VERSION 5.8 ;
BUSBITCHARS "[]" ;
DIVIDERCHAR "/" ;
UNITS
    DATABASE MICRONS 1000 ;
END UNITS

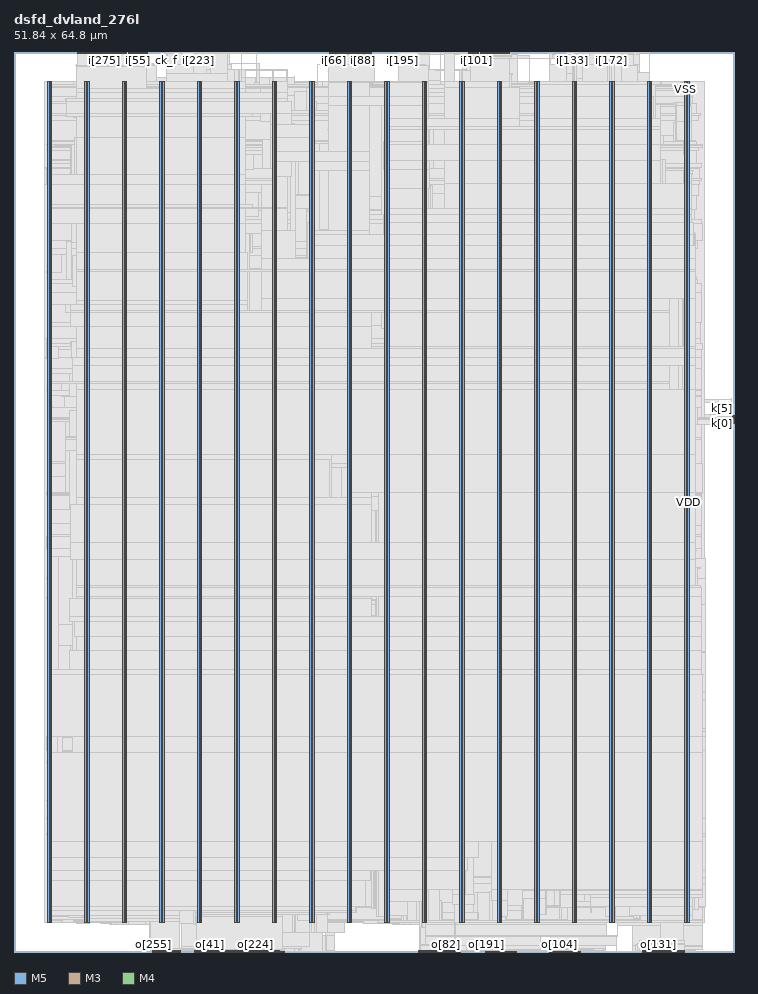
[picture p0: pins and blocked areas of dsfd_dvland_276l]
MACRO dsfd_dvland_276l
  FOREIGN dsfd_dvland_276l 0 0 ;
  CLASS BLOCK ;
  SIZE 51.84 BY 64.8 ;
  PIN ck
    DIRECTION INPUT ;
    USE SIGNAL ;
    PORT
      LAYER M5 ;
        RECT  16.08 0 16.104 0.084 ;
    END
  END ck
  PIN ck_f
    DIRECTION INPUT ;
    USE SIGNAL ;
    PORT
      LAYER M3 ;
        RECT  10.98 64.763 10.998 64.8 ;
    END
  END ck_f
  PIN fault
    DIRECTION OUTPUT ;
    USE SIGNAL ;
    PORT
      LAYER M5 ;
        RECT  16.176 0 16.2 0.084 ;
    END
  END fault
  PIN i[0]
    DIRECTION INPUT ;
    USE SIGNAL ;
    PORT
      LAYER M3 ;
        RECT  11.052 64.763 11.07 64.8 ;
    END
  END i[0]
  PIN i[100]
    DIRECTION INPUT ;
    USE SIGNAL ;
    PORT
      LAYER M5 ;
        RECT  33.168 64.716 33.192 64.8 ;
    END
  END i[100]
  PIN i[101]
    DIRECTION INPUT ;
    USE SIGNAL ;
    PORT
      LAYER M5 ;
        RECT  33.264 64.716 33.288 64.8 ;
    END
  END i[101]
  PIN i[102]
    DIRECTION INPUT ;
    USE SIGNAL ;
    PORT
      LAYER M5 ;
        RECT  33.36 64.716 33.384 64.8 ;
    END
  END i[102]
  PIN i[103]
    DIRECTION INPUT ;
    USE SIGNAL ;
    PORT
      LAYER M5 ;
        RECT  33.456 64.716 33.48 64.8 ;
    END
  END i[103]
  PIN i[104]
    DIRECTION INPUT ;
    USE SIGNAL ;
    PORT
      LAYER M5 ;
        RECT  33.552 64.716 33.576 64.8 ;
    END
  END i[104]
  PIN i[105]
    DIRECTION INPUT ;
    USE SIGNAL ;
    PORT
      LAYER M5 ;
        RECT  33.648 64.716 33.672 64.8 ;
    END
  END i[105]
  PIN i[106]
    DIRECTION INPUT ;
    USE SIGNAL ;
    PORT
      LAYER M5 ;
        RECT  33.744 64.716 33.768 64.8 ;
    END
  END i[106]
  PIN i[107]
    DIRECTION INPUT ;
    USE SIGNAL ;
    PORT
      LAYER M5 ;
        RECT  33.84 64.716 33.864 64.8 ;
    END
  END i[107]
  PIN i[108]
    DIRECTION INPUT ;
    USE SIGNAL ;
    PORT
      LAYER M5 ;
        RECT  33.936 64.716 33.96 64.8 ;
    END
  END i[108]
  PIN i[109]
    DIRECTION INPUT ;
    USE SIGNAL ;
    PORT
      LAYER M5 ;
        RECT  34.032 64.716 34.056 64.8 ;
    END
  END i[109]
  PIN i[10]
    DIRECTION INPUT ;
    USE SIGNAL ;
    PORT
      LAYER M3 ;
        RECT  11.772 64.763 11.79 64.8 ;
    END
  END i[10]
  PIN i[110]
    DIRECTION INPUT ;
    USE SIGNAL ;
    PORT
      LAYER M5 ;
        RECT  34.128 64.716 34.152 64.8 ;
    END
  END i[110]
  PIN i[111]
    DIRECTION INPUT ;
    USE SIGNAL ;
    PORT
      LAYER M5 ;
        RECT  34.224 64.716 34.248 64.8 ;
    END
  END i[111]
  PIN i[112]
    DIRECTION INPUT ;
    USE SIGNAL ;
    PORT
      LAYER M5 ;
        RECT  34.32 64.716 34.344 64.8 ;
    END
  END i[112]
  PIN i[113]
    DIRECTION INPUT ;
    USE SIGNAL ;
    PORT
      LAYER M5 ;
        RECT  34.416 64.716 34.44 64.8 ;
    END
  END i[113]
  PIN i[114]
    DIRECTION INPUT ;
    USE SIGNAL ;
    PORT
      LAYER M5 ;
        RECT  34.512 64.716 34.536 64.8 ;
    END
  END i[114]
  PIN i[115]
    DIRECTION INPUT ;
    USE SIGNAL ;
    PORT
      LAYER M5 ;
        RECT  34.608 64.716 34.632 64.8 ;
    END
  END i[115]
  PIN i[116]
    DIRECTION INPUT ;
    USE SIGNAL ;
    PORT
      LAYER M5 ;
        RECT  34.704 64.716 34.728 64.8 ;
    END
  END i[116]
  PIN i[117]
    DIRECTION INPUT ;
    USE SIGNAL ;
    PORT
      LAYER M5 ;
        RECT  34.8 64.716 34.824 64.8 ;
    END
  END i[117]
  PIN i[118]
    DIRECTION INPUT ;
    USE SIGNAL ;
    PORT
      LAYER M5 ;
        RECT  34.896 64.716 34.92 64.8 ;
    END
  END i[118]
  PIN i[119]
    DIRECTION INPUT ;
    USE SIGNAL ;
    PORT
      LAYER M5 ;
        RECT  34.992 64.716 35.016 64.8 ;
    END
  END i[119]
  PIN i[11]
    DIRECTION INPUT ;
    USE SIGNAL ;
    PORT
      LAYER M3 ;
        RECT  11.844 64.763 11.862 64.8 ;
    END
  END i[11]
  PIN i[120]
    DIRECTION INPUT ;
    USE SIGNAL ;
    PORT
      LAYER M5 ;
        RECT  35.088 64.716 35.112 64.8 ;
    END
  END i[120]
  PIN i[121]
    DIRECTION INPUT ;
    USE SIGNAL ;
    PORT
      LAYER M5 ;
        RECT  35.184 64.716 35.208 64.8 ;
    END
  END i[121]
  PIN i[122]
    DIRECTION INPUT ;
    USE SIGNAL ;
    PORT
      LAYER M5 ;
        RECT  35.28 64.716 35.304 64.8 ;
    END
  END i[122]
  PIN i[123]
    DIRECTION INPUT ;
    USE SIGNAL ;
    PORT
      LAYER M5 ;
        RECT  35.376 64.716 35.4 64.8 ;
    END
  END i[123]
  PIN i[124]
    DIRECTION INPUT ;
    USE SIGNAL ;
    PORT
      LAYER M5 ;
        RECT  35.472 64.716 35.496 64.8 ;
    END
  END i[124]
  PIN i[125]
    DIRECTION INPUT ;
    USE SIGNAL ;
    PORT
      LAYER M5 ;
        RECT  35.568 64.716 35.592 64.8 ;
    END
  END i[125]
  PIN i[126]
    DIRECTION INPUT ;
    USE SIGNAL ;
    PORT
      LAYER M5 ;
        RECT  35.664 64.716 35.688 64.8 ;
    END
  END i[126]
  PIN i[127]
    DIRECTION INPUT ;
    USE SIGNAL ;
    PORT
      LAYER M3 ;
        RECT  39.78 64.763 39.798 64.8 ;
    END
  END i[127]
  PIN i[128]
    DIRECTION INPUT ;
    USE SIGNAL ;
    PORT
      LAYER M3 ;
        RECT  39.852 64.763 39.87 64.8 ;
    END
  END i[128]
  PIN i[129]
    DIRECTION INPUT ;
    USE SIGNAL ;
    PORT
      LAYER M3 ;
        RECT  39.924 64.763 39.942 64.8 ;
    END
  END i[129]
  PIN i[12]
    DIRECTION INPUT ;
    USE SIGNAL ;
    PORT
      LAYER M3 ;
        RECT  11.916 64.763 11.934 64.8 ;
    END
  END i[12]
  PIN i[130]
    DIRECTION INPUT ;
    USE SIGNAL ;
    PORT
      LAYER M3 ;
        RECT  39.996 64.763 40.014 64.8 ;
    END
  END i[130]
  PIN i[131]
    DIRECTION INPUT ;
    USE SIGNAL ;
    PORT
      LAYER M3 ;
        RECT  40.068 64.763 40.086 64.8 ;
    END
  END i[131]
  PIN i[132]
    DIRECTION INPUT ;
    USE SIGNAL ;
    PORT
      LAYER M3 ;
        RECT  40.14 64.763 40.158 64.8 ;
    END
  END i[132]
  PIN i[133]
    DIRECTION INPUT ;
    USE SIGNAL ;
    PORT
      LAYER M3 ;
        RECT  40.212 64.763 40.23 64.8 ;
    END
  END i[133]
  PIN i[134]
    DIRECTION INPUT ;
    USE SIGNAL ;
    PORT
      LAYER M3 ;
        RECT  40.284 64.763 40.302 64.8 ;
    END
  END i[134]
  PIN i[135]
    DIRECTION INPUT ;
    USE SIGNAL ;
    PORT
      LAYER M3 ;
        RECT  40.356 64.763 40.374 64.8 ;
    END
  END i[135]
  PIN i[136]
    DIRECTION INPUT ;
    USE SIGNAL ;
    PORT
      LAYER M3 ;
        RECT  40.428 64.763 40.446 64.8 ;
    END
  END i[136]
  PIN i[137]
    DIRECTION INPUT ;
    USE SIGNAL ;
    PORT
      LAYER M3 ;
        RECT  40.5 64.763 40.518 64.8 ;
    END
  END i[137]
  PIN i[138]
    DIRECTION INPUT ;
    USE SIGNAL ;
    PORT
      LAYER M3 ;
        RECT  40.572 64.763 40.59 64.8 ;
    END
  END i[138]
  PIN i[139]
    DIRECTION INPUT ;
    USE SIGNAL ;
    PORT
      LAYER M3 ;
        RECT  40.644 64.763 40.662 64.8 ;
    END
  END i[139]
  PIN i[13]
    DIRECTION INPUT ;
    USE SIGNAL ;
    PORT
      LAYER M3 ;
        RECT  11.988 64.763 12.006 64.8 ;
    END
  END i[13]
  PIN i[140]
    DIRECTION INPUT ;
    USE SIGNAL ;
    PORT
      LAYER M3 ;
        RECT  40.716 64.763 40.734 64.8 ;
    END
  END i[140]
  PIN i[141]
    DIRECTION INPUT ;
    USE SIGNAL ;
    PORT
      LAYER M3 ;
        RECT  40.788 64.763 40.806 64.8 ;
    END
  END i[141]
  PIN i[142]
    DIRECTION INPUT ;
    USE SIGNAL ;
    PORT
      LAYER M3 ;
        RECT  40.86 64.763 40.878 64.8 ;
    END
  END i[142]
  PIN i[143]
    DIRECTION INPUT ;
    USE SIGNAL ;
    PORT
      LAYER M3 ;
        RECT  40.932 64.763 40.95 64.8 ;
    END
  END i[143]
  PIN i[144]
    DIRECTION INPUT ;
    USE SIGNAL ;
    PORT
      LAYER M3 ;
        RECT  41.004 64.763 41.022 64.8 ;
    END
  END i[144]
  PIN i[145]
    DIRECTION INPUT ;
    USE SIGNAL ;
    PORT
      LAYER M3 ;
        RECT  41.076 64.763 41.094 64.8 ;
    END
  END i[145]
  PIN i[146]
    DIRECTION INPUT ;
    USE SIGNAL ;
    PORT
      LAYER M3 ;
        RECT  41.148 64.763 41.166 64.8 ;
    END
  END i[146]
  PIN i[147]
    DIRECTION INPUT ;
    USE SIGNAL ;
    PORT
      LAYER M3 ;
        RECT  41.22 64.763 41.238 64.8 ;
    END
  END i[147]
  PIN i[148]
    DIRECTION INPUT ;
    USE SIGNAL ;
    PORT
      LAYER M3 ;
        RECT  41.292 64.763 41.31 64.8 ;
    END
  END i[148]
  PIN i[149]
    DIRECTION INPUT ;
    USE SIGNAL ;
    PORT
      LAYER M3 ;
        RECT  41.364 64.763 41.382 64.8 ;
    END
  END i[149]
  PIN i[14]
    DIRECTION INPUT ;
    USE SIGNAL ;
    PORT
      LAYER M3 ;
        RECT  12.06 64.763 12.078 64.8 ;
    END
  END i[14]
  PIN i[150]
    DIRECTION INPUT ;
    USE SIGNAL ;
    PORT
      LAYER M3 ;
        RECT  41.436 64.763 41.454 64.8 ;
    END
  END i[150]
  PIN i[151]
    DIRECTION INPUT ;
    USE SIGNAL ;
    PORT
      LAYER M3 ;
        RECT  41.508 64.763 41.526 64.8 ;
    END
  END i[151]
  PIN i[152]
    DIRECTION INPUT ;
    USE SIGNAL ;
    PORT
      LAYER M3 ;
        RECT  41.58 64.763 41.598 64.8 ;
    END
  END i[152]
  PIN i[153]
    DIRECTION INPUT ;
    USE SIGNAL ;
    PORT
      LAYER M3 ;
        RECT  41.652 64.763 41.67 64.8 ;
    END
  END i[153]
  PIN i[154]
    DIRECTION INPUT ;
    USE SIGNAL ;
    PORT
      LAYER M3 ;
        RECT  41.724 64.763 41.742 64.8 ;
    END
  END i[154]
  PIN i[155]
    DIRECTION INPUT ;
    USE SIGNAL ;
    PORT
      LAYER M3 ;
        RECT  41.796 64.763 41.814 64.8 ;
    END
  END i[155]
  PIN i[156]
    DIRECTION INPUT ;
    USE SIGNAL ;
    PORT
      LAYER M3 ;
        RECT  41.868 64.763 41.886 64.8 ;
    END
  END i[156]
  PIN i[157]
    DIRECTION INPUT ;
    USE SIGNAL ;
    PORT
      LAYER M3 ;
        RECT  41.94 64.763 41.958 64.8 ;
    END
  END i[157]
  PIN i[158]
    DIRECTION INPUT ;
    USE SIGNAL ;
    PORT
      LAYER M3 ;
        RECT  42.012 64.763 42.03 64.8 ;
    END
  END i[158]
  PIN i[159]
    DIRECTION INPUT ;
    USE SIGNAL ;
    PORT
      LAYER M3 ;
        RECT  42.084 64.763 42.102 64.8 ;
    END
  END i[159]
  PIN i[15]
    DIRECTION INPUT ;
    USE SIGNAL ;
    PORT
      LAYER M3 ;
        RECT  12.132 64.763 12.15 64.8 ;
    END
  END i[15]
  PIN i[160]
    DIRECTION INPUT ;
    USE SIGNAL ;
    PORT
      LAYER M3 ;
        RECT  42.156 64.763 42.174 64.8 ;
    END
  END i[160]
  PIN i[161]
    DIRECTION INPUT ;
    USE SIGNAL ;
    PORT
      LAYER M3 ;
        RECT  42.228 64.763 42.246 64.8 ;
    END
  END i[161]
  PIN i[162]
    DIRECTION INPUT ;
    USE SIGNAL ;
    PORT
      LAYER M3 ;
        RECT  42.3 64.763 42.318 64.8 ;
    END
  END i[162]
  PIN i[163]
    DIRECTION INPUT ;
    USE SIGNAL ;
    PORT
      LAYER M3 ;
        RECT  42.372 64.763 42.39 64.8 ;
    END
  END i[163]
  PIN i[164]
    DIRECTION INPUT ;
    USE SIGNAL ;
    PORT
      LAYER M3 ;
        RECT  42.444 64.763 42.462 64.8 ;
    END
  END i[164]
  PIN i[165]
    DIRECTION INPUT ;
    USE SIGNAL ;
    PORT
      LAYER M3 ;
        RECT  42.516 64.763 42.534 64.8 ;
    END
  END i[165]
  PIN i[166]
    DIRECTION INPUT ;
    USE SIGNAL ;
    PORT
      LAYER M3 ;
        RECT  42.588 64.763 42.606 64.8 ;
    END
  END i[166]
  PIN i[167]
    DIRECTION INPUT ;
    USE SIGNAL ;
    PORT
      LAYER M3 ;
        RECT  42.66 64.763 42.678 64.8 ;
    END
  END i[167]
  PIN i[168]
    DIRECTION INPUT ;
    USE SIGNAL ;
    PORT
      LAYER M3 ;
        RECT  42.732 64.763 42.75 64.8 ;
    END
  END i[168]
  PIN i[169]
    DIRECTION INPUT ;
    USE SIGNAL ;
    PORT
      LAYER M3 ;
        RECT  42.804 64.763 42.822 64.8 ;
    END
  END i[169]
  PIN i[16]
    DIRECTION INPUT ;
    USE SIGNAL ;
    PORT
      LAYER M3 ;
        RECT  12.204 64.763 12.222 64.8 ;
    END
  END i[16]
  PIN i[170]
    DIRECTION INPUT ;
    USE SIGNAL ;
    PORT
      LAYER M3 ;
        RECT  42.876 64.763 42.894 64.8 ;
    END
  END i[170]
  PIN i[171]
    DIRECTION INPUT ;
    USE SIGNAL ;
    PORT
      LAYER M3 ;
        RECT  42.948 64.763 42.966 64.8 ;
    END
  END i[171]
  PIN i[172]
    DIRECTION INPUT ;
    USE SIGNAL ;
    PORT
      LAYER M3 ;
        RECT  43.02 64.763 43.038 64.8 ;
    END
  END i[172]
  PIN i[173]
    DIRECTION INPUT ;
    USE SIGNAL ;
    PORT
      LAYER M3 ;
        RECT  43.092 64.763 43.11 64.8 ;
    END
  END i[173]
  PIN i[174]
    DIRECTION INPUT ;
    USE SIGNAL ;
    PORT
      LAYER M3 ;
        RECT  43.164 64.763 43.182 64.8 ;
    END
  END i[174]
  PIN i[175]
    DIRECTION INPUT ;
    USE SIGNAL ;
    PORT
      LAYER M3 ;
        RECT  43.236 64.763 43.254 64.8 ;
    END
  END i[175]
  PIN i[176]
    DIRECTION INPUT ;
    USE SIGNAL ;
    PORT
      LAYER M3 ;
        RECT  43.308 64.763 43.326 64.8 ;
    END
  END i[176]
  PIN i[177]
    DIRECTION INPUT ;
    USE SIGNAL ;
    PORT
      LAYER M3 ;
        RECT  43.38 64.763 43.398 64.8 ;
    END
  END i[177]
  PIN i[178]
    DIRECTION INPUT ;
    USE SIGNAL ;
    PORT
      LAYER M3 ;
        RECT  43.452 64.763 43.47 64.8 ;
    END
  END i[178]
  PIN i[179]
    DIRECTION INPUT ;
    USE SIGNAL ;
    PORT
      LAYER M3 ;
        RECT  43.524 64.763 43.542 64.8 ;
    END
  END i[179]
  PIN i[17]
    DIRECTION INPUT ;
    USE SIGNAL ;
    PORT
      LAYER M3 ;
        RECT  12.276 64.763 12.294 64.8 ;
    END
  END i[17]
  PIN i[180]
    DIRECTION INPUT ;
    USE SIGNAL ;
    PORT
      LAYER M3 ;
        RECT  43.596 64.763 43.614 64.8 ;
    END
  END i[180]
  PIN i[181]
    DIRECTION INPUT ;
    USE SIGNAL ;
    PORT
      LAYER M3 ;
        RECT  43.668 64.763 43.686 64.8 ;
    END
  END i[181]
  PIN i[182]
    DIRECTION INPUT ;
    USE SIGNAL ;
    PORT
      LAYER M3 ;
        RECT  43.74 64.763 43.758 64.8 ;
    END
  END i[182]
  PIN i[183]
    DIRECTION INPUT ;
    USE SIGNAL ;
    PORT
      LAYER M3 ;
        RECT  43.812 64.763 43.83 64.8 ;
    END
  END i[183]
  PIN i[184]
    DIRECTION INPUT ;
    USE SIGNAL ;
    PORT
      LAYER M3 ;
        RECT  43.884 64.763 43.902 64.8 ;
    END
  END i[184]
  PIN i[185]
    DIRECTION INPUT ;
    USE SIGNAL ;
    PORT
      LAYER M3 ;
        RECT  43.956 64.763 43.974 64.8 ;
    END
  END i[185]
  PIN i[186]
    DIRECTION INPUT ;
    USE SIGNAL ;
    PORT
      LAYER M3 ;
        RECT  44.028 64.763 44.046 64.8 ;
    END
  END i[186]
  PIN i[187]
    DIRECTION INPUT ;
    USE SIGNAL ;
    PORT
      LAYER M3 ;
        RECT  44.1 64.763 44.118 64.8 ;
    END
  END i[187]
  PIN i[188]
    DIRECTION INPUT ;
    USE SIGNAL ;
    PORT
      LAYER M3 ;
        RECT  44.172 64.763 44.19 64.8 ;
    END
  END i[188]
  PIN i[189]
    DIRECTION INPUT ;
    USE SIGNAL ;
    PORT
      LAYER M3 ;
        RECT  44.244 64.763 44.262 64.8 ;
    END
  END i[189]
  PIN i[18]
    DIRECTION INPUT ;
    USE SIGNAL ;
    PORT
      LAYER M3 ;
        RECT  12.348 64.763 12.366 64.8 ;
    END
  END i[18]
  PIN i[190]
    DIRECTION INPUT ;
    USE SIGNAL ;
    PORT
      LAYER M3 ;
        RECT  44.316 64.763 44.334 64.8 ;
    END
  END i[190]
  PIN i[191]
    DIRECTION INPUT ;
    USE SIGNAL ;
    PORT
      LAYER M3 ;
        RECT  27.684 64.763 27.702 64.8 ;
    END
  END i[191]
  PIN i[192]
    DIRECTION INPUT ;
    USE SIGNAL ;
    PORT
      LAYER M3 ;
        RECT  27.756 64.763 27.774 64.8 ;
    END
  END i[192]
  PIN i[193]
    DIRECTION INPUT ;
    USE SIGNAL ;
    PORT
      LAYER M3 ;
        RECT  27.828 64.763 27.846 64.8 ;
    END
  END i[193]
  PIN i[194]
    DIRECTION INPUT ;
    USE SIGNAL ;
    PORT
      LAYER M3 ;
        RECT  27.9 64.763 27.918 64.8 ;
    END
  END i[194]
  PIN i[195]
    DIRECTION INPUT ;
    USE SIGNAL ;
    PORT
      LAYER M3 ;
        RECT  27.972 64.763 27.99 64.8 ;
    END
  END i[195]
  PIN i[196]
    DIRECTION INPUT ;
    USE SIGNAL ;
    PORT
      LAYER M3 ;
        RECT  28.044 64.763 28.062 64.8 ;
    END
  END i[196]
  PIN i[197]
    DIRECTION INPUT ;
    USE SIGNAL ;
    PORT
      LAYER M3 ;
        RECT  28.116 64.763 28.134 64.8 ;
    END
  END i[197]
  PIN i[198]
    DIRECTION INPUT ;
    USE SIGNAL ;
    PORT
      LAYER M3 ;
        RECT  28.188 64.763 28.206 64.8 ;
    END
  END i[198]
  PIN i[199]
    DIRECTION INPUT ;
    USE SIGNAL ;
    PORT
      LAYER M3 ;
        RECT  28.26 64.763 28.278 64.8 ;
    END
  END i[199]
  PIN i[19]
    DIRECTION INPUT ;
    USE SIGNAL ;
    PORT
      LAYER M3 ;
        RECT  12.42 64.763 12.438 64.8 ;
    END
  END i[19]
  PIN i[1]
    DIRECTION INPUT ;
    USE SIGNAL ;
    PORT
      LAYER M3 ;
        RECT  11.124 64.763 11.142 64.8 ;
    END
  END i[1]
  PIN i[200]
    DIRECTION INPUT ;
    USE SIGNAL ;
    PORT
      LAYER M3 ;
        RECT  28.332 64.763 28.35 64.8 ;
    END
  END i[200]
  PIN i[201]
    DIRECTION INPUT ;
    USE SIGNAL ;
    PORT
      LAYER M3 ;
        RECT  28.404 64.763 28.422 64.8 ;
    END
  END i[201]
  PIN i[202]
    DIRECTION INPUT ;
    USE SIGNAL ;
    PORT
      LAYER M3 ;
        RECT  28.476 64.763 28.494 64.8 ;
    END
  END i[202]
  PIN i[203]
    DIRECTION INPUT ;
    USE SIGNAL ;
    PORT
      LAYER M3 ;
        RECT  28.548 64.763 28.566 64.8 ;
    END
  END i[203]
  PIN i[204]
    DIRECTION INPUT ;
    USE SIGNAL ;
    PORT
      LAYER M3 ;
        RECT  28.62 64.763 28.638 64.8 ;
    END
  END i[204]
  PIN i[205]
    DIRECTION INPUT ;
    USE SIGNAL ;
    PORT
      LAYER M3 ;
        RECT  28.692 64.763 28.71 64.8 ;
    END
  END i[205]
  PIN i[206]
    DIRECTION INPUT ;
    USE SIGNAL ;
    PORT
      LAYER M3 ;
        RECT  28.764 64.763 28.782 64.8 ;
    END
  END i[206]
  PIN i[207]
    DIRECTION INPUT ;
    USE SIGNAL ;
    PORT
      LAYER M3 ;
        RECT  28.836 64.763 28.854 64.8 ;
    END
  END i[207]
  PIN i[208]
    DIRECTION INPUT ;
    USE SIGNAL ;
    PORT
      LAYER M3 ;
        RECT  28.908 64.763 28.926 64.8 ;
    END
  END i[208]
  PIN i[209]
    DIRECTION INPUT ;
    USE SIGNAL ;
    PORT
      LAYER M3 ;
        RECT  28.98 64.763 28.998 64.8 ;
    END
  END i[209]
  PIN i[20]
    DIRECTION INPUT ;
    USE SIGNAL ;
    PORT
      LAYER M3 ;
        RECT  12.492 64.763 12.51 64.8 ;
    END
  END i[20]
  PIN i[210]
    DIRECTION INPUT ;
    USE SIGNAL ;
    PORT
      LAYER M3 ;
        RECT  29.052 64.763 29.07 64.8 ;
    END
  END i[210]
  PIN i[211]
    DIRECTION INPUT ;
    USE SIGNAL ;
    PORT
      LAYER M3 ;
        RECT  29.124 64.763 29.142 64.8 ;
    END
  END i[211]
  PIN i[212]
    DIRECTION INPUT ;
    USE SIGNAL ;
    PORT
      LAYER M3 ;
        RECT  29.196 64.763 29.214 64.8 ;
    END
  END i[212]
  PIN i[213]
    DIRECTION INPUT ;
    USE SIGNAL ;
    PORT
      LAYER M3 ;
        RECT  29.268 64.763 29.286 64.8 ;
    END
  END i[213]
  PIN i[214]
    DIRECTION INPUT ;
    USE SIGNAL ;
    PORT
      LAYER M3 ;
        RECT  29.34 64.763 29.358 64.8 ;
    END
  END i[214]
  PIN i[215]
    DIRECTION INPUT ;
    USE SIGNAL ;
    PORT
      LAYER M3 ;
        RECT  29.412 64.763 29.43 64.8 ;
    END
  END i[215]
  PIN i[216]
    DIRECTION INPUT ;
    USE SIGNAL ;
    PORT
      LAYER M3 ;
        RECT  29.484 64.763 29.502 64.8 ;
    END
  END i[216]
  PIN i[217]
    DIRECTION INPUT ;
    USE SIGNAL ;
    PORT
      LAYER M3 ;
        RECT  29.556 64.763 29.574 64.8 ;
    END
  END i[217]
  PIN i[218]
    DIRECTION INPUT ;
    USE SIGNAL ;
    PORT
      LAYER M3 ;
        RECT  29.628 64.763 29.646 64.8 ;
    END
  END i[218]
  PIN i[219]
    DIRECTION INPUT ;
    USE SIGNAL ;
    PORT
      LAYER M3 ;
        RECT  29.7 64.763 29.718 64.8 ;
    END
  END i[219]
  PIN i[21]
    DIRECTION INPUT ;
    USE SIGNAL ;
    PORT
      LAYER M3 ;
        RECT  12.564 64.763 12.582 64.8 ;
    END
  END i[21]
  PIN i[220]
    DIRECTION INPUT ;
    USE SIGNAL ;
    PORT
      LAYER M3 ;
        RECT  29.772 64.763 29.79 64.8 ;
    END
  END i[220]
  PIN i[221]
    DIRECTION INPUT ;
    USE SIGNAL ;
    PORT
      LAYER M3 ;
        RECT  29.844 64.763 29.862 64.8 ;
    END
  END i[221]
  PIN i[222]
    DIRECTION INPUT ;
    USE SIGNAL ;
    PORT
      LAYER M3 ;
        RECT  29.916 64.763 29.934 64.8 ;
    END
  END i[222]
  PIN i[223]
    DIRECTION INPUT ;
    USE SIGNAL ;
    PORT
      LAYER M3 ;
        RECT  13.284 64.763 13.302 64.8 ;
    END
  END i[223]
  PIN i[224]
    DIRECTION INPUT ;
    USE SIGNAL ;
    PORT
      LAYER M3 ;
        RECT  13.356 64.763 13.374 64.8 ;
    END
  END i[224]
  PIN i[225]
    DIRECTION INPUT ;
    USE SIGNAL ;
    PORT
      LAYER M3 ;
        RECT  13.428 64.763 13.446 64.8 ;
    END
  END i[225]
  PIN i[226]
    DIRECTION INPUT ;
    USE SIGNAL ;
    PORT
      LAYER M3 ;
        RECT  13.5 64.763 13.518 64.8 ;
    END
  END i[226]
  PIN i[227]
    DIRECTION INPUT ;
    USE SIGNAL ;
    PORT
      LAYER M3 ;
        RECT  13.572 64.763 13.59 64.8 ;
    END
  END i[227]
  PIN i[228]
    DIRECTION INPUT ;
    USE SIGNAL ;
    PORT
      LAYER M3 ;
        RECT  13.644 64.763 13.662 64.8 ;
    END
  END i[228]
  PIN i[229]
    DIRECTION INPUT ;
    USE SIGNAL ;
    PORT
      LAYER M3 ;
        RECT  13.716 64.763 13.734 64.8 ;
    END
  END i[229]
  PIN i[22]
    DIRECTION INPUT ;
    USE SIGNAL ;
    PORT
      LAYER M3 ;
        RECT  12.636 64.763 12.654 64.8 ;
    END
  END i[22]
  PIN i[230]
    DIRECTION INPUT ;
    USE SIGNAL ;
    PORT
      LAYER M3 ;
        RECT  13.788 64.763 13.806 64.8 ;
    END
  END i[230]
  PIN i[231]
    DIRECTION INPUT ;
    USE SIGNAL ;
    PORT
      LAYER M3 ;
        RECT  13.86 64.763 13.878 64.8 ;
    END
  END i[231]
  PIN i[232]
    DIRECTION INPUT ;
    USE SIGNAL ;
    PORT
      LAYER M3 ;
        RECT  13.932 64.763 13.95 64.8 ;
    END
  END i[232]
  PIN i[233]
    DIRECTION INPUT ;
    USE SIGNAL ;
    PORT
      LAYER M3 ;
        RECT  14.004 64.763 14.022 64.8 ;
    END
  END i[233]
  PIN i[234]
    DIRECTION INPUT ;
    USE SIGNAL ;
    PORT
      LAYER M3 ;
        RECT  14.076 64.763 14.094 64.8 ;
    END
  END i[234]
  PIN i[235]
    DIRECTION INPUT ;
    USE SIGNAL ;
    PORT
      LAYER M3 ;
        RECT  14.148 64.763 14.166 64.8 ;
    END
  END i[235]
  PIN i[236]
    DIRECTION INPUT ;
    USE SIGNAL ;
    PORT
      LAYER M3 ;
        RECT  14.22 64.763 14.238 64.8 ;
    END
  END i[236]
  PIN i[237]
    DIRECTION INPUT ;
    USE SIGNAL ;
    PORT
      LAYER M3 ;
        RECT  14.292 64.763 14.31 64.8 ;
    END
  END i[237]
  PIN i[238]
    DIRECTION INPUT ;
    USE SIGNAL ;
    PORT
      LAYER M3 ;
        RECT  14.364 64.763 14.382 64.8 ;
    END
  END i[238]
  PIN i[239]
    DIRECTION INPUT ;
    USE SIGNAL ;
    PORT
      LAYER M3 ;
        RECT  14.436 64.763 14.454 64.8 ;
    END
  END i[239]
  PIN i[23]
    DIRECTION INPUT ;
    USE SIGNAL ;
    PORT
      LAYER M3 ;
        RECT  12.708 64.763 12.726 64.8 ;
    END
  END i[23]
  PIN i[240]
    DIRECTION INPUT ;
    USE SIGNAL ;
    PORT
      LAYER M3 ;
        RECT  14.508 64.763 14.526 64.8 ;
    END
  END i[240]
  PIN i[241]
    DIRECTION INPUT ;
    USE SIGNAL ;
    PORT
      LAYER M3 ;
        RECT  14.58 64.763 14.598 64.8 ;
    END
  END i[241]
  PIN i[242]
    DIRECTION INPUT ;
    USE SIGNAL ;
    PORT
      LAYER M3 ;
        RECT  14.652 64.763 14.67 64.8 ;
    END
  END i[242]
  PIN i[243]
    DIRECTION INPUT ;
    USE SIGNAL ;
    PORT
      LAYER M3 ;
        RECT  14.724 64.763 14.742 64.8 ;
    END
  END i[243]
  PIN i[244]
    DIRECTION INPUT ;
    USE SIGNAL ;
    PORT
      LAYER M3 ;
        RECT  14.796 64.763 14.814 64.8 ;
    END
  END i[244]
  PIN i[245]
    DIRECTION INPUT ;
    USE SIGNAL ;
    PORT
      LAYER M3 ;
        RECT  14.868 64.763 14.886 64.8 ;
    END
  END i[245]
  PIN i[246]
    DIRECTION INPUT ;
    USE SIGNAL ;
    PORT
      LAYER M3 ;
        RECT  14.94 64.763 14.958 64.8 ;
    END
  END i[246]
  PIN i[247]
    DIRECTION INPUT ;
    USE SIGNAL ;
    PORT
      LAYER M3 ;
        RECT  15.012 64.763 15.03 64.8 ;
    END
  END i[247]
  PIN i[248]
    DIRECTION INPUT ;
    USE SIGNAL ;
    PORT
      LAYER M3 ;
        RECT  15.084 64.763 15.102 64.8 ;
    END
  END i[248]
  PIN i[249]
    DIRECTION INPUT ;
    USE SIGNAL ;
    PORT
      LAYER M3 ;
        RECT  15.156 64.763 15.174 64.8 ;
    END
  END i[249]
  PIN i[24]
    DIRECTION INPUT ;
    USE SIGNAL ;
    PORT
      LAYER M3 ;
        RECT  12.78 64.763 12.798 64.8 ;
    END
  END i[24]
  PIN i[250]
    DIRECTION INPUT ;
    USE SIGNAL ;
    PORT
      LAYER M3 ;
        RECT  15.228 64.763 15.246 64.8 ;
    END
  END i[250]
  PIN i[251]
    DIRECTION INPUT ;
    USE SIGNAL ;
    PORT
      LAYER M3 ;
        RECT  15.3 64.763 15.318 64.8 ;
    END
  END i[251]
  PIN i[252]
    DIRECTION INPUT ;
    USE SIGNAL ;
    PORT
      LAYER M3 ;
        RECT  15.372 64.763 15.39 64.8 ;
    END
  END i[252]
  PIN i[253]
    DIRECTION INPUT ;
    USE SIGNAL ;
    PORT
      LAYER M3 ;
        RECT  15.444 64.763 15.462 64.8 ;
    END
  END i[253]
  PIN i[254]
    DIRECTION INPUT ;
    USE SIGNAL ;
    PORT
      LAYER M3 ;
        RECT  15.516 64.763 15.534 64.8 ;
    END
  END i[254]
  PIN i[255]
    DIRECTION INPUT ;
    USE SIGNAL ;
    PORT
      LAYER M5 ;
        RECT  4.56 64.716 4.584 64.8 ;
    END
  END i[255]
  PIN i[256]
    DIRECTION INPUT ;
    USE SIGNAL ;
    PORT
      LAYER M5 ;
        RECT  4.656 64.716 4.68 64.8 ;
    END
  END i[256]
  PIN i[257]
    DIRECTION INPUT ;
    USE SIGNAL ;
    PORT
      LAYER M5 ;
        RECT  4.752 64.716 4.776 64.8 ;
    END
  END i[257]
  PIN i[258]
    DIRECTION INPUT ;
    USE SIGNAL ;
    PORT
      LAYER M5 ;
        RECT  4.848 64.716 4.872 64.8 ;
    END
  END i[258]
  PIN i[259]
    DIRECTION INPUT ;
    USE SIGNAL ;
    PORT
      LAYER M5 ;
        RECT  4.944 64.716 4.968 64.8 ;
    END
  END i[259]
  PIN i[25]
    DIRECTION INPUT ;
    USE SIGNAL ;
    PORT
      LAYER M3 ;
        RECT  12.852 64.763 12.87 64.8 ;
    END
  END i[25]
  PIN i[260]
    DIRECTION INPUT ;
    USE SIGNAL ;
    PORT
      LAYER M5 ;
        RECT  5.04 64.716 5.064 64.8 ;
    END
  END i[260]
  PIN i[261]
    DIRECTION INPUT ;
    USE SIGNAL ;
    PORT
      LAYER M5 ;
        RECT  5.136 64.716 5.16 64.8 ;
    END
  END i[261]
  PIN i[262]
    DIRECTION INPUT ;
    USE SIGNAL ;
    PORT
      LAYER M5 ;
        RECT  5.232 64.716 5.256 64.8 ;
    END
  END i[262]
  PIN i[263]
    DIRECTION INPUT ;
    USE SIGNAL ;
    PORT
      LAYER M5 ;
        RECT  5.328 64.716 5.352 64.8 ;
    END
  END i[263]
  PIN i[264]
    DIRECTION INPUT ;
    USE SIGNAL ;
    PORT
      LAYER M5 ;
        RECT  5.424 64.716 5.448 64.8 ;
    END
  END i[264]
  PIN i[265]
    DIRECTION INPUT ;
    USE SIGNAL ;
    PORT
      LAYER M5 ;
        RECT  5.52 64.716 5.544 64.8 ;
    END
  END i[265]
  PIN i[266]
    DIRECTION INPUT ;
    USE SIGNAL ;
    PORT
      LAYER M5 ;
        RECT  5.616 64.716 5.64 64.8 ;
    END
  END i[266]
  PIN i[267]
    DIRECTION INPUT ;
    USE SIGNAL ;
    PORT
      LAYER M5 ;
        RECT  5.712 64.716 5.736 64.8 ;
    END
  END i[267]
  PIN i[268]
    DIRECTION INPUT ;
    USE SIGNAL ;
    PORT
      LAYER M5 ;
        RECT  5.808 64.716 5.832 64.8 ;
    END
  END i[268]
  PIN i[269]
    DIRECTION INPUT ;
    USE SIGNAL ;
    PORT
      LAYER M5 ;
        RECT  5.904 64.716 5.928 64.8 ;
    END
  END i[269]
  PIN i[26]
    DIRECTION INPUT ;
    USE SIGNAL ;
    PORT
      LAYER M3 ;
        RECT  12.924 64.763 12.942 64.8 ;
    END
  END i[26]
  PIN i[270]
    DIRECTION INPUT ;
    USE SIGNAL ;
    PORT
      LAYER M5 ;
        RECT  6 64.716 6.024 64.8 ;
    END
  END i[270]
  PIN i[271]
    DIRECTION INPUT ;
    USE SIGNAL ;
    PORT
      LAYER M5 ;
        RECT  6.096 64.716 6.12 64.8 ;
    END
  END i[271]
  PIN i[272]
    DIRECTION INPUT ;
    USE SIGNAL ;
    PORT
      LAYER M5 ;
        RECT  6.192 64.716 6.216 64.8 ;
    END
  END i[272]
  PIN i[273]
    DIRECTION INPUT ;
    USE SIGNAL ;
    PORT
      LAYER M5 ;
        RECT  6.288 64.716 6.312 64.8 ;
    END
  END i[273]
  PIN i[274]
    DIRECTION INPUT ;
    USE SIGNAL ;
    PORT
      LAYER M5 ;
        RECT  6.384 64.716 6.408 64.8 ;
    END
  END i[274]
  PIN i[275]
    DIRECTION INPUT ;
    USE SIGNAL ;
    PORT
      LAYER M5 ;
        RECT  6.48 64.716 6.504 64.8 ;
    END
  END i[275]
  PIN i[27]
    DIRECTION INPUT ;
    USE SIGNAL ;
    PORT
      LAYER M3 ;
        RECT  12.996 64.763 13.014 64.8 ;
    END
  END i[27]
  PIN i[28]
    DIRECTION INPUT ;
    USE SIGNAL ;
    PORT
      LAYER M3 ;
        RECT  13.068 64.763 13.086 64.8 ;
    END
  END i[28]
  PIN i[29]
    DIRECTION INPUT ;
    USE SIGNAL ;
    PORT
      LAYER M3 ;
        RECT  13.14 64.763 13.158 64.8 ;
    END
  END i[29]
  PIN i[2]
    DIRECTION INPUT ;
    USE SIGNAL ;
    PORT
      LAYER M3 ;
        RECT  11.196 64.763 11.214 64.8 ;
    END
  END i[2]
  PIN i[30]
    DIRECTION INPUT ;
    USE SIGNAL ;
    PORT
      LAYER M3 ;
        RECT  13.212 64.763 13.23 64.8 ;
    END
  END i[30]
  PIN i[31]
    DIRECTION INPUT ;
    USE SIGNAL ;
    PORT
      LAYER M5 ;
        RECT  6.576 64.716 6.6 64.8 ;
    END
  END i[31]
  PIN i[32]
    DIRECTION INPUT ;
    USE SIGNAL ;
    PORT
      LAYER M5 ;
        RECT  6.672 64.716 6.696 64.8 ;
    END
  END i[32]
  PIN i[33]
    DIRECTION INPUT ;
    USE SIGNAL ;
    PORT
      LAYER M5 ;
        RECT  6.768 64.716 6.792 64.8 ;
    END
  END i[33]
  PIN i[34]
    DIRECTION INPUT ;
    USE SIGNAL ;
    PORT
      LAYER M5 ;
        RECT  6.864 64.716 6.888 64.8 ;
    END
  END i[34]
  PIN i[35]
    DIRECTION INPUT ;
    USE SIGNAL ;
    PORT
      LAYER M5 ;
        RECT  6.96 64.716 6.984 64.8 ;
    END
  END i[35]
  PIN i[36]
    DIRECTION INPUT ;
    USE SIGNAL ;
    PORT
      LAYER M5 ;
        RECT  7.056 64.716 7.08 64.8 ;
    END
  END i[36]
  PIN i[37]
    DIRECTION INPUT ;
    USE SIGNAL ;
    PORT
      LAYER M5 ;
        RECT  7.152 64.716 7.176 64.8 ;
    END
  END i[37]
  PIN i[38]
    DIRECTION INPUT ;
    USE SIGNAL ;
    PORT
      LAYER M5 ;
        RECT  7.248 64.716 7.272 64.8 ;
    END
  END i[38]
  PIN i[39]
    DIRECTION INPUT ;
    USE SIGNAL ;
    PORT
      LAYER M5 ;
        RECT  7.344 64.716 7.368 64.8 ;
    END
  END i[39]
  PIN i[3]
    DIRECTION INPUT ;
    USE SIGNAL ;
    PORT
      LAYER M3 ;
        RECT  11.268 64.763 11.286 64.8 ;
    END
  END i[3]
  PIN i[40]
    DIRECTION INPUT ;
    USE SIGNAL ;
    PORT
      LAYER M5 ;
        RECT  7.44 64.716 7.464 64.8 ;
    END
  END i[40]
  PIN i[41]
    DIRECTION INPUT ;
    USE SIGNAL ;
    PORT
      LAYER M5 ;
        RECT  7.536 64.716 7.56 64.8 ;
    END
  END i[41]
  PIN i[42]
    DIRECTION INPUT ;
    USE SIGNAL ;
    PORT
      LAYER M5 ;
        RECT  7.632 64.716 7.656 64.8 ;
    END
  END i[42]
  PIN i[43]
    DIRECTION INPUT ;
    USE SIGNAL ;
    PORT
      LAYER M5 ;
        RECT  7.728 64.716 7.752 64.8 ;
    END
  END i[43]
  PIN i[44]
    DIRECTION INPUT ;
    USE SIGNAL ;
    PORT
      LAYER M5 ;
        RECT  7.824 64.716 7.848 64.8 ;
    END
  END i[44]
  PIN i[45]
    DIRECTION INPUT ;
    USE SIGNAL ;
    PORT
      LAYER M5 ;
        RECT  7.92 64.716 7.944 64.8 ;
    END
  END i[45]
  PIN i[46]
    DIRECTION INPUT ;
    USE SIGNAL ;
    PORT
      LAYER M5 ;
        RECT  8.016 64.716 8.04 64.8 ;
    END
  END i[46]
  PIN i[47]
    DIRECTION INPUT ;
    USE SIGNAL ;
    PORT
      LAYER M5 ;
        RECT  8.112 64.716 8.136 64.8 ;
    END
  END i[47]
  PIN i[48]
    DIRECTION INPUT ;
    USE SIGNAL ;
    PORT
      LAYER M5 ;
        RECT  8.208 64.716 8.232 64.8 ;
    END
  END i[48]
  PIN i[49]
    DIRECTION INPUT ;
    USE SIGNAL ;
    PORT
      LAYER M5 ;
        RECT  8.304 64.716 8.328 64.8 ;
    END
  END i[49]
  PIN i[4]
    DIRECTION INPUT ;
    USE SIGNAL ;
    PORT
      LAYER M3 ;
        RECT  11.34 64.763 11.358 64.8 ;
    END
  END i[4]
  PIN i[50]
    DIRECTION INPUT ;
    USE SIGNAL ;
    PORT
      LAYER M5 ;
        RECT  8.4 64.716 8.424 64.8 ;
    END
  END i[50]
  PIN i[51]
    DIRECTION INPUT ;
    USE SIGNAL ;
    PORT
      LAYER M5 ;
        RECT  8.496 64.716 8.52 64.8 ;
    END
  END i[51]
  PIN i[52]
    DIRECTION INPUT ;
    USE SIGNAL ;
    PORT
      LAYER M5 ;
        RECT  8.592 64.716 8.616 64.8 ;
    END
  END i[52]
  PIN i[53]
    DIRECTION INPUT ;
    USE SIGNAL ;
    PORT
      LAYER M5 ;
        RECT  8.688 64.716 8.712 64.8 ;
    END
  END i[53]
  PIN i[54]
    DIRECTION INPUT ;
    USE SIGNAL ;
    PORT
      LAYER M5 ;
        RECT  8.784 64.716 8.808 64.8 ;
    END
  END i[54]
  PIN i[55]
    DIRECTION INPUT ;
    USE SIGNAL ;
    PORT
      LAYER M5 ;
        RECT  8.88 64.716 8.904 64.8 ;
    END
  END i[55]
  PIN i[56]
    DIRECTION INPUT ;
    USE SIGNAL ;
    PORT
      LAYER M5 ;
        RECT  8.976 64.716 9 64.8 ;
    END
  END i[56]
  PIN i[57]
    DIRECTION INPUT ;
    USE SIGNAL ;
    PORT
      LAYER M5 ;
        RECT  9.072 64.716 9.096 64.8 ;
    END
  END i[57]
  PIN i[58]
    DIRECTION INPUT ;
    USE SIGNAL ;
    PORT
      LAYER M5 ;
        RECT  9.168 64.716 9.192 64.8 ;
    END
  END i[58]
  PIN i[59]
    DIRECTION INPUT ;
    USE SIGNAL ;
    PORT
      LAYER M5 ;
        RECT  9.264 64.716 9.288 64.8 ;
    END
  END i[59]
  PIN i[5]
    DIRECTION INPUT ;
    USE SIGNAL ;
    PORT
      LAYER M3 ;
        RECT  11.412 64.763 11.43 64.8 ;
    END
  END i[5]
  PIN i[60]
    DIRECTION INPUT ;
    USE SIGNAL ;
    PORT
      LAYER M5 ;
        RECT  9.36 64.716 9.384 64.8 ;
    END
  END i[60]
  PIN i[61]
    DIRECTION INPUT ;
    USE SIGNAL ;
    PORT
      LAYER M5 ;
        RECT  9.456 64.716 9.48 64.8 ;
    END
  END i[61]
  PIN i[62]
    DIRECTION INPUT ;
    USE SIGNAL ;
    PORT
      LAYER M5 ;
        RECT  9.552 64.716 9.576 64.8 ;
    END
  END i[62]
  PIN i[63]
    DIRECTION INPUT ;
    USE SIGNAL ;
    PORT
      LAYER M5 ;
        RECT  22.704 64.716 22.728 64.8 ;
    END
  END i[63]
  PIN i[64]
    DIRECTION INPUT ;
    USE SIGNAL ;
    PORT
      LAYER M5 ;
        RECT  22.8 64.716 22.824 64.8 ;
    END
  END i[64]
  PIN i[65]
    DIRECTION INPUT ;
    USE SIGNAL ;
    PORT
      LAYER M5 ;
        RECT  22.896 64.716 22.92 64.8 ;
    END
  END i[65]
  PIN i[66]
    DIRECTION INPUT ;
    USE SIGNAL ;
    PORT
      LAYER M5 ;
        RECT  22.992 64.716 23.016 64.8 ;
    END
  END i[66]
  PIN i[67]
    DIRECTION INPUT ;
    USE SIGNAL ;
    PORT
      LAYER M5 ;
        RECT  23.088 64.716 23.112 64.8 ;
    END
  END i[67]
  PIN i[68]
    DIRECTION INPUT ;
    USE SIGNAL ;
    PORT
      LAYER M5 ;
        RECT  23.184 64.716 23.208 64.8 ;
    END
  END i[68]
  PIN i[69]
    DIRECTION INPUT ;
    USE SIGNAL ;
    PORT
      LAYER M5 ;
        RECT  23.28 64.716 23.304 64.8 ;
    END
  END i[69]
  PIN i[6]
    DIRECTION INPUT ;
    USE SIGNAL ;
    PORT
      LAYER M3 ;
        RECT  11.484 64.763 11.502 64.8 ;
    END
  END i[6]
  PIN i[70]
    DIRECTION INPUT ;
    USE SIGNAL ;
    PORT
      LAYER M5 ;
        RECT  23.376 64.716 23.4 64.8 ;
    END
  END i[70]
  PIN i[71]
    DIRECTION INPUT ;
    USE SIGNAL ;
    PORT
      LAYER M5 ;
        RECT  23.472 64.716 23.496 64.8 ;
    END
  END i[71]
  PIN i[72]
    DIRECTION INPUT ;
    USE SIGNAL ;
    PORT
      LAYER M5 ;
        RECT  23.568 64.716 23.592 64.8 ;
    END
  END i[72]
  PIN i[73]
    DIRECTION INPUT ;
    USE SIGNAL ;
    PORT
      LAYER M5 ;
        RECT  23.664 64.716 23.688 64.8 ;
    END
  END i[73]
  PIN i[74]
    DIRECTION INPUT ;
    USE SIGNAL ;
    PORT
      LAYER M5 ;
        RECT  23.76 64.716 23.784 64.8 ;
    END
  END i[74]
  PIN i[75]
    DIRECTION INPUT ;
    USE SIGNAL ;
    PORT
      LAYER M5 ;
        RECT  23.856 64.716 23.88 64.8 ;
    END
  END i[75]
  PIN i[76]
    DIRECTION INPUT ;
    USE SIGNAL ;
    PORT
      LAYER M5 ;
        RECT  23.952 64.716 23.976 64.8 ;
    END
  END i[76]
  PIN i[77]
    DIRECTION INPUT ;
    USE SIGNAL ;
    PORT
      LAYER M5 ;
        RECT  24.048 64.716 24.072 64.8 ;
    END
  END i[77]
  PIN i[78]
    DIRECTION INPUT ;
    USE SIGNAL ;
    PORT
      LAYER M5 ;
        RECT  24.144 64.716 24.168 64.8 ;
    END
  END i[78]
  PIN i[79]
    DIRECTION INPUT ;
    USE SIGNAL ;
    PORT
      LAYER M5 ;
        RECT  24.24 64.716 24.264 64.8 ;
    END
  END i[79]
  PIN i[7]
    DIRECTION INPUT ;
    USE SIGNAL ;
    PORT
      LAYER M3 ;
        RECT  11.556 64.763 11.574 64.8 ;
    END
  END i[7]
  PIN i[80]
    DIRECTION INPUT ;
    USE SIGNAL ;
    PORT
      LAYER M5 ;
        RECT  24.336 64.716 24.36 64.8 ;
    END
  END i[80]
  PIN i[81]
    DIRECTION INPUT ;
    USE SIGNAL ;
    PORT
      LAYER M5 ;
        RECT  24.432 64.716 24.456 64.8 ;
    END
  END i[81]
  PIN i[82]
    DIRECTION INPUT ;
    USE SIGNAL ;
    PORT
      LAYER M5 ;
        RECT  24.528 64.716 24.552 64.8 ;
    END
  END i[82]
  PIN i[83]
    DIRECTION INPUT ;
    USE SIGNAL ;
    PORT
      LAYER M5 ;
        RECT  24.624 64.716 24.648 64.8 ;
    END
  END i[83]
  PIN i[84]
    DIRECTION INPUT ;
    USE SIGNAL ;
    PORT
      LAYER M5 ;
        RECT  24.72 64.716 24.744 64.8 ;
    END
  END i[84]
  PIN i[85]
    DIRECTION INPUT ;
    USE SIGNAL ;
    PORT
      LAYER M5 ;
        RECT  24.816 64.716 24.84 64.8 ;
    END
  END i[85]
  PIN i[86]
    DIRECTION INPUT ;
    USE SIGNAL ;
    PORT
      LAYER M5 ;
        RECT  24.912 64.716 24.936 64.8 ;
    END
  END i[86]
  PIN i[87]
    DIRECTION INPUT ;
    USE SIGNAL ;
    PORT
      LAYER M5 ;
        RECT  25.008 64.716 25.032 64.8 ;
    END
  END i[87]
  PIN i[88]
    DIRECTION INPUT ;
    USE SIGNAL ;
    PORT
      LAYER M5 ;
        RECT  25.104 64.716 25.128 64.8 ;
    END
  END i[88]
  PIN i[89]
    DIRECTION INPUT ;
    USE SIGNAL ;
    PORT
      LAYER M5 ;
        RECT  25.2 64.716 25.224 64.8 ;
    END
  END i[89]
  PIN i[8]
    DIRECTION INPUT ;
    USE SIGNAL ;
    PORT
      LAYER M3 ;
        RECT  11.628 64.763 11.646 64.8 ;
    END
  END i[8]
  PIN i[90]
    DIRECTION INPUT ;
    USE SIGNAL ;
    PORT
      LAYER M5 ;
        RECT  25.296 64.716 25.32 64.8 ;
    END
  END i[90]
  PIN i[91]
    DIRECTION INPUT ;
    USE SIGNAL ;
    PORT
      LAYER M5 ;
        RECT  25.392 64.716 25.416 64.8 ;
    END
  END i[91]
  PIN i[92]
    DIRECTION INPUT ;
    USE SIGNAL ;
    PORT
      LAYER M5 ;
        RECT  25.488 64.716 25.512 64.8 ;
    END
  END i[92]
  PIN i[93]
    DIRECTION INPUT ;
    USE SIGNAL ;
    PORT
      LAYER M5 ;
        RECT  25.584 64.716 25.608 64.8 ;
    END
  END i[93]
  PIN i[94]
    DIRECTION INPUT ;
    USE SIGNAL ;
    PORT
      LAYER M5 ;
        RECT  25.68 64.716 25.704 64.8 ;
    END
  END i[94]
  PIN i[95]
    DIRECTION INPUT ;
    USE SIGNAL ;
    PORT
      LAYER M5 ;
        RECT  32.688 64.716 32.712 64.8 ;
    END
  END i[95]
  PIN i[96]
    DIRECTION INPUT ;
    USE SIGNAL ;
    PORT
      LAYER M5 ;
        RECT  32.784 64.716 32.808 64.8 ;
    END
  END i[96]
  PIN i[97]
    DIRECTION INPUT ;
    USE SIGNAL ;
    PORT
      LAYER M5 ;
        RECT  32.88 64.716 32.904 64.8 ;
    END
  END i[97]
  PIN i[98]
    DIRECTION INPUT ;
    USE SIGNAL ;
    PORT
      LAYER M5 ;
        RECT  32.976 64.716 33 64.8 ;
    END
  END i[98]
  PIN i[99]
    DIRECTION INPUT ;
    USE SIGNAL ;
    PORT
      LAYER M5 ;
        RECT  33.072 64.716 33.096 64.8 ;
    END
  END i[99]
  PIN i[9]
    DIRECTION INPUT ;
    USE SIGNAL ;
    PORT
      LAYER M3 ;
        RECT  11.7 64.763 11.718 64.8 ;
    END
  END i[9]
  PIN k[0]
    DIRECTION INPUT ;
    USE SIGNAL ;
    PORT
      LAYER M4 ;
        RECT  51.756 38.064 51.84 38.088 ;
    END
  END k[0]
  PIN k[1]
    DIRECTION INPUT ;
    USE SIGNAL ;
    PORT
      LAYER M4 ;
        RECT  51.756 38.16 51.84 38.184 ;
    END
  END k[1]
  PIN k[2]
    DIRECTION INPUT ;
    USE SIGNAL ;
    PORT
      LAYER M4 ;
        RECT  51.756 38.256 51.84 38.28 ;
    END
  END k[2]
  PIN k[3]
    DIRECTION INPUT ;
    USE SIGNAL ;
    PORT
      LAYER M4 ;
        RECT  51.756 38.352 51.84 38.376 ;
    END
  END k[3]
  PIN k[4]
    DIRECTION INPUT ;
    USE SIGNAL ;
    PORT
      LAYER M4 ;
        RECT  51.756 38.448 51.84 38.472 ;
    END
  END k[4]
  PIN k[5]
    DIRECTION INPUT ;
    USE SIGNAL ;
    PORT
      LAYER M4 ;
        RECT  51.756 38.544 51.84 38.568 ;
    END
  END k[5]
  PIN o[0]
    DIRECTION OUTPUT ;
    USE SIGNAL ;
    PORT
      LAYER M5 ;
        RECT  16.272 0 16.296 0.084 ;
    END
  END o[0]
  PIN o[100]
    DIRECTION OUTPUT ;
    USE SIGNAL ;
    PORT
      LAYER M3 ;
        RECT  38.988 0 39.006 0.037 ;
    END
  END o[100]
  PIN o[101]
    DIRECTION OUTPUT ;
    USE SIGNAL ;
    PORT
      LAYER M3 ;
        RECT  39.06 0 39.078 0.037 ;
    END
  END o[101]
  PIN o[102]
    DIRECTION OUTPUT ;
    USE SIGNAL ;
    PORT
      LAYER M3 ;
        RECT  39.132 0 39.15 0.037 ;
    END
  END o[102]
  PIN o[103]
    DIRECTION OUTPUT ;
    USE SIGNAL ;
    PORT
      LAYER M3 ;
        RECT  39.204 0 39.222 0.037 ;
    END
  END o[103]
  PIN o[104]
    DIRECTION OUTPUT ;
    USE SIGNAL ;
    PORT
      LAYER M3 ;
        RECT  39.276 0 39.294 0.037 ;
    END
  END o[104]
  PIN o[105]
    DIRECTION OUTPUT ;
    USE SIGNAL ;
    PORT
      LAYER M3 ;
        RECT  39.348 0 39.366 0.037 ;
    END
  END o[105]
  PIN o[106]
    DIRECTION OUTPUT ;
    USE SIGNAL ;
    PORT
      LAYER M3 ;
        RECT  39.42 0 39.438 0.037 ;
    END
  END o[106]
  PIN o[107]
    DIRECTION OUTPUT ;
    USE SIGNAL ;
    PORT
      LAYER M3 ;
        RECT  39.492 0 39.51 0.037 ;
    END
  END o[107]
  PIN o[108]
    DIRECTION OUTPUT ;
    USE SIGNAL ;
    PORT
      LAYER M3 ;
        RECT  39.564 0 39.582 0.037 ;
    END
  END o[108]
  PIN o[109]
    DIRECTION OUTPUT ;
    USE SIGNAL ;
    PORT
      LAYER M3 ;
        RECT  39.636 0 39.654 0.037 ;
    END
  END o[109]
  PIN o[10]
    DIRECTION OUTPUT ;
    USE SIGNAL ;
    PORT
      LAYER M5 ;
        RECT  17.232 0 17.256 0.084 ;
    END
  END o[10]
  PIN o[110]
    DIRECTION OUTPUT ;
    USE SIGNAL ;
    PORT
      LAYER M3 ;
        RECT  39.708 0 39.726 0.037 ;
    END
  END o[110]
  PIN o[111]
    DIRECTION OUTPUT ;
    USE SIGNAL ;
    PORT
      LAYER M3 ;
        RECT  39.78 0 39.798 0.037 ;
    END
  END o[111]
  PIN o[112]
    DIRECTION OUTPUT ;
    USE SIGNAL ;
    PORT
      LAYER M3 ;
        RECT  39.852 0 39.87 0.037 ;
    END
  END o[112]
  PIN o[113]
    DIRECTION OUTPUT ;
    USE SIGNAL ;
    PORT
      LAYER M3 ;
        RECT  39.924 0 39.942 0.037 ;
    END
  END o[113]
  PIN o[114]
    DIRECTION OUTPUT ;
    USE SIGNAL ;
    PORT
      LAYER M3 ;
        RECT  39.996 0 40.014 0.037 ;
    END
  END o[114]
  PIN o[115]
    DIRECTION OUTPUT ;
    USE SIGNAL ;
    PORT
      LAYER M3 ;
        RECT  40.068 0 40.086 0.037 ;
    END
  END o[115]
  PIN o[116]
    DIRECTION OUTPUT ;
    USE SIGNAL ;
    PORT
      LAYER M3 ;
        RECT  40.14 0 40.158 0.037 ;
    END
  END o[116]
  PIN o[117]
    DIRECTION OUTPUT ;
    USE SIGNAL ;
    PORT
      LAYER M3 ;
        RECT  40.212 0 40.23 0.037 ;
    END
  END o[117]
  PIN o[118]
    DIRECTION OUTPUT ;
    USE SIGNAL ;
    PORT
      LAYER M3 ;
        RECT  40.284 0 40.302 0.037 ;
    END
  END o[118]
  PIN o[119]
    DIRECTION OUTPUT ;
    USE SIGNAL ;
    PORT
      LAYER M3 ;
        RECT  40.356 0 40.374 0.037 ;
    END
  END o[119]
  PIN o[11]
    DIRECTION OUTPUT ;
    USE SIGNAL ;
    PORT
      LAYER M5 ;
        RECT  17.328 0 17.352 0.084 ;
    END
  END o[11]
  PIN o[120]
    DIRECTION OUTPUT ;
    USE SIGNAL ;
    PORT
      LAYER M3 ;
        RECT  40.428 0 40.446 0.037 ;
    END
  END o[120]
  PIN o[121]
    DIRECTION OUTPUT ;
    USE SIGNAL ;
    PORT
      LAYER M3 ;
        RECT  40.5 0 40.518 0.037 ;
    END
  END o[121]
  PIN o[122]
    DIRECTION OUTPUT ;
    USE SIGNAL ;
    PORT
      LAYER M3 ;
        RECT  40.572 0 40.59 0.037 ;
    END
  END o[122]
  PIN o[123]
    DIRECTION OUTPUT ;
    USE SIGNAL ;
    PORT
      LAYER M3 ;
        RECT  40.644 0 40.662 0.037 ;
    END
  END o[123]
  PIN o[124]
    DIRECTION OUTPUT ;
    USE SIGNAL ;
    PORT
      LAYER M3 ;
        RECT  40.716 0 40.734 0.037 ;
    END
  END o[124]
  PIN o[125]
    DIRECTION OUTPUT ;
    USE SIGNAL ;
    PORT
      LAYER M3 ;
        RECT  40.788 0 40.806 0.037 ;
    END
  END o[125]
  PIN o[126]
    DIRECTION OUTPUT ;
    USE SIGNAL ;
    PORT
      LAYER M3 ;
        RECT  46.044 0 46.062 0.037 ;
    END
  END o[126]
  PIN o[127]
    DIRECTION OUTPUT ;
    USE SIGNAL ;
    PORT
      LAYER M3 ;
        RECT  46.116 0 46.134 0.037 ;
    END
  END o[127]
  PIN o[128]
    DIRECTION OUTPUT ;
    USE SIGNAL ;
    PORT
      LAYER M3 ;
        RECT  46.188 0 46.206 0.037 ;
    END
  END o[128]
  PIN o[129]
    DIRECTION OUTPUT ;
    USE SIGNAL ;
    PORT
      LAYER M3 ;
        RECT  46.26 0 46.278 0.037 ;
    END
  END o[129]
  PIN o[12]
    DIRECTION OUTPUT ;
    USE SIGNAL ;
    PORT
      LAYER M5 ;
        RECT  17.424 0 17.448 0.084 ;
    END
  END o[12]
  PIN o[130]
    DIRECTION OUTPUT ;
    USE SIGNAL ;
    PORT
      LAYER M3 ;
        RECT  46.332 0 46.35 0.037 ;
    END
  END o[130]
  PIN o[131]
    DIRECTION OUTPUT ;
    USE SIGNAL ;
    PORT
      LAYER M3 ;
        RECT  46.404 0 46.422 0.037 ;
    END
  END o[131]
  PIN o[132]
    DIRECTION OUTPUT ;
    USE SIGNAL ;
    PORT
      LAYER M3 ;
        RECT  46.476 0 46.494 0.037 ;
    END
  END o[132]
  PIN o[133]
    DIRECTION OUTPUT ;
    USE SIGNAL ;
    PORT
      LAYER M3 ;
        RECT  46.548 0 46.566 0.037 ;
    END
  END o[133]
  PIN o[134]
    DIRECTION OUTPUT ;
    USE SIGNAL ;
    PORT
      LAYER M3 ;
        RECT  46.62 0 46.638 0.037 ;
    END
  END o[134]
  PIN o[135]
    DIRECTION OUTPUT ;
    USE SIGNAL ;
    PORT
      LAYER M3 ;
        RECT  46.692 0 46.71 0.037 ;
    END
  END o[135]
  PIN o[136]
    DIRECTION OUTPUT ;
    USE SIGNAL ;
    PORT
      LAYER M3 ;
        RECT  46.764 0 46.782 0.037 ;
    END
  END o[136]
  PIN o[137]
    DIRECTION OUTPUT ;
    USE SIGNAL ;
    PORT
      LAYER M3 ;
        RECT  46.836 0 46.854 0.037 ;
    END
  END o[137]
  PIN o[138]
    DIRECTION OUTPUT ;
    USE SIGNAL ;
    PORT
      LAYER M3 ;
        RECT  46.908 0 46.926 0.037 ;
    END
  END o[138]
  PIN o[139]
    DIRECTION OUTPUT ;
    USE SIGNAL ;
    PORT
      LAYER M3 ;
        RECT  46.98 0 46.998 0.037 ;
    END
  END o[139]
  PIN o[13]
    DIRECTION OUTPUT ;
    USE SIGNAL ;
    PORT
      LAYER M5 ;
        RECT  17.52 0 17.544 0.084 ;
    END
  END o[13]
  PIN o[140]
    DIRECTION OUTPUT ;
    USE SIGNAL ;
    PORT
      LAYER M3 ;
        RECT  47.052 0 47.07 0.037 ;
    END
  END o[140]
  PIN o[141]
    DIRECTION OUTPUT ;
    USE SIGNAL ;
    PORT
      LAYER M3 ;
        RECT  47.124 0 47.142 0.037 ;
    END
  END o[141]
  PIN o[142]
    DIRECTION OUTPUT ;
    USE SIGNAL ;
    PORT
      LAYER M3 ;
        RECT  47.196 0 47.214 0.037 ;
    END
  END o[142]
  PIN o[143]
    DIRECTION OUTPUT ;
    USE SIGNAL ;
    PORT
      LAYER M3 ;
        RECT  47.268 0 47.286 0.037 ;
    END
  END o[143]
  PIN o[144]
    DIRECTION OUTPUT ;
    USE SIGNAL ;
    PORT
      LAYER M3 ;
        RECT  47.34 0 47.358 0.037 ;
    END
  END o[144]
  PIN o[145]
    DIRECTION OUTPUT ;
    USE SIGNAL ;
    PORT
      LAYER M3 ;
        RECT  47.412 0 47.43 0.037 ;
    END
  END o[145]
  PIN o[146]
    DIRECTION OUTPUT ;
    USE SIGNAL ;
    PORT
      LAYER M3 ;
        RECT  47.484 0 47.502 0.037 ;
    END
  END o[146]
  PIN o[147]
    DIRECTION OUTPUT ;
    USE SIGNAL ;
    PORT
      LAYER M3 ;
        RECT  47.556 0 47.574 0.037 ;
    END
  END o[147]
  PIN o[148]
    DIRECTION OUTPUT ;
    USE SIGNAL ;
    PORT
      LAYER M3 ;
        RECT  47.628 0 47.646 0.037 ;
    END
  END o[148]
  PIN o[149]
    DIRECTION OUTPUT ;
    USE SIGNAL ;
    PORT
      LAYER M3 ;
        RECT  47.7 0 47.718 0.037 ;
    END
  END o[149]
  PIN o[14]
    DIRECTION OUTPUT ;
    USE SIGNAL ;
    PORT
      LAYER M5 ;
        RECT  17.616 0 17.64 0.084 ;
    END
  END o[14]
  PIN o[150]
    DIRECTION OUTPUT ;
    USE SIGNAL ;
    PORT
      LAYER M3 ;
        RECT  47.772 0 47.79 0.037 ;
    END
  END o[150]
  PIN o[151]
    DIRECTION OUTPUT ;
    USE SIGNAL ;
    PORT
      LAYER M3 ;
        RECT  47.844 0 47.862 0.037 ;
    END
  END o[151]
  PIN o[152]
    DIRECTION OUTPUT ;
    USE SIGNAL ;
    PORT
      LAYER M3 ;
        RECT  47.916 0 47.934 0.037 ;
    END
  END o[152]
  PIN o[153]
    DIRECTION OUTPUT ;
    USE SIGNAL ;
    PORT
      LAYER M3 ;
        RECT  47.988 0 48.006 0.037 ;
    END
  END o[153]
  PIN o[154]
    DIRECTION OUTPUT ;
    USE SIGNAL ;
    PORT
      LAYER M3 ;
        RECT  48.06 0 48.078 0.037 ;
    END
  END o[154]
  PIN o[155]
    DIRECTION OUTPUT ;
    USE SIGNAL ;
    PORT
      LAYER M3 ;
        RECT  48.132 0 48.15 0.037 ;
    END
  END o[155]
  PIN o[156]
    DIRECTION OUTPUT ;
    USE SIGNAL ;
    PORT
      LAYER M3 ;
        RECT  48.204 0 48.222 0.037 ;
    END
  END o[156]
  PIN o[157]
    DIRECTION OUTPUT ;
    USE SIGNAL ;
    PORT
      LAYER M3 ;
        RECT  48.276 0 48.294 0.037 ;
    END
  END o[157]
  PIN o[158]
    DIRECTION OUTPUT ;
    USE SIGNAL ;
    PORT
      LAYER M5 ;
        RECT  45.264 0 45.288 0.084 ;
    END
  END o[158]
  PIN o[159]
    DIRECTION OUTPUT ;
    USE SIGNAL ;
    PORT
      LAYER M5 ;
        RECT  45.36 0 45.384 0.084 ;
    END
  END o[159]
  PIN o[15]
    DIRECTION OUTPUT ;
    USE SIGNAL ;
    PORT
      LAYER M5 ;
        RECT  17.712 0 17.736 0.084 ;
    END
  END o[15]
  PIN o[160]
    DIRECTION OUTPUT ;
    USE SIGNAL ;
    PORT
      LAYER M5 ;
        RECT  45.456 0 45.48 0.084 ;
    END
  END o[160]
  PIN o[161]
    DIRECTION OUTPUT ;
    USE SIGNAL ;
    PORT
      LAYER M5 ;
        RECT  45.552 0 45.576 0.084 ;
    END
  END o[161]
  PIN o[162]
    DIRECTION OUTPUT ;
    USE SIGNAL ;
    PORT
      LAYER M5 ;
        RECT  45.648 0 45.672 0.084 ;
    END
  END o[162]
  PIN o[163]
    DIRECTION OUTPUT ;
    USE SIGNAL ;
    PORT
      LAYER M5 ;
        RECT  45.744 0 45.768 0.084 ;
    END
  END o[163]
  PIN o[164]
    DIRECTION OUTPUT ;
    USE SIGNAL ;
    PORT
      LAYER M5 ;
        RECT  45.84 0 45.864 0.084 ;
    END
  END o[164]
  PIN o[165]
    DIRECTION OUTPUT ;
    USE SIGNAL ;
    PORT
      LAYER M5 ;
        RECT  45.936 0 45.96 0.084 ;
    END
  END o[165]
  PIN o[166]
    DIRECTION OUTPUT ;
    USE SIGNAL ;
    PORT
      LAYER M5 ;
        RECT  46.032 0 46.056 0.084 ;
    END
  END o[166]
  PIN o[167]
    DIRECTION OUTPUT ;
    USE SIGNAL ;
    PORT
      LAYER M5 ;
        RECT  46.128 0 46.152 0.084 ;
    END
  END o[167]
  PIN o[168]
    DIRECTION OUTPUT ;
    USE SIGNAL ;
    PORT
      LAYER M5 ;
        RECT  46.224 0 46.248 0.084 ;
    END
  END o[168]
  PIN o[169]
    DIRECTION OUTPUT ;
    USE SIGNAL ;
    PORT
      LAYER M5 ;
        RECT  46.32 0 46.344 0.084 ;
    END
  END o[169]
  PIN o[16]
    DIRECTION OUTPUT ;
    USE SIGNAL ;
    PORT
      LAYER M5 ;
        RECT  17.808 0 17.832 0.084 ;
    END
  END o[16]
  PIN o[170]
    DIRECTION OUTPUT ;
    USE SIGNAL ;
    PORT
      LAYER M5 ;
        RECT  46.416 0 46.44 0.084 ;
    END
  END o[170]
  PIN o[171]
    DIRECTION OUTPUT ;
    USE SIGNAL ;
    PORT
      LAYER M5 ;
        RECT  46.512 0 46.536 0.084 ;
    END
  END o[171]
  PIN o[172]
    DIRECTION OUTPUT ;
    USE SIGNAL ;
    PORT
      LAYER M5 ;
        RECT  46.608 0 46.632 0.084 ;
    END
  END o[172]
  PIN o[173]
    DIRECTION OUTPUT ;
    USE SIGNAL ;
    PORT
      LAYER M5 ;
        RECT  46.704 0 46.728 0.084 ;
    END
  END o[173]
  PIN o[174]
    DIRECTION OUTPUT ;
    USE SIGNAL ;
    PORT
      LAYER M5 ;
        RECT  46.8 0 46.824 0.084 ;
    END
  END o[174]
  PIN o[175]
    DIRECTION OUTPUT ;
    USE SIGNAL ;
    PORT
      LAYER M5 ;
        RECT  46.896 0 46.92 0.084 ;
    END
  END o[175]
  PIN o[176]
    DIRECTION OUTPUT ;
    USE SIGNAL ;
    PORT
      LAYER M5 ;
        RECT  46.992 0 47.016 0.084 ;
    END
  END o[176]
  PIN o[177]
    DIRECTION OUTPUT ;
    USE SIGNAL ;
    PORT
      LAYER M5 ;
        RECT  47.088 0 47.112 0.084 ;
    END
  END o[177]
  PIN o[178]
    DIRECTION OUTPUT ;
    USE SIGNAL ;
    PORT
      LAYER M5 ;
        RECT  47.184 0 47.208 0.084 ;
    END
  END o[178]
  PIN o[179]
    DIRECTION OUTPUT ;
    USE SIGNAL ;
    PORT
      LAYER M5 ;
        RECT  47.28 0 47.304 0.084 ;
    END
  END o[179]
  PIN o[17]
    DIRECTION OUTPUT ;
    USE SIGNAL ;
    PORT
      LAYER M5 ;
        RECT  17.904 0 17.928 0.084 ;
    END
  END o[17]
  PIN o[180]
    DIRECTION OUTPUT ;
    USE SIGNAL ;
    PORT
      LAYER M5 ;
        RECT  47.376 0 47.4 0.084 ;
    END
  END o[180]
  PIN o[181]
    DIRECTION OUTPUT ;
    USE SIGNAL ;
    PORT
      LAYER M5 ;
        RECT  47.472 0 47.496 0.084 ;
    END
  END o[181]
  PIN o[182]
    DIRECTION OUTPUT ;
    USE SIGNAL ;
    PORT
      LAYER M5 ;
        RECT  47.568 0 47.592 0.084 ;
    END
  END o[182]
  PIN o[183]
    DIRECTION OUTPUT ;
    USE SIGNAL ;
    PORT
      LAYER M5 ;
        RECT  47.664 0 47.688 0.084 ;
    END
  END o[183]
  PIN o[184]
    DIRECTION OUTPUT ;
    USE SIGNAL ;
    PORT
      LAYER M5 ;
        RECT  47.76 0 47.784 0.084 ;
    END
  END o[184]
  PIN o[185]
    DIRECTION OUTPUT ;
    USE SIGNAL ;
    PORT
      LAYER M5 ;
        RECT  47.856 0 47.88 0.084 ;
    END
  END o[185]
  PIN o[186]
    DIRECTION OUTPUT ;
    USE SIGNAL ;
    PORT
      LAYER M5 ;
        RECT  47.952 0 47.976 0.084 ;
    END
  END o[186]
  PIN o[187]
    DIRECTION OUTPUT ;
    USE SIGNAL ;
    PORT
      LAYER M5 ;
        RECT  48.048 0 48.072 0.084 ;
    END
  END o[187]
  PIN o[188]
    DIRECTION OUTPUT ;
    USE SIGNAL ;
    PORT
      LAYER M5 ;
        RECT  48.144 0 48.168 0.084 ;
    END
  END o[188]
  PIN o[189]
    DIRECTION OUTPUT ;
    USE SIGNAL ;
    PORT
      LAYER M5 ;
        RECT  48.24 0 48.264 0.084 ;
    END
  END o[189]
  PIN o[18]
    DIRECTION OUTPUT ;
    USE SIGNAL ;
    PORT
      LAYER M5 ;
        RECT  18 0 18.024 0.084 ;
    END
  END o[18]
  PIN o[190]
    DIRECTION OUTPUT ;
    USE SIGNAL ;
    PORT
      LAYER M3 ;
        RECT  33.948 0 33.966 0.037 ;
    END
  END o[190]
  PIN o[191]
    DIRECTION OUTPUT ;
    USE SIGNAL ;
    PORT
      LAYER M3 ;
        RECT  34.02 0 34.038 0.037 ;
    END
  END o[191]
  PIN o[192]
    DIRECTION OUTPUT ;
    USE SIGNAL ;
    PORT
      LAYER M3 ;
        RECT  34.092 0 34.11 0.037 ;
    END
  END o[192]
  PIN o[193]
    DIRECTION OUTPUT ;
    USE SIGNAL ;
    PORT
      LAYER M3 ;
        RECT  34.164 0 34.182 0.037 ;
    END
  END o[193]
  PIN o[194]
    DIRECTION OUTPUT ;
    USE SIGNAL ;
    PORT
      LAYER M3 ;
        RECT  34.236 0 34.254 0.037 ;
    END
  END o[194]
  PIN o[195]
    DIRECTION OUTPUT ;
    USE SIGNAL ;
    PORT
      LAYER M3 ;
        RECT  34.308 0 34.326 0.037 ;
    END
  END o[195]
  PIN o[196]
    DIRECTION OUTPUT ;
    USE SIGNAL ;
    PORT
      LAYER M3 ;
        RECT  34.38 0 34.398 0.037 ;
    END
  END o[196]
  PIN o[197]
    DIRECTION OUTPUT ;
    USE SIGNAL ;
    PORT
      LAYER M3 ;
        RECT  34.452 0 34.47 0.037 ;
    END
  END o[197]
  PIN o[198]
    DIRECTION OUTPUT ;
    USE SIGNAL ;
    PORT
      LAYER M3 ;
        RECT  34.524 0 34.542 0.037 ;
    END
  END o[198]
  PIN o[199]
    DIRECTION OUTPUT ;
    USE SIGNAL ;
    PORT
      LAYER M3 ;
        RECT  34.596 0 34.614 0.037 ;
    END
  END o[199]
  PIN o[19]
    DIRECTION OUTPUT ;
    USE SIGNAL ;
    PORT
      LAYER M5 ;
        RECT  18.096 0 18.12 0.084 ;
    END
  END o[19]
  PIN o[1]
    DIRECTION OUTPUT ;
    USE SIGNAL ;
    PORT
      LAYER M5 ;
        RECT  16.368 0 16.392 0.084 ;
    END
  END o[1]
  PIN o[200]
    DIRECTION OUTPUT ;
    USE SIGNAL ;
    PORT
      LAYER M3 ;
        RECT  34.668 0 34.686 0.037 ;
    END
  END o[200]
  PIN o[201]
    DIRECTION OUTPUT ;
    USE SIGNAL ;
    PORT
      LAYER M3 ;
        RECT  34.74 0 34.758 0.037 ;
    END
  END o[201]
  PIN o[202]
    DIRECTION OUTPUT ;
    USE SIGNAL ;
    PORT
      LAYER M3 ;
        RECT  34.812 0 34.83 0.037 ;
    END
  END o[202]
  PIN o[203]
    DIRECTION OUTPUT ;
    USE SIGNAL ;
    PORT
      LAYER M3 ;
        RECT  34.884 0 34.902 0.037 ;
    END
  END o[203]
  PIN o[204]
    DIRECTION OUTPUT ;
    USE SIGNAL ;
    PORT
      LAYER M3 ;
        RECT  34.956 0 34.974 0.037 ;
    END
  END o[204]
  PIN o[205]
    DIRECTION OUTPUT ;
    USE SIGNAL ;
    PORT
      LAYER M3 ;
        RECT  35.028 0 35.046 0.037 ;
    END
  END o[205]
  PIN o[206]
    DIRECTION OUTPUT ;
    USE SIGNAL ;
    PORT
      LAYER M3 ;
        RECT  35.1 0 35.118 0.037 ;
    END
  END o[206]
  PIN o[207]
    DIRECTION OUTPUT ;
    USE SIGNAL ;
    PORT
      LAYER M3 ;
        RECT  35.172 0 35.19 0.037 ;
    END
  END o[207]
  PIN o[208]
    DIRECTION OUTPUT ;
    USE SIGNAL ;
    PORT
      LAYER M3 ;
        RECT  35.244 0 35.262 0.037 ;
    END
  END o[208]
  PIN o[209]
    DIRECTION OUTPUT ;
    USE SIGNAL ;
    PORT
      LAYER M3 ;
        RECT  35.316 0 35.334 0.037 ;
    END
  END o[209]
  PIN o[20]
    DIRECTION OUTPUT ;
    USE SIGNAL ;
    PORT
      LAYER M5 ;
        RECT  18.192 0 18.216 0.084 ;
    END
  END o[20]
  PIN o[210]
    DIRECTION OUTPUT ;
    USE SIGNAL ;
    PORT
      LAYER M3 ;
        RECT  35.388 0 35.406 0.037 ;
    END
  END o[210]
  PIN o[211]
    DIRECTION OUTPUT ;
    USE SIGNAL ;
    PORT
      LAYER M3 ;
        RECT  35.46 0 35.478 0.037 ;
    END
  END o[211]
  PIN o[212]
    DIRECTION OUTPUT ;
    USE SIGNAL ;
    PORT
      LAYER M3 ;
        RECT  35.532 0 35.55 0.037 ;
    END
  END o[212]
  PIN o[213]
    DIRECTION OUTPUT ;
    USE SIGNAL ;
    PORT
      LAYER M3 ;
        RECT  35.604 0 35.622 0.037 ;
    END
  END o[213]
  PIN o[214]
    DIRECTION OUTPUT ;
    USE SIGNAL ;
    PORT
      LAYER M3 ;
        RECT  35.676 0 35.694 0.037 ;
    END
  END o[214]
  PIN o[215]
    DIRECTION OUTPUT ;
    USE SIGNAL ;
    PORT
      LAYER M3 ;
        RECT  35.748 0 35.766 0.037 ;
    END
  END o[215]
  PIN o[216]
    DIRECTION OUTPUT ;
    USE SIGNAL ;
    PORT
      LAYER M3 ;
        RECT  35.82 0 35.838 0.037 ;
    END
  END o[216]
  PIN o[217]
    DIRECTION OUTPUT ;
    USE SIGNAL ;
    PORT
      LAYER M3 ;
        RECT  35.892 0 35.91 0.037 ;
    END
  END o[217]
  PIN o[218]
    DIRECTION OUTPUT ;
    USE SIGNAL ;
    PORT
      LAYER M3 ;
        RECT  35.964 0 35.982 0.037 ;
    END
  END o[218]
  PIN o[219]
    DIRECTION OUTPUT ;
    USE SIGNAL ;
    PORT
      LAYER M3 ;
        RECT  36.036 0 36.054 0.037 ;
    END
  END o[219]
  PIN o[21]
    DIRECTION OUTPUT ;
    USE SIGNAL ;
    PORT
      LAYER M5 ;
        RECT  18.288 0 18.312 0.084 ;
    END
  END o[21]
  PIN o[220]
    DIRECTION OUTPUT ;
    USE SIGNAL ;
    PORT
      LAYER M3 ;
        RECT  36.108 0 36.126 0.037 ;
    END
  END o[220]
  PIN o[221]
    DIRECTION OUTPUT ;
    USE SIGNAL ;
    PORT
      LAYER M3 ;
        RECT  36.18 0 36.198 0.037 ;
    END
  END o[221]
  PIN o[222]
    DIRECTION OUTPUT ;
    USE SIGNAL ;
    PORT
      LAYER M3 ;
        RECT  17.244 0 17.262 0.037 ;
    END
  END o[222]
  PIN o[223]
    DIRECTION OUTPUT ;
    USE SIGNAL ;
    PORT
      LAYER M3 ;
        RECT  17.316 0 17.334 0.037 ;
    END
  END o[223]
  PIN o[224]
    DIRECTION OUTPUT ;
    USE SIGNAL ;
    PORT
      LAYER M3 ;
        RECT  17.388 0 17.406 0.037 ;
    END
  END o[224]
  PIN o[225]
    DIRECTION OUTPUT ;
    USE SIGNAL ;
    PORT
      LAYER M3 ;
        RECT  17.46 0 17.478 0.037 ;
    END
  END o[225]
  PIN o[226]
    DIRECTION OUTPUT ;
    USE SIGNAL ;
    PORT
      LAYER M3 ;
        RECT  17.532 0 17.55 0.037 ;
    END
  END o[226]
  PIN o[227]
    DIRECTION OUTPUT ;
    USE SIGNAL ;
    PORT
      LAYER M3 ;
        RECT  17.604 0 17.622 0.037 ;
    END
  END o[227]
  PIN o[228]
    DIRECTION OUTPUT ;
    USE SIGNAL ;
    PORT
      LAYER M3 ;
        RECT  17.676 0 17.694 0.037 ;
    END
  END o[228]
  PIN o[229]
    DIRECTION OUTPUT ;
    USE SIGNAL ;
    PORT
      LAYER M3 ;
        RECT  17.748 0 17.766 0.037 ;
    END
  END o[229]
  PIN o[22]
    DIRECTION OUTPUT ;
    USE SIGNAL ;
    PORT
      LAYER M5 ;
        RECT  18.384 0 18.408 0.084 ;
    END
  END o[22]
  PIN o[230]
    DIRECTION OUTPUT ;
    USE SIGNAL ;
    PORT
      LAYER M3 ;
        RECT  17.82 0 17.838 0.037 ;
    END
  END o[230]
  PIN o[231]
    DIRECTION OUTPUT ;
    USE SIGNAL ;
    PORT
      LAYER M3 ;
        RECT  17.892 0 17.91 0.037 ;
    END
  END o[231]
  PIN o[232]
    DIRECTION OUTPUT ;
    USE SIGNAL ;
    PORT
      LAYER M3 ;
        RECT  17.964 0 17.982 0.037 ;
    END
  END o[232]
  PIN o[233]
    DIRECTION OUTPUT ;
    USE SIGNAL ;
    PORT
      LAYER M3 ;
        RECT  18.036 0 18.054 0.037 ;
    END
  END o[233]
  PIN o[234]
    DIRECTION OUTPUT ;
    USE SIGNAL ;
    PORT
      LAYER M3 ;
        RECT  18.108 0 18.126 0.037 ;
    END
  END o[234]
  PIN o[235]
    DIRECTION OUTPUT ;
    USE SIGNAL ;
    PORT
      LAYER M3 ;
        RECT  18.18 0 18.198 0.037 ;
    END
  END o[235]
  PIN o[236]
    DIRECTION OUTPUT ;
    USE SIGNAL ;
    PORT
      LAYER M3 ;
        RECT  18.252 0 18.27 0.037 ;
    END
  END o[236]
  PIN o[237]
    DIRECTION OUTPUT ;
    USE SIGNAL ;
    PORT
      LAYER M3 ;
        RECT  18.324 0 18.342 0.037 ;
    END
  END o[237]
  PIN o[238]
    DIRECTION OUTPUT ;
    USE SIGNAL ;
    PORT
      LAYER M3 ;
        RECT  18.396 0 18.414 0.037 ;
    END
  END o[238]
  PIN o[239]
    DIRECTION OUTPUT ;
    USE SIGNAL ;
    PORT
      LAYER M3 ;
        RECT  18.468 0 18.486 0.037 ;
    END
  END o[239]
  PIN o[23]
    DIRECTION OUTPUT ;
    USE SIGNAL ;
    PORT
      LAYER M5 ;
        RECT  18.48 0 18.504 0.084 ;
    END
  END o[23]
  PIN o[240]
    DIRECTION OUTPUT ;
    USE SIGNAL ;
    PORT
      LAYER M3 ;
        RECT  18.54 0 18.558 0.037 ;
    END
  END o[240]
  PIN o[241]
    DIRECTION OUTPUT ;
    USE SIGNAL ;
    PORT
      LAYER M3 ;
        RECT  18.612 0 18.63 0.037 ;
    END
  END o[241]
  PIN o[242]
    DIRECTION OUTPUT ;
    USE SIGNAL ;
    PORT
      LAYER M3 ;
        RECT  18.684 0 18.702 0.037 ;
    END
  END o[242]
  PIN o[243]
    DIRECTION OUTPUT ;
    USE SIGNAL ;
    PORT
      LAYER M3 ;
        RECT  18.756 0 18.774 0.037 ;
    END
  END o[243]
  PIN o[244]
    DIRECTION OUTPUT ;
    USE SIGNAL ;
    PORT
      LAYER M3 ;
        RECT  18.828 0 18.846 0.037 ;
    END
  END o[244]
  PIN o[245]
    DIRECTION OUTPUT ;
    USE SIGNAL ;
    PORT
      LAYER M3 ;
        RECT  18.9 0 18.918 0.037 ;
    END
  END o[245]
  PIN o[246]
    DIRECTION OUTPUT ;
    USE SIGNAL ;
    PORT
      LAYER M3 ;
        RECT  18.972 0 18.99 0.037 ;
    END
  END o[246]
  PIN o[247]
    DIRECTION OUTPUT ;
    USE SIGNAL ;
    PORT
      LAYER M3 ;
        RECT  19.044 0 19.062 0.037 ;
    END
  END o[247]
  PIN o[248]
    DIRECTION OUTPUT ;
    USE SIGNAL ;
    PORT
      LAYER M3 ;
        RECT  19.116 0 19.134 0.037 ;
    END
  END o[248]
  PIN o[249]
    DIRECTION OUTPUT ;
    USE SIGNAL ;
    PORT
      LAYER M3 ;
        RECT  19.188 0 19.206 0.037 ;
    END
  END o[249]
  PIN o[24]
    DIRECTION OUTPUT ;
    USE SIGNAL ;
    PORT
      LAYER M5 ;
        RECT  18.576 0 18.6 0.084 ;
    END
  END o[24]
  PIN o[250]
    DIRECTION OUTPUT ;
    USE SIGNAL ;
    PORT
      LAYER M3 ;
        RECT  19.26 0 19.278 0.037 ;
    END
  END o[250]
  PIN o[251]
    DIRECTION OUTPUT ;
    USE SIGNAL ;
    PORT
      LAYER M3 ;
        RECT  19.332 0 19.35 0.037 ;
    END
  END o[251]
  PIN o[252]
    DIRECTION OUTPUT ;
    USE SIGNAL ;
    PORT
      LAYER M3 ;
        RECT  19.404 0 19.422 0.037 ;
    END
  END o[252]
  PIN o[253]
    DIRECTION OUTPUT ;
    USE SIGNAL ;
    PORT
      LAYER M3 ;
        RECT  19.476 0 19.494 0.037 ;
    END
  END o[253]
  PIN o[254]
    DIRECTION OUTPUT ;
    USE SIGNAL ;
    PORT
      LAYER M5 ;
        RECT  9.936 0 9.96 0.084 ;
    END
  END o[254]
  PIN o[255]
    DIRECTION OUTPUT ;
    USE SIGNAL ;
    PORT
      LAYER M5 ;
        RECT  10.032 0 10.056 0.084 ;
    END
  END o[255]
  PIN o[256]
    DIRECTION OUTPUT ;
    USE SIGNAL ;
    PORT
      LAYER M5 ;
        RECT  10.128 0 10.152 0.084 ;
    END
  END o[256]
  PIN o[257]
    DIRECTION OUTPUT ;
    USE SIGNAL ;
    PORT
      LAYER M5 ;
        RECT  10.224 0 10.248 0.084 ;
    END
  END o[257]
  PIN o[258]
    DIRECTION OUTPUT ;
    USE SIGNAL ;
    PORT
      LAYER M5 ;
        RECT  10.32 0 10.344 0.084 ;
    END
  END o[258]
  PIN o[259]
    DIRECTION OUTPUT ;
    USE SIGNAL ;
    PORT
      LAYER M5 ;
        RECT  10.416 0 10.44 0.084 ;
    END
  END o[259]
  PIN o[25]
    DIRECTION OUTPUT ;
    USE SIGNAL ;
    PORT
      LAYER M5 ;
        RECT  18.672 0 18.696 0.084 ;
    END
  END o[25]
  PIN o[260]
    DIRECTION OUTPUT ;
    USE SIGNAL ;
    PORT
      LAYER M5 ;
        RECT  10.512 0 10.536 0.084 ;
    END
  END o[260]
  PIN o[261]
    DIRECTION OUTPUT ;
    USE SIGNAL ;
    PORT
      LAYER M5 ;
        RECT  10.608 0 10.632 0.084 ;
    END
  END o[261]
  PIN o[262]
    DIRECTION OUTPUT ;
    USE SIGNAL ;
    PORT
      LAYER M5 ;
        RECT  10.704 0 10.728 0.084 ;
    END
  END o[262]
  PIN o[263]
    DIRECTION OUTPUT ;
    USE SIGNAL ;
    PORT
      LAYER M5 ;
        RECT  10.8 0 10.824 0.084 ;
    END
  END o[263]
  PIN o[264]
    DIRECTION OUTPUT ;
    USE SIGNAL ;
    PORT
      LAYER M5 ;
        RECT  10.896 0 10.92 0.084 ;
    END
  END o[264]
  PIN o[265]
    DIRECTION OUTPUT ;
    USE SIGNAL ;
    PORT
      LAYER M5 ;
        RECT  10.992 0 11.016 0.084 ;
    END
  END o[265]
  PIN o[266]
    DIRECTION OUTPUT ;
    USE SIGNAL ;
    PORT
      LAYER M5 ;
        RECT  11.088 0 11.112 0.084 ;
    END
  END o[266]
  PIN o[267]
    DIRECTION OUTPUT ;
    USE SIGNAL ;
    PORT
      LAYER M5 ;
        RECT  11.184 0 11.208 0.084 ;
    END
  END o[267]
  PIN o[268]
    DIRECTION OUTPUT ;
    USE SIGNAL ;
    PORT
      LAYER M5 ;
        RECT  11.28 0 11.304 0.084 ;
    END
  END o[268]
  PIN o[269]
    DIRECTION OUTPUT ;
    USE SIGNAL ;
    PORT
      LAYER M5 ;
        RECT  11.376 0 11.4 0.084 ;
    END
  END o[269]
  PIN o[26]
    DIRECTION OUTPUT ;
    USE SIGNAL ;
    PORT
      LAYER M5 ;
        RECT  18.768 0 18.792 0.084 ;
    END
  END o[26]
  PIN o[270]
    DIRECTION OUTPUT ;
    USE SIGNAL ;
    PORT
      LAYER M5 ;
        RECT  11.472 0 11.496 0.084 ;
    END
  END o[270]
  PIN o[271]
    DIRECTION OUTPUT ;
    USE SIGNAL ;
    PORT
      LAYER M5 ;
        RECT  11.568 0 11.592 0.084 ;
    END
  END o[271]
  PIN o[272]
    DIRECTION OUTPUT ;
    USE SIGNAL ;
    PORT
      LAYER M5 ;
        RECT  11.664 0 11.688 0.084 ;
    END
  END o[272]
  PIN o[273]
    DIRECTION OUTPUT ;
    USE SIGNAL ;
    PORT
      LAYER M5 ;
        RECT  11.76 0 11.784 0.084 ;
    END
  END o[273]
  PIN o[274]
    DIRECTION OUTPUT ;
    USE SIGNAL ;
    PORT
      LAYER M5 ;
        RECT  11.856 0 11.88 0.084 ;
    END
  END o[274]
  PIN o[275]
    DIRECTION OUTPUT ;
    USE SIGNAL ;
    PORT
      LAYER M5 ;
        RECT  11.952 0 11.976 0.084 ;
    END
  END o[275]
  PIN o[27]
    DIRECTION OUTPUT ;
    USE SIGNAL ;
    PORT
      LAYER M5 ;
        RECT  18.864 0 18.888 0.084 ;
    END
  END o[27]
  PIN o[28]
    DIRECTION OUTPUT ;
    USE SIGNAL ;
    PORT
      LAYER M5 ;
        RECT  18.96 0 18.984 0.084 ;
    END
  END o[28]
  PIN o[29]
    DIRECTION OUTPUT ;
    USE SIGNAL ;
    PORT
      LAYER M5 ;
        RECT  19.056 0 19.08 0.084 ;
    END
  END o[29]
  PIN o[2]
    DIRECTION OUTPUT ;
    USE SIGNAL ;
    PORT
      LAYER M5 ;
        RECT  16.464 0 16.488 0.084 ;
    END
  END o[2]
  PIN o[30]
    DIRECTION OUTPUT ;
    USE SIGNAL ;
    PORT
      LAYER M5 ;
        RECT  13.008 0 13.032 0.084 ;
    END
  END o[30]
  PIN o[31]
    DIRECTION OUTPUT ;
    USE SIGNAL ;
    PORT
      LAYER M5 ;
        RECT  13.104 0 13.128 0.084 ;
    END
  END o[31]
  PIN o[32]
    DIRECTION OUTPUT ;
    USE SIGNAL ;
    PORT
      LAYER M5 ;
        RECT  13.2 0 13.224 0.084 ;
    END
  END o[32]
  PIN o[33]
    DIRECTION OUTPUT ;
    USE SIGNAL ;
    PORT
      LAYER M5 ;
        RECT  13.296 0 13.32 0.084 ;
    END
  END o[33]
  PIN o[34]
    DIRECTION OUTPUT ;
    USE SIGNAL ;
    PORT
      LAYER M5 ;
        RECT  13.392 0 13.416 0.084 ;
    END
  END o[34]
  PIN o[35]
    DIRECTION OUTPUT ;
    USE SIGNAL ;
    PORT
      LAYER M5 ;
        RECT  13.488 0 13.512 0.084 ;
    END
  END o[35]
  PIN o[36]
    DIRECTION OUTPUT ;
    USE SIGNAL ;
    PORT
      LAYER M5 ;
        RECT  13.584 0 13.608 0.084 ;
    END
  END o[36]
  PIN o[37]
    DIRECTION OUTPUT ;
    USE SIGNAL ;
    PORT
      LAYER M5 ;
        RECT  13.68 0 13.704 0.084 ;
    END
  END o[37]
  PIN o[38]
    DIRECTION OUTPUT ;
    USE SIGNAL ;
    PORT
      LAYER M5 ;
        RECT  13.776 0 13.8 0.084 ;
    END
  END o[38]
  PIN o[39]
    DIRECTION OUTPUT ;
    USE SIGNAL ;
    PORT
      LAYER M5 ;
        RECT  13.872 0 13.896 0.084 ;
    END
  END o[39]
  PIN o[3]
    DIRECTION OUTPUT ;
    USE SIGNAL ;
    PORT
      LAYER M5 ;
        RECT  16.56 0 16.584 0.084 ;
    END
  END o[3]
  PIN o[40]
    DIRECTION OUTPUT ;
    USE SIGNAL ;
    PORT
      LAYER M5 ;
        RECT  13.968 0 13.992 0.084 ;
    END
  END o[40]
  PIN o[41]
    DIRECTION OUTPUT ;
    USE SIGNAL ;
    PORT
      LAYER M5 ;
        RECT  14.064 0 14.088 0.084 ;
    END
  END o[41]
  PIN o[42]
    DIRECTION OUTPUT ;
    USE SIGNAL ;
    PORT
      LAYER M5 ;
        RECT  14.16 0 14.184 0.084 ;
    END
  END o[42]
  PIN o[43]
    DIRECTION OUTPUT ;
    USE SIGNAL ;
    PORT
      LAYER M5 ;
        RECT  14.256 0 14.28 0.084 ;
    END
  END o[43]
  PIN o[44]
    DIRECTION OUTPUT ;
    USE SIGNAL ;
    PORT
      LAYER M5 ;
        RECT  14.352 0 14.376 0.084 ;
    END
  END o[44]
  PIN o[45]
    DIRECTION OUTPUT ;
    USE SIGNAL ;
    PORT
      LAYER M5 ;
        RECT  14.448 0 14.472 0.084 ;
    END
  END o[45]
  PIN o[46]
    DIRECTION OUTPUT ;
    USE SIGNAL ;
    PORT
      LAYER M5 ;
        RECT  14.544 0 14.568 0.084 ;
    END
  END o[46]
  PIN o[47]
    DIRECTION OUTPUT ;
    USE SIGNAL ;
    PORT
      LAYER M5 ;
        RECT  14.64 0 14.664 0.084 ;
    END
  END o[47]
  PIN o[48]
    DIRECTION OUTPUT ;
    USE SIGNAL ;
    PORT
      LAYER M5 ;
        RECT  14.736 0 14.76 0.084 ;
    END
  END o[48]
  PIN o[49]
    DIRECTION OUTPUT ;
    USE SIGNAL ;
    PORT
      LAYER M5 ;
        RECT  14.832 0 14.856 0.084 ;
    END
  END o[49]
  PIN o[4]
    DIRECTION OUTPUT ;
    USE SIGNAL ;
    PORT
      LAYER M5 ;
        RECT  16.656 0 16.68 0.084 ;
    END
  END o[4]
  PIN o[50]
    DIRECTION OUTPUT ;
    USE SIGNAL ;
    PORT
      LAYER M5 ;
        RECT  14.928 0 14.952 0.084 ;
    END
  END o[50]
  PIN o[51]
    DIRECTION OUTPUT ;
    USE SIGNAL ;
    PORT
      LAYER M5 ;
        RECT  15.024 0 15.048 0.084 ;
    END
  END o[51]
  PIN o[52]
    DIRECTION OUTPUT ;
    USE SIGNAL ;
    PORT
      LAYER M5 ;
        RECT  15.12 0 15.144 0.084 ;
    END
  END o[52]
  PIN o[53]
    DIRECTION OUTPUT ;
    USE SIGNAL ;
    PORT
      LAYER M5 ;
        RECT  15.216 0 15.24 0.084 ;
    END
  END o[53]
  PIN o[54]
    DIRECTION OUTPUT ;
    USE SIGNAL ;
    PORT
      LAYER M5 ;
        RECT  15.312 0 15.336 0.084 ;
    END
  END o[54]
  PIN o[55]
    DIRECTION OUTPUT ;
    USE SIGNAL ;
    PORT
      LAYER M5 ;
        RECT  15.408 0 15.432 0.084 ;
    END
  END o[55]
  PIN o[56]
    DIRECTION OUTPUT ;
    USE SIGNAL ;
    PORT
      LAYER M5 ;
        RECT  15.504 0 15.528 0.084 ;
    END
  END o[56]
  PIN o[57]
    DIRECTION OUTPUT ;
    USE SIGNAL ;
    PORT
      LAYER M5 ;
        RECT  15.6 0 15.624 0.084 ;
    END
  END o[57]
  PIN o[58]
    DIRECTION OUTPUT ;
    USE SIGNAL ;
    PORT
      LAYER M5 ;
        RECT  15.696 0 15.72 0.084 ;
    END
  END o[58]
  PIN o[59]
    DIRECTION OUTPUT ;
    USE SIGNAL ;
    PORT
      LAYER M5 ;
        RECT  15.792 0 15.816 0.084 ;
    END
  END o[59]
  PIN o[5]
    DIRECTION OUTPUT ;
    USE SIGNAL ;
    PORT
      LAYER M5 ;
        RECT  16.752 0 16.776 0.084 ;
    END
  END o[5]
  PIN o[60]
    DIRECTION OUTPUT ;
    USE SIGNAL ;
    PORT
      LAYER M5 ;
        RECT  15.888 0 15.912 0.084 ;
    END
  END o[60]
  PIN o[61]
    DIRECTION OUTPUT ;
    USE SIGNAL ;
    PORT
      LAYER M5 ;
        RECT  15.984 0 16.008 0.084 ;
    END
  END o[61]
  PIN o[62]
    DIRECTION OUTPUT ;
    USE SIGNAL ;
    PORT
      LAYER M5 ;
        RECT  29.136 0 29.16 0.084 ;
    END
  END o[62]
  PIN o[63]
    DIRECTION OUTPUT ;
    USE SIGNAL ;
    PORT
      LAYER M5 ;
        RECT  29.232 0 29.256 0.084 ;
    END
  END o[63]
  PIN o[64]
    DIRECTION OUTPUT ;
    USE SIGNAL ;
    PORT
      LAYER M5 ;
        RECT  29.328 0 29.352 0.084 ;
    END
  END o[64]
  PIN o[65]
    DIRECTION OUTPUT ;
    USE SIGNAL ;
    PORT
      LAYER M5 ;
        RECT  29.424 0 29.448 0.084 ;
    END
  END o[65]
  PIN o[66]
    DIRECTION OUTPUT ;
    USE SIGNAL ;
    PORT
      LAYER M5 ;
        RECT  29.52 0 29.544 0.084 ;
    END
  END o[66]
  PIN o[67]
    DIRECTION OUTPUT ;
    USE SIGNAL ;
    PORT
      LAYER M5 ;
        RECT  29.616 0 29.64 0.084 ;
    END
  END o[67]
  PIN o[68]
    DIRECTION OUTPUT ;
    USE SIGNAL ;
    PORT
      LAYER M5 ;
        RECT  29.712 0 29.736 0.084 ;
    END
  END o[68]
  PIN o[69]
    DIRECTION OUTPUT ;
    USE SIGNAL ;
    PORT
      LAYER M5 ;
        RECT  29.808 0 29.832 0.084 ;
    END
  END o[69]
  PIN o[6]
    DIRECTION OUTPUT ;
    USE SIGNAL ;
    PORT
      LAYER M5 ;
        RECT  16.848 0 16.872 0.084 ;
    END
  END o[6]
  PIN o[70]
    DIRECTION OUTPUT ;
    USE SIGNAL ;
    PORT
      LAYER M5 ;
        RECT  29.904 0 29.928 0.084 ;
    END
  END o[70]
  PIN o[71]
    DIRECTION OUTPUT ;
    USE SIGNAL ;
    PORT
      LAYER M5 ;
        RECT  30 0 30.024 0.084 ;
    END
  END o[71]
  PIN o[72]
    DIRECTION OUTPUT ;
    USE SIGNAL ;
    PORT
      LAYER M5 ;
        RECT  30.096 0 30.12 0.084 ;
    END
  END o[72]
  PIN o[73]
    DIRECTION OUTPUT ;
    USE SIGNAL ;
    PORT
      LAYER M5 ;
        RECT  30.192 0 30.216 0.084 ;
    END
  END o[73]
  PIN o[74]
    DIRECTION OUTPUT ;
    USE SIGNAL ;
    PORT
      LAYER M5 ;
        RECT  30.288 0 30.312 0.084 ;
    END
  END o[74]
  PIN o[75]
    DIRECTION OUTPUT ;
    USE SIGNAL ;
    PORT
      LAYER M5 ;
        RECT  30.384 0 30.408 0.084 ;
    END
  END o[75]
  PIN o[76]
    DIRECTION OUTPUT ;
    USE SIGNAL ;
    PORT
      LAYER M5 ;
        RECT  30.48 0 30.504 0.084 ;
    END
  END o[76]
  PIN o[77]
    DIRECTION OUTPUT ;
    USE SIGNAL ;
    PORT
      LAYER M5 ;
        RECT  30.576 0 30.6 0.084 ;
    END
  END o[77]
  PIN o[78]
    DIRECTION OUTPUT ;
    USE SIGNAL ;
    PORT
      LAYER M5 ;
        RECT  30.672 0 30.696 0.084 ;
    END
  END o[78]
  PIN o[79]
    DIRECTION OUTPUT ;
    USE SIGNAL ;
    PORT
      LAYER M5 ;
        RECT  30.768 0 30.792 0.084 ;
    END
  END o[79]
  PIN o[7]
    DIRECTION OUTPUT ;
    USE SIGNAL ;
    PORT
      LAYER M5 ;
        RECT  16.944 0 16.968 0.084 ;
    END
  END o[7]
  PIN o[80]
    DIRECTION OUTPUT ;
    USE SIGNAL ;
    PORT
      LAYER M5 ;
        RECT  30.864 0 30.888 0.084 ;
    END
  END o[80]
  PIN o[81]
    DIRECTION OUTPUT ;
    USE SIGNAL ;
    PORT
      LAYER M5 ;
        RECT  30.96 0 30.984 0.084 ;
    END
  END o[81]
  PIN o[82]
    DIRECTION OUTPUT ;
    USE SIGNAL ;
    PORT
      LAYER M5 ;
        RECT  31.056 0 31.08 0.084 ;
    END
  END o[82]
  PIN o[83]
    DIRECTION OUTPUT ;
    USE SIGNAL ;
    PORT
      LAYER M5 ;
        RECT  31.152 0 31.176 0.084 ;
    END
  END o[83]
  PIN o[84]
    DIRECTION OUTPUT ;
    USE SIGNAL ;
    PORT
      LAYER M5 ;
        RECT  31.248 0 31.272 0.084 ;
    END
  END o[84]
  PIN o[85]
    DIRECTION OUTPUT ;
    USE SIGNAL ;
    PORT
      LAYER M5 ;
        RECT  31.344 0 31.368 0.084 ;
    END
  END o[85]
  PIN o[86]
    DIRECTION OUTPUT ;
    USE SIGNAL ;
    PORT
      LAYER M5 ;
        RECT  31.44 0 31.464 0.084 ;
    END
  END o[86]
  PIN o[87]
    DIRECTION OUTPUT ;
    USE SIGNAL ;
    PORT
      LAYER M5 ;
        RECT  31.536 0 31.56 0.084 ;
    END
  END o[87]
  PIN o[88]
    DIRECTION OUTPUT ;
    USE SIGNAL ;
    PORT
      LAYER M5 ;
        RECT  31.632 0 31.656 0.084 ;
    END
  END o[88]
  PIN o[89]
    DIRECTION OUTPUT ;
    USE SIGNAL ;
    PORT
      LAYER M5 ;
        RECT  31.728 0 31.752 0.084 ;
    END
  END o[89]
  PIN o[8]
    DIRECTION OUTPUT ;
    USE SIGNAL ;
    PORT
      LAYER M5 ;
        RECT  17.04 0 17.064 0.084 ;
    END
  END o[8]
  PIN o[90]
    DIRECTION OUTPUT ;
    USE SIGNAL ;
    PORT
      LAYER M5 ;
        RECT  31.824 0 31.848 0.084 ;
    END
  END o[90]
  PIN o[91]
    DIRECTION OUTPUT ;
    USE SIGNAL ;
    PORT
      LAYER M5 ;
        RECT  31.92 0 31.944 0.084 ;
    END
  END o[91]
  PIN o[92]
    DIRECTION OUTPUT ;
    USE SIGNAL ;
    PORT
      LAYER M5 ;
        RECT  32.016 0 32.04 0.084 ;
    END
  END o[92]
  PIN o[93]
    DIRECTION OUTPUT ;
    USE SIGNAL ;
    PORT
      LAYER M5 ;
        RECT  32.112 0 32.136 0.084 ;
    END
  END o[93]
  PIN o[94]
    DIRECTION OUTPUT ;
    USE SIGNAL ;
    PORT
      LAYER M3 ;
        RECT  38.556 0 38.574 0.037 ;
    END
  END o[94]
  PIN o[95]
    DIRECTION OUTPUT ;
    USE SIGNAL ;
    PORT
      LAYER M3 ;
        RECT  38.628 0 38.646 0.037 ;
    END
  END o[95]
  PIN o[96]
    DIRECTION OUTPUT ;
    USE SIGNAL ;
    PORT
      LAYER M3 ;
        RECT  38.7 0 38.718 0.037 ;
    END
  END o[96]
  PIN o[97]
    DIRECTION OUTPUT ;
    USE SIGNAL ;
    PORT
      LAYER M3 ;
        RECT  38.772 0 38.79 0.037 ;
    END
  END o[97]
  PIN o[98]
    DIRECTION OUTPUT ;
    USE SIGNAL ;
    PORT
      LAYER M3 ;
        RECT  38.844 0 38.862 0.037 ;
    END
  END o[98]
  PIN o[99]
    DIRECTION OUTPUT ;
    USE SIGNAL ;
    PORT
      LAYER M3 ;
        RECT  38.916 0 38.934 0.037 ;
    END
  END o[99]
  PIN o[9]
    DIRECTION OUTPUT ;
    USE SIGNAL ;
    PORT
      LAYER M5 ;
        RECT  17.136 0 17.16 0.084 ;
    END
  END o[9]
  PIN rs
    DIRECTION INPUT ;
    USE SIGNAL ;
    PORT
      LAYER M4 ;
        RECT  51.756 38.64 51.84 38.664 ;
    END
  END rs
  PIN VDD
    DIRECTION INOUT ;
    USE POWER ;
    PORT
      LAYER M5 ;
        RECT  48.492 2.151 48.612 62.649 ;
        RECT  45.792 2.151 45.912 62.649 ;
        RECT  43.092 2.151 43.212 62.649 ;
        RECT  40.392 2.151 40.512 62.649 ;
        RECT  37.692 2.151 37.812 62.649 ;
        RECT  34.992 2.151 35.112 62.649 ;
        RECT  32.292 2.151 32.412 62.649 ;
        RECT  29.592 2.151 29.712 62.649 ;
        RECT  26.892 2.151 27.012 62.649 ;
        RECT  24.192 2.151 24.312 62.649 ;
        RECT  21.492 2.151 21.612 62.649 ;
        RECT  18.792 2.151 18.912 62.649 ;
        RECT  16.092 2.151 16.212 62.649 ;
        RECT  13.392 2.151 13.512 62.649 ;
        RECT  10.692 2.151 10.812 62.649 ;
        RECT  7.992 2.151 8.112 62.649 ;
        RECT  5.292 2.151 5.412 62.649 ;
        RECT  2.592 2.151 2.712 62.649 ;
    END
  END VDD
  PIN VSS
    DIRECTION INOUT ;
    USE GROUND ;
    PORT
      LAYER M5 ;
        RECT  48.3 2.137 48.42 62.663 ;
        RECT  45.6 2.137 45.72 62.663 ;
        RECT  42.9 2.137 43.02 62.663 ;
        RECT  40.2 2.137 40.32 62.663 ;
        RECT  37.5 2.137 37.62 62.663 ;
        RECT  34.8 2.137 34.92 62.663 ;
        RECT  32.1 2.137 32.22 62.663 ;
        RECT  29.4 2.137 29.52 62.663 ;
        RECT  26.7 2.137 26.82 62.663 ;
        RECT  24 2.137 24.12 62.663 ;
        RECT  21.3 2.137 21.42 62.663 ;
        RECT  18.6 2.137 18.72 62.663 ;
        RECT  15.9 2.137 16.02 62.663 ;
        RECT  13.2 2.137 13.32 62.663 ;
        RECT  10.5 2.137 10.62 62.663 ;
        RECT  7.8 2.137 7.92 62.663 ;
        RECT  5.1 2.137 5.22 62.663 ;
        RECT  2.4 2.137 2.52 62.663 ;
    END
  END VSS
  OBS
    LAYER RVTN ;
     RECT  2.16 2.16 49.68 2.295 ;
     RECT  2.16 2.565 49.68 2.835 ;
     RECT  2.16 3.105 49.68 3.375 ;
     RECT  2.16 3.645 49.68 3.915 ;
     RECT  2.16 4.185 49.68 4.455 ;
     RECT  2.16 4.725 49.68 4.995 ;
     RECT  2.16 5.265 49.68 5.535 ;
     RECT  2.16 5.805 49.68 6.075 ;
     RECT  2.16 6.345 49.68 6.615 ;
     RECT  2.16 6.885 49.68 7.155 ;
     RECT  2.16 7.425 49.68 7.695 ;
     RECT  2.16 7.965 49.68 8.235 ;
     RECT  2.16 8.505 49.68 8.775 ;
     RECT  2.16 9.045 49.68 9.315 ;
     RECT  2.16 9.585 49.68 9.855 ;
     RECT  2.16 10.125 49.68 10.395 ;
     RECT  2.16 10.665 49.68 10.935 ;
     RECT  2.16 11.205 49.68 11.475 ;
     RECT  2.16 11.745 49.68 12.015 ;
     RECT  2.16 12.285 49.68 12.555 ;
     RECT  2.16 12.825 49.68 13.095 ;
     RECT  2.16 13.365 49.68 13.635 ;
     RECT  2.16 13.905 49.68 14.175 ;
     RECT  2.16 14.445 49.68 14.715 ;
     RECT  2.16 14.985 49.68 15.255 ;
     RECT  2.16 15.525 49.68 15.795 ;
     RECT  2.16 16.065 49.68 16.335 ;
     RECT  2.16 16.605 49.68 16.875 ;
     RECT  2.16 17.145 49.68 17.415 ;
     RECT  2.16 17.685 49.68 17.955 ;
     RECT  2.16 18.225 49.68 18.495 ;
     RECT  2.16 18.765 49.68 19.035 ;
     RECT  2.16 19.305 49.68 19.575 ;
     RECT  2.16 19.845 49.68 20.115 ;
     RECT  2.16 20.385 49.68 20.655 ;
     RECT  2.16 20.925 49.68 21.195 ;
     RECT  2.16 21.465 49.68 21.735 ;
     RECT  2.16 22.005 49.68 22.275 ;
     RECT  2.16 22.545 49.68 22.815 ;
     RECT  2.16 23.085 49.68 23.355 ;
     RECT  2.16 23.625 49.68 23.895 ;
     RECT  2.16 24.165 49.68 24.435 ;
     RECT  2.16 24.705 49.68 24.975 ;
     RECT  2.16 25.245 49.68 25.515 ;
     RECT  2.16 25.785 49.68 26.055 ;
     RECT  2.16 26.325 49.68 26.595 ;
     RECT  2.16 26.865 49.68 27.135 ;
     RECT  2.16 27.405 49.68 27.675 ;
     RECT  2.16 27.945 49.68 28.215 ;
     RECT  2.16 28.485 49.68 28.755 ;
     RECT  2.16 29.025 49.68 29.295 ;
     RECT  2.16 29.565 49.68 29.835 ;
     RECT  2.16 30.105 49.68 30.375 ;
     RECT  2.16 30.645 49.68 30.915 ;
     RECT  2.16 31.185 49.68 31.455 ;
     RECT  2.16 31.725 49.68 31.995 ;
     RECT  2.16 32.265 49.68 32.535 ;
     RECT  2.16 32.805 49.68 33.075 ;
     RECT  2.16 33.345 49.68 33.615 ;
     RECT  2.16 33.885 49.68 34.155 ;
     RECT  2.16 34.425 49.68 34.695 ;
     RECT  2.16 34.965 49.68 35.235 ;
     RECT  2.16 35.505 49.68 35.775 ;
     RECT  2.16 36.045 49.68 36.315 ;
     RECT  2.16 36.585 49.68 36.855 ;
     RECT  2.16 37.125 49.68 37.395 ;
     RECT  2.16 37.665 49.68 37.935 ;
     RECT  2.16 38.205 49.68 38.475 ;
     RECT  2.16 38.745 49.68 39.015 ;
     RECT  2.16 39.285 49.68 39.555 ;
     RECT  2.16 39.825 49.68 40.095 ;
     RECT  2.16 40.365 49.68 40.635 ;
     RECT  2.16 40.905 49.68 41.175 ;
     RECT  2.16 41.445 49.68 41.715 ;
     RECT  2.16 41.985 49.68 42.255 ;
     RECT  2.16 42.525 49.68 42.795 ;
     RECT  2.16 43.065 49.68 43.335 ;
     RECT  2.16 43.605 49.68 43.875 ;
     RECT  2.16 44.145 49.68 44.415 ;
     RECT  2.16 44.685 49.68 44.955 ;
     RECT  2.16 45.225 49.68 45.495 ;
     RECT  2.16 45.765 49.68 46.035 ;
     RECT  2.16 46.305 49.68 46.575 ;
     RECT  2.16 46.845 49.68 47.115 ;
     RECT  2.16 47.385 49.68 47.655 ;
     RECT  2.16 47.925 49.68 48.195 ;
     RECT  2.16 48.465 49.68 48.735 ;
     RECT  2.16 49.005 49.68 49.275 ;
     RECT  2.16 49.545 49.68 49.815 ;
     RECT  2.16 50.085 49.68 50.355 ;
     RECT  2.16 50.625 49.68 50.895 ;
     RECT  2.16 51.165 49.68 51.435 ;
     RECT  2.16 51.705 49.68 51.975 ;
     RECT  2.16 52.245 49.68 52.515 ;
     RECT  2.16 52.785 49.68 53.055 ;
     RECT  2.16 53.325 49.68 53.595 ;
     RECT  2.16 53.865 49.68 54.135 ;
     RECT  2.16 54.405 49.68 54.675 ;
     RECT  2.16 54.945 49.68 55.215 ;
     RECT  2.16 55.485 49.68 55.755 ;
     RECT  2.16 56.025 49.68 56.295 ;
     RECT  2.16 56.565 49.68 56.835 ;
     RECT  2.16 57.105 49.68 57.375 ;
     RECT  2.16 57.645 49.68 57.915 ;
     RECT  2.16 58.185 49.68 58.455 ;
     RECT  2.16 58.725 49.68 58.995 ;
     RECT  2.16 59.265 49.68 59.535 ;
     RECT  2.16 59.805 49.68 60.075 ;
     RECT  2.16 60.345 49.68 60.615 ;
     RECT  2.16 60.885 49.68 61.155 ;
     RECT  2.16 61.425 49.68 61.695 ;
     RECT  2.16 61.965 49.68 62.235 ;
     RECT  2.16 62.505 49.68 62.64 ;
    LAYER RVTP ;
     RECT  2.16 2.295 49.68 2.565 ;
     RECT  2.16 2.835 49.68 3.105 ;
     RECT  2.16 3.375 49.68 3.645 ;
     RECT  2.16 3.915 49.68 4.185 ;
     RECT  2.16 4.455 49.68 4.725 ;
     RECT  2.16 4.995 49.68 5.265 ;
     RECT  2.16 5.535 49.68 5.805 ;
     RECT  2.16 6.075 49.68 6.345 ;
     RECT  2.16 6.615 49.68 6.885 ;
     RECT  2.16 7.155 49.68 7.425 ;
     RECT  2.16 7.695 49.68 7.965 ;
     RECT  2.16 8.235 49.68 8.505 ;
     RECT  2.16 8.775 49.68 9.045 ;
     RECT  2.16 9.315 49.68 9.585 ;
     RECT  2.16 9.855 49.68 10.125 ;
     RECT  2.16 10.395 49.68 10.665 ;
     RECT  2.16 10.935 49.68 11.205 ;
     RECT  2.16 11.475 49.68 11.745 ;
     RECT  2.16 12.015 49.68 12.285 ;
     RECT  2.16 12.555 49.68 12.825 ;
     RECT  2.16 13.095 49.68 13.365 ;
     RECT  2.16 13.635 49.68 13.905 ;
     RECT  2.16 14.175 49.68 14.445 ;
     RECT  2.16 14.715 49.68 14.985 ;
     RECT  2.16 15.255 49.68 15.525 ;
     RECT  2.16 15.795 49.68 16.065 ;
     RECT  2.16 16.335 49.68 16.605 ;
     RECT  2.16 16.875 49.68 17.145 ;
     RECT  2.16 17.415 49.68 17.685 ;
     RECT  2.16 17.955 49.68 18.225 ;
     RECT  2.16 18.495 49.68 18.765 ;
     RECT  2.16 19.035 49.68 19.305 ;
     RECT  2.16 19.575 49.68 19.845 ;
     RECT  2.16 20.115 49.68 20.385 ;
     RECT  2.16 20.655 49.68 20.925 ;
     RECT  2.16 21.195 49.68 21.465 ;
     RECT  2.16 21.735 49.68 22.005 ;
     RECT  2.16 22.275 49.68 22.545 ;
     RECT  2.16 22.815 49.68 23.085 ;
     RECT  2.16 23.355 49.68 23.625 ;
     RECT  2.16 23.895 49.68 24.165 ;
     RECT  2.16 24.435 49.68 24.705 ;
     RECT  2.16 24.975 49.68 25.245 ;
     RECT  2.16 25.515 49.68 25.785 ;
     RECT  2.16 26.055 49.68 26.325 ;
     RECT  2.16 26.595 49.68 26.865 ;
     RECT  2.16 27.135 49.68 27.405 ;
     RECT  2.16 27.675 49.68 27.945 ;
     RECT  2.16 28.215 49.68 28.485 ;
     RECT  2.16 28.755 49.68 29.025 ;
     RECT  2.16 29.295 49.68 29.565 ;
     RECT  2.16 29.835 49.68 30.105 ;
     RECT  2.16 30.375 49.68 30.645 ;
     RECT  2.16 30.915 49.68 31.185 ;
     RECT  2.16 31.455 49.68 31.725 ;
     RECT  2.16 31.995 49.68 32.265 ;
     RECT  2.16 32.535 49.68 32.805 ;
     RECT  2.16 33.075 49.68 33.345 ;
     RECT  2.16 33.615 49.68 33.885 ;
     RECT  2.16 34.155 49.68 34.425 ;
     RECT  2.16 34.695 49.68 34.965 ;
     RECT  2.16 35.235 49.68 35.505 ;
     RECT  2.16 35.775 49.68 36.045 ;
     RECT  2.16 36.315 49.68 36.585 ;
     RECT  2.16 36.855 49.68 37.125 ;
     RECT  2.16 37.395 49.68 37.665 ;
     RECT  2.16 37.935 49.68 38.205 ;
     RECT  2.16 38.475 49.68 38.745 ;
     RECT  2.16 39.015 49.68 39.285 ;
     RECT  2.16 39.555 49.68 39.825 ;
     RECT  2.16 40.095 49.68 40.365 ;
     RECT  2.16 40.635 49.68 40.905 ;
     RECT  2.16 41.175 49.68 41.445 ;
     RECT  2.16 41.715 49.68 41.985 ;
     RECT  2.16 42.255 49.68 42.525 ;
     RECT  2.16 42.795 49.68 43.065 ;
     RECT  2.16 43.335 49.68 43.605 ;
     RECT  2.16 43.875 49.68 44.145 ;
     RECT  2.16 44.415 49.68 44.685 ;
     RECT  2.16 44.955 49.68 45.225 ;
     RECT  2.16 45.495 49.68 45.765 ;
     RECT  2.16 46.035 49.68 46.305 ;
     RECT  2.16 46.575 49.68 46.845 ;
     RECT  2.16 47.115 49.68 47.385 ;
     RECT  2.16 47.655 49.68 47.925 ;
     RECT  2.16 48.195 49.68 48.465 ;
     RECT  2.16 48.735 49.68 49.005 ;
     RECT  2.16 49.275 49.68 49.545 ;
     RECT  2.16 49.815 49.68 50.085 ;
     RECT  2.16 50.355 49.68 50.625 ;
     RECT  2.16 50.895 49.68 51.165 ;
     RECT  2.16 51.435 49.68 51.705 ;
     RECT  2.16 51.975 49.68 52.245 ;
     RECT  2.16 52.515 49.68 52.785 ;
     RECT  2.16 53.055 49.68 53.325 ;
     RECT  2.16 53.595 49.68 53.865 ;
     RECT  2.16 54.135 49.68 54.405 ;
     RECT  2.16 54.675 49.68 54.945 ;
     RECT  2.16 55.215 49.68 55.485 ;
     RECT  2.16 55.755 49.68 56.025 ;
     RECT  2.16 56.295 49.68 56.565 ;
     RECT  2.16 56.835 49.68 57.105 ;
     RECT  2.16 57.375 49.68 57.645 ;
     RECT  2.16 57.915 49.68 58.185 ;
     RECT  2.16 58.455 49.68 58.725 ;
     RECT  2.16 58.995 49.68 59.265 ;
     RECT  2.16 59.535 49.68 59.805 ;
     RECT  2.16 60.075 49.68 60.345 ;
     RECT  2.16 60.615 49.68 60.885 ;
     RECT  2.16 61.155 49.68 61.425 ;
     RECT  2.16 61.695 49.68 61.965 ;
     RECT  2.16 62.235 49.68 62.505 ;
    LAYER M1 ;
     RECT  2.16 2.151 49.68 62.649 ;
    LAYER M2 ;
     RECT  2.16 2.151 4.279 62.649 ;
     RECT  4.279 2.106 4.495 62.649 ;
     RECT  4.495 2.034 5.423 62.649 ;
     RECT  5.423 2.151 6.799 62.649 ;
     RECT  6.799 2.106 6.979 62.649 ;
     RECT  6.979 2.034 7.123 62.649 ;
     RECT  7.123 2.034 7.223 62.694 ;
     RECT  7.223 2.034 8.743 62.649 ;
     RECT  8.743 2.034 8.915 62.694 ;
     RECT  8.915 2.034 10.219 62.649 ;
     RECT  10.219 2.034 11.651 63 ;
     RECT  9.931 63.981 11.651 63.999 ;
     RECT  12.919 64.71 13.055 64.728 ;
     RECT  13.063 63.981 13.351 63.999 ;
     RECT  14.251 1.152 14.495 1.242 ;
     RECT  14.495 1.224 14.567 1.242 ;
     RECT  13.351 63.864 14.603 63.999 ;
     RECT  11.651 2.07 14.719 63 ;
     RECT  14.603 63.864 14.719 63.918 ;
     RECT  14.719 2.07 14.855 63.918 ;
     RECT  14.855 63.9 15.439 63.918 ;
     RECT  15.583 1.152 15.683 1.17 ;
     RECT  15.439 63.9 15.683 63.999 ;
     RECT  14.855 2.07 16.367 63 ;
     RECT  17.239 0.108 17.311 0.126 ;
     RECT  16.367 2.151 17.383 63 ;
     RECT  14.719 64.746 17.483 64.764 ;
     RECT  17.383 1.728 17.519 63 ;
     RECT  15.683 63.981 17.663 63.999 ;
     RECT  17.311 0.036 17.887 0.126 ;
     RECT  17.599 0.882 17.887 0.9 ;
     RECT  17.887 0.036 18.391 0.9 ;
     RECT  17.519 1.8 18.391 63 ;
     RECT  18.391 0.036 20.183 63 ;
     RECT  20.183 0.036 22.199 62.649 ;
     RECT  22.199 0.036 22.415 1.206 ;
     RECT  22.415 0.036 22.631 1.17 ;
     RECT  22.631 0.036 22.703 0.738 ;
     RECT  22.703 0.036 22.919 0.234 ;
     RECT  22.919 0.036 23.063 0.054 ;
     RECT  22.199 2.151 25.159 62.649 ;
     RECT  25.159 2.07 26.167 62.649 ;
     RECT  26.167 2.034 27.247 62.649 ;
     RECT  27.247 1.962 27.787 62.649 ;
     RECT  27.787 1.962 28.111 62.73 ;
     RECT  28.111 1.962 28.535 62.919 ;
     RECT  28.535 1.998 28.651 62.919 ;
     RECT  29.191 64.746 29.263 64.764 ;
     RECT  28.651 1.998 29.695 62.964 ;
     RECT  29.263 64.674 29.767 64.764 ;
     RECT  29.695 1.998 30.623 63.306 ;
     RECT  30.623 1.998 31.891 62.649 ;
     RECT  29.767 64.602 32.279 64.764 ;
     RECT  32.279 64.746 33.215 64.764 ;
     RECT  33.763 0.108 33.943 0.126 ;
     RECT  33.943 0.036 34.087 0.126 ;
     RECT  34.087 0.036 34.735 0.279 ;
     RECT  34.735 0.036 34.807 0.9 ;
     RECT  34.807 0.036 34.879 1.17 ;
     RECT  31.891 1.926 34.879 62.649 ;
     RECT  34.879 0.036 34.979 62.649 ;
     RECT  34.979 0.036 35.951 1.17 ;
     RECT  35.951 0.036 36.059 0.9 ;
     RECT  36.059 0.036 37.075 0.594 ;
     RECT  34.979 1.962 37.075 62.649 ;
     RECT  37.075 0.036 37.211 62.649 ;
     RECT  37.211 0.036 37.679 1.17 ;
     RECT  37.679 0.036 37.895 0.054 ;
     RECT  37.679 1.152 37.967 1.17 ;
     RECT  38.551 0.108 38.767 0.126 ;
     RECT  37.211 1.962 38.767 62.649 ;
     RECT  38.767 1.26 38.839 62.649 ;
     RECT  38.767 0.036 38.875 0.126 ;
     RECT  38.839 1.152 39.227 62.649 ;
     RECT  38.875 0.036 39.271 0.324 ;
     RECT  39.227 1.998 39.307 62.649 ;
     RECT  39.271 0.036 39.451 0.36 ;
     RECT  39.307 1.998 39.523 63.378 ;
     RECT  39.451 0.036 39.775 0.396 ;
     RECT  39.227 1.152 39.775 1.242 ;
     RECT  39.775 0.036 39.803 1.242 ;
     RECT  39.803 0.036 40.163 1.17 ;
     RECT  39.523 1.998 40.199 63.882 ;
     RECT  40.199 2.151 40.451 63.882 ;
     RECT  40.163 0.036 41.063 0.594 ;
     RECT  40.451 2.151 41.063 62.874 ;
     RECT  41.063 0.108 41.071 0.594 ;
     RECT  41.063 2.151 41.143 62.694 ;
     RECT  40.639 63.936 41.287 63.954 ;
     RECT  41.071 0.108 41.387 1.17 ;
     RECT  41.387 0.108 41.711 0.549 ;
     RECT  41.287 63.864 41.791 63.954 ;
     RECT  41.215 64.746 41.791 64.764 ;
     RECT  41.711 0.108 42.575 0.468 ;
     RECT  41.143 2.106 42.583 62.694 ;
     RECT  42.575 0.45 42.683 0.468 ;
     RECT  42.583 2.106 42.727 62.73 ;
     RECT  41.791 63.864 42.727 64.764 ;
     RECT  43.375 1.152 43.475 1.17 ;
     RECT  42.727 2.106 43.979 64.764 ;
     RECT  43.979 2.106 44.167 63.306 ;
     RECT  43.979 64.566 44.915 64.764 ;
     RECT  44.915 64.602 45.023 64.764 ;
     RECT  44.167 1.881 45.211 63.306 ;
     RECT  45.211 1.692 45.599 63.306 ;
     RECT  45.599 1.692 45.635 62.649 ;
     RECT  45.023 64.746 45.779 64.764 ;
     RECT  45.635 1.728 46.571 62.649 ;
     RECT  45.499 0.036 46.687 0.054 ;
     RECT  46.687 0.036 47.443 0.279 ;
     RECT  46.571 1.881 48.191 62.649 ;
     RECT  47.443 0.036 48.199 0.324 ;
     RECT  48.199 0.036 48.299 0.396 ;
     RECT  48.299 0.036 49.055 0.324 ;
     RECT  49.055 0.18 49.271 0.324 ;
     RECT  49.271 0.18 49.379 0.279 ;
     RECT  49.379 0.18 49.559 0.198 ;
     RECT  48.191 2.151 49.68 62.649 ;
     RECT  49.68 3.186 49.703 3.33 ;
     RECT  49.68 19.476 49.703 19.494 ;
     RECT  49.68 4.77 49.739 4.788 ;
     RECT  49.68 17.766 49.739 17.784 ;
     RECT  49.68 7.326 49.775 7.344 ;
     RECT  49.68 16.416 49.775 16.434 ;
     RECT  49.703 3.312 49.811 3.33 ;
     RECT  49.68 28.296 49.811 28.314 ;
     RECT  49.68 38.484 50.171 38.736 ;
     RECT  50.171 38.718 50.675 38.736 ;
     RECT  49.68 39.6 50.747 39.816 ;
     RECT  50.747 39.798 51.683 39.816 ;
    LAYER M3 ;
     RECT  38.556 0.012 40.806 0.031 ;
     RECT  46.044 0.012 48.294 0.031 ;
     RECT  45.504 0.031 48.294 0.067 ;
     RECT  49.032 0.031 49.05 0.067 ;
     RECT  17.244 0.012 19.494 0.091 ;
     RECT  45.504 0.067 49.05 0.091 ;
     RECT  23.04 0.031 23.058 0.103 ;
     RECT  33.12 0.091 33.138 0.103 ;
     RECT  33.948 0.012 36.198 0.103 ;
     RECT  36.936 0.067 36.954 0.103 ;
     RECT  37.872 0.031 41.058 0.103 ;
     RECT  42.48 0.043 42.498 0.103 ;
     RECT  36.936 0.103 41.058 0.131 ;
     RECT  12.312 0.091 12.33 0.139 ;
     RECT  14.544 0.091 15.03 0.139 ;
     RECT  16.776 0.091 19.494 0.139 ;
     RECT  22.572 0.103 23.058 0.139 ;
     RECT  31.5 0.091 31.518 0.139 ;
     RECT  33.12 0.103 36.198 0.139 ;
     RECT  36.936 0.131 37.89 0.139 ;
     RECT  42.48 0.103 42.57 0.139 ;
     RECT  38.628 0.131 41.058 0.175 ;
     RECT  45.036 0.091 49.05 0.175 ;
     RECT  12.312 0.139 15.03 0.187 ;
     RECT  15.768 0.091 15.786 0.187 ;
     RECT  29.16 0.091 29.898 0.187 ;
     RECT  30.924 0.139 31.734 0.187 ;
     RECT  33.12 0.139 37.89 0.187 ;
     RECT  20.448 0.031 20.538 0.211 ;
     RECT  12.024 0.187 15.786 0.235 ;
     RECT  16.596 0.139 19.494 0.235 ;
     RECT  12.024 0.235 19.494 0.256 ;
     RECT  20.448 0.211 20.682 0.256 ;
     RECT  38.628 0.175 41.634 0.256 ;
     RECT  42.444 0.139 42.57 0.256 ;
     RECT  12.024 0.256 20.682 0.373 ;
     RECT  45.036 0.175 49.554 0.379 ;
     RECT  38.628 0.256 42.57 0.445 ;
     RECT  43.38 0.043 43.398 0.445 ;
     RECT  29.16 0.187 29.934 0.475 ;
     RECT  30.924 0.187 37.89 0.475 ;
     RECT  44.64 0.379 49.554 0.475 ;
     RECT  10.224 0.139 10.242 0.523 ;
     RECT  9.792 0.523 10.674 1.099 ;
     RECT  29.16 0.475 37.89 1.147 ;
     RECT  38.628 0.445 43.398 1.147 ;
     RECT  29.16 1.147 43.47 1.175 ;
     RECT  22.464 0.139 23.058 1.183 ;
     RECT  22.392 1.183 23.058 1.387 ;
     RECT  22.392 1.387 23.778 1.417 ;
     RECT  43.452 1.175 43.47 1.876 ;
     RECT  44.532 0.475 49.554 1.876 ;
     RECT  29.16 1.175 42.678 1.957 ;
     RECT  9.756 1.099 10.674 1.963 ;
     RECT  9.756 1.963 10.89 2.011 ;
     RECT  12.024 0.373 21.294 2.029 ;
     RECT  27.252 1.957 27.27 2.029 ;
     RECT  4.5 2.029 4.518 2.101 ;
     RECT  5.4 2.029 5.418 2.101 ;
     RECT  6.984 2.029 7.002 2.101 ;
     RECT  26.172 2.029 26.19 2.101 ;
     RECT  27.252 2.029 27.666 2.101 ;
     RECT  28.512 1.957 42.678 2.101 ;
     RECT  11.628 2.029 21.294 2.143 ;
     RECT  22.176 1.417 23.778 2.143 ;
     RECT  26.172 2.101 26.442 2.143 ;
     RECT  27.252 2.101 42.678 2.143 ;
     RECT  43.452 1.876 49.554 2.143 ;
     RECT  6.804 2.101 7.002 2.191 ;
     RECT  7.815 2.143 7.905 2.191 ;
     RECT  9.324 2.011 10.89 2.191 ;
     RECT  11.628 2.143 21.405 2.191 ;
     RECT  22.176 2.143 24.105 2.191 ;
     RECT  9.036 2.191 10.89 2.203 ;
     RECT  11.628 2.191 24.105 2.203 ;
     RECT  3.492 2.191 3.51 2.227 ;
     RECT  4.284 2.101 5.418 2.227 ;
     RECT  6.192 2.191 7.905 2.227 ;
     RECT  9.036 2.203 24.105 2.227 ;
     RECT  25.164 2.065 25.182 2.227 ;
     RECT  2.415 2.143 2.505 2.263 ;
     RECT  3.384 2.227 3.51 2.263 ;
     RECT  4.284 2.227 25.182 2.263 ;
     RECT  26.172 2.143 49.554 2.263 ;
     RECT  2.415 2.263 3.51 2.335 ;
     RECT  4.284 2.263 49.554 2.335 ;
     RECT  2.415 2.335 49.554 3.181 ;
     RECT  2.415 3.181 49.698 3.307 ;
     RECT  2.415 3.307 49.806 4.939 ;
     RECT  2.412 4.939 49.806 5.341 ;
     RECT  2.376 5.341 49.806 5.837 ;
     RECT  2.415 5.837 49.806 8.311 ;
     RECT  2.376 8.311 49.806 8.525 ;
     RECT  2.415 8.525 49.806 9.595 ;
     RECT  2.376 9.595 49.806 14.521 ;
     RECT  2.34 14.521 49.806 15.485 ;
     RECT  2.376 15.485 49.806 15.863 ;
     RECT  2.412 15.863 49.806 16.097 ;
     RECT  2.415 16.097 49.806 18.157 ;
     RECT  2.376 18.157 49.806 18.725 ;
     RECT  2.415 18.725 49.806 21.541 ;
     RECT  2.376 21.541 49.806 21.659 ;
     RECT  2.415 21.659 49.806 25.051 ;
     RECT  2.376 25.051 49.806 26.909 ;
     RECT  2.415 26.909 49.806 28.319 ;
     RECT  2.415 28.319 49.518 29.029 ;
     RECT  2.34 29.029 49.518 29.939 ;
     RECT  2.376 29.939 49.518 30.029 ;
     RECT  2.376 30.029 49.482 30.677 ;
     RECT  2.415 30.677 49.482 32.881 ;
     RECT  2.376 32.881 49.482 32.971 ;
     RECT  2.34 32.971 49.482 33.043 ;
     RECT  2.34 33.043 49.554 33.101 ;
     RECT  2.415 33.101 49.554 35.159 ;
     RECT  2.415 35.159 49.482 36.931 ;
     RECT  2.376 36.931 49.482 37.049 ;
     RECT  51.732 37.963 51.75 38.093 ;
     RECT  2.415 37.049 49.482 38.347 ;
     RECT  2.415 38.347 50.166 38.443 ;
     RECT  2.415 38.443 50.67 38.507 ;
     RECT  50.652 38.507 50.67 38.539 ;
     RECT  50.652 38.539 50.742 38.741 ;
     RECT  2.415 38.507 49.482 39.209 ;
     RECT  2.415 39.209 2.79 39.245 ;
     RECT  50.724 38.741 50.742 39.623 ;
     RECT  51.66 38.635 51.678 39.821 ;
     RECT  3.636 39.209 49.482 40.027 ;
     RECT  2.415 39.245 2.697 40.099 ;
     RECT  3.42 40.027 49.482 40.099 ;
     RECT  2.415 40.099 49.482 40.411 ;
     RECT  2.376 40.411 49.482 40.469 ;
     RECT  2.415 40.469 49.482 42.025 ;
     RECT  2.376 42.025 49.482 42.797 ;
     RECT  2.415 42.797 49.482 43.375 ;
     RECT  2.415 43.375 49.554 43.799 ;
     RECT  2.415 43.799 49.446 44.155 ;
     RECT  2.376 44.155 49.446 45.301 ;
     RECT  2.376 45.301 49.482 47.453 ;
     RECT  2.415 47.453 49.482 48.119 ;
     RECT  2.415 48.119 49.194 48.389 ;
     RECT  2.415 48.389 49.122 48.541 ;
     RECT  2.376 48.541 49.122 48.659 ;
     RECT  2.376 48.659 49.05 48.989 ;
     RECT  2.415 48.989 49.05 49.199 ;
     RECT  2.415 49.199 49.014 50.125 ;
     RECT  2.415 50.125 49.086 50.629 ;
     RECT  2.415 50.629 49.194 51.205 ;
     RECT  2.415 51.205 49.554 52.439 ;
     RECT  2.415 52.439 49.482 52.745 ;
     RECT  2.415 52.745 48.978 53.491 ;
     RECT  2.415 53.491 49.158 54.481 ;
     RECT  2.415 54.481 49.266 55.243 ;
     RECT  2.412 55.243 49.266 55.283 ;
     RECT  2.415 55.283 49.266 55.291 ;
     RECT  2.415 55.291 49.338 55.561 ;
     RECT  2.415 55.561 49.482 55.715 ;
     RECT  2.415 55.715 49.338 56.443 ;
     RECT  2.376 56.443 49.338 56.497 ;
     RECT  2.376 56.497 49.482 56.759 ;
     RECT  2.376 56.759 49.338 56.795 ;
     RECT  2.415 56.795 49.158 57.721 ;
     RECT  2.415 57.721 49.302 57.955 ;
     RECT  2.415 57.955 49.554 58.081 ;
     RECT  2.376 58.081 49.554 58.109 ;
     RECT  2.376 58.109 49.158 58.157 ;
     RECT  2.415 58.157 49.158 58.379 ;
     RECT  2.415 58.379 49.086 58.415 ;
     RECT  2.415 58.415 48.798 59.881 ;
     RECT  2.415 59.881 49.302 60.241 ;
     RECT  2.415 60.241 49.41 60.377 ;
     RECT  2.415 60.377 49.158 61.115 ;
     RECT  2.415 61.115 48.834 61.619 ;
     RECT  27.792 61.619 48.834 62.041 ;
     RECT  27.792 62.041 49.122 62.159 ;
     RECT  32.076 62.159 49.122 62.195 ;
     RECT  2.415 61.619 26.997 62.275 ;
     RECT  2.412 62.275 26.997 62.303 ;
     RECT  32.076 62.195 48.69 62.339 ;
     RECT  22.824 62.303 26.997 62.387 ;
     RECT  2.412 62.303 21.87 62.429 ;
     RECT  27.792 62.159 31.23 62.429 ;
     RECT  32.115 62.339 48.69 62.429 ;
     RECT  18.54 62.429 18.705 62.465 ;
     RECT  22.824 62.387 26.805 62.465 ;
     RECT  27.792 62.429 31.086 62.465 ;
     RECT  32.115 62.429 46.638 62.465 ;
     RECT  47.484 62.429 48.69 62.465 ;
     RECT  2.412 62.429 3.618 62.477 ;
     RECT  32.115 62.465 45.774 62.501 ;
     RECT  22.824 62.465 25.902 62.537 ;
     RECT  17.316 62.429 17.658 62.573 ;
     RECT  20.16 62.429 21.87 62.573 ;
     RECT  46.62 62.465 46.638 62.573 ;
     RECT  47.952 62.465 48.69 62.573 ;
     RECT  37.08 62.501 45.774 62.609 ;
     RECT  48.315 62.573 48.69 62.609 ;
     RECT  23.004 62.537 25.902 62.621 ;
     RECT  2.415 62.477 2.505 62.657 ;
     RECT  4.464 62.429 5.205 62.657 ;
     RECT  5.94 62.429 16.005 62.657 ;
     RECT  18.615 62.465 18.705 62.657 ;
     RECT  21.315 62.573 21.87 62.657 ;
     RECT  26.715 62.465 26.805 62.657 ;
     RECT  32.115 62.501 36.234 62.657 ;
     RECT  37.08 62.609 37.605 62.657 ;
     RECT  48.315 62.609 48.405 62.657 ;
     RECT  8.388 62.657 10.242 62.669 ;
     RECT  5.94 62.657 7.218 62.699 ;
     RECT  27.792 62.465 30.726 62.735 ;
     RECT  23.004 62.621 25.83 62.813 ;
     RECT  20.16 62.573 20.178 63.005 ;
     RECT  5.94 62.699 7.146 63.245 ;
     RECT  4.464 62.657 5.058 63.293 ;
     RECT  6.012 63.245 7.146 63.293 ;
     RECT  38.592 62.609 45.774 63.311 ;
     RECT  38.592 63.311 45.018 63.383 ;
     RECT  27.828 62.735 30.726 63.533 ;
     RECT  23.004 62.813 23.382 63.835 ;
     RECT  4.464 63.293 4.482 63.869 ;
     RECT  6.804 63.293 7.146 63.869 ;
     RECT  8.568 62.669 10.242 63.869 ;
     RECT  32.256 62.657 34.686 63.869 ;
     RECT  39.528 63.383 45.018 63.887 ;
     RECT  9.468 63.869 9.954 63.917 ;
     RECT  21.852 62.657 21.87 63.917 ;
     RECT  24.336 62.813 25.83 63.917 ;
     RECT  33.192 63.869 34.686 63.917 ;
     RECT  11.052 62.657 15.678 63.923 ;
     RECT  9.936 63.917 9.954 64.004 ;
     RECT  17.46 62.573 17.658 64.004 ;
     RECT  38.592 63.383 38.61 64.349 ;
     RECT  6.012 63.293 6.03 64.459 ;
     RECT  22.68 63.835 23.382 64.493 ;
     RECT  35.496 62.657 36.234 64.493 ;
     RECT  23.004 64.493 23.382 64.507 ;
     RECT  23.004 64.507 23.85 64.541 ;
     RECT  37.08 62.657 37.098 64.541 ;
     RECT  6.012 64.459 6.138 64.589 ;
     RECT  32.256 63.869 32.274 64.625 ;
     RECT  39.78 63.887 45.018 64.625 ;
     RECT  6.012 64.589 6.03 64.637 ;
     RECT  23.292 64.541 23.85 64.637 ;
     RECT  36.216 64.493 36.234 64.637 ;
     RECT  27.828 63.533 29.934 64.651 ;
     RECT  30.708 63.533 30.726 64.669 ;
     RECT  7.128 63.869 7.146 64.685 ;
     RECT  8.568 63.869 8.586 64.685 ;
     RECT  23.364 64.637 23.778 64.685 ;
     RECT  24.588 63.917 25.83 64.685 ;
     RECT  33.192 63.917 34.254 64.685 ;
     RECT  11.052 63.923 15.534 64.699 ;
     RECT  27.756 64.651 29.934 64.699 ;
     RECT  34.992 64.555 35.01 64.733 ;
     RECT  38.772 64.555 38.79 64.733 ;
     RECT  17.46 64.004 17.478 64.769 ;
     RECT  30.708 64.669 30.798 64.769 ;
     RECT  33.192 64.685 33.21 64.769 ;
     RECT  39.78 64.625 44.514 64.769 ;
     RECT  45.756 63.311 45.774 64.769 ;
     RECT  10.98 64.699 15.534 64.781 ;
     RECT  27.684 64.699 29.934 64.781 ;
     RECT  39.78 64.769 44.334 64.781 ;
    LAYER M4 ;
     RECT  2.401 4.944 2.408 5.064 ;
     RECT  2.365 8.496 2.408 8.52 ;
     RECT  2.365 9.6 2.408 9.624 ;
     RECT  2.365 10.896 2.408 10.92 ;
     RECT  2.365 13.632 2.408 13.656 ;
     RECT  2.365 25.488 2.408 25.512 ;
     RECT  2.365 26.88 2.408 26.904 ;
     RECT  2.329 33.072 2.408 33.096 ;
     RECT  2.365 40.416 2.408 40.44 ;
     RECT  2.293 42.768 2.408 42.792 ;
     RECT  2.293 44.16 2.408 44.184 ;
     RECT  2.365 48.96 2.408 48.984 ;
     RECT  2.293 55.248 2.408 55.272 ;
     RECT  2.293 56.448 2.408 56.472 ;
     RECT  2.365 58.128 2.408 58.152 ;
     RECT  2.401 62.448 2.408 62.472 ;
     RECT  2.408 2.148 2.512 62.652 ;
     RECT  2.512 2.418 2.704 62.472 ;
     RECT  2.704 58.032 2.945 58.152 ;
     RECT  2.704 20.304 3.197 28.488 ;
     RECT  2.704 42.768 3.197 43.608 ;
     RECT  2.704 2.592 3.485 16.776 ;
     RECT  2.704 46.608 3.697 46.632 ;
     RECT  2.704 33.072 3.733 34.248 ;
     RECT  2.704 35.28 3.733 38.232 ;
     RECT  2.704 61.2 3.733 61.224 ;
     RECT  3.733 33.072 3.737 38.232 ;
     RECT  2.704 48.432 3.805 50.232 ;
     RECT  2.704 18.096 3.913 18.84 ;
     RECT  2.704 52.464 3.913 52.488 ;
     RECT  3.913 52.464 3.925 53.016 ;
     RECT  2.704 54.144 3.925 55.944 ;
     RECT  3.485 2.592 3.949 14.472 ;
     RECT  3.925 52.464 3.971 55.944 ;
     RECT  2.704 31.872 3.985 31.896 ;
     RECT  3.737 33.072 3.985 36.072 ;
     RECT  3.737 37.104 3.985 38.232 ;
     RECT  2.704 40.416 4.021 41.688 ;
     RECT  3.971 54.624 4.021 55.944 ;
     RECT  3.197 43.584 4.057 43.608 ;
     RECT  3.913 18.096 4.093 19.224 ;
     RECT  3.197 20.304 4.093 22.104 ;
     RECT  4.021 54.624 4.093 56.04 ;
     RECT  2.704 57.024 4.093 57.048 ;
     RECT  2.945 58.032 4.093 58.056 ;
     RECT  3.485 15.456 4.124 16.776 ;
     RECT  4.093 54.624 4.129 58.056 ;
     RECT  3.692 60.192 4.129 60.216 ;
     RECT  3.733 61.2 4.129 61.464 ;
     RECT  3.805 48.432 4.133 51.144 ;
     RECT  4.133 51.12 4.165 51.144 ;
     RECT  3.971 52.464 4.165 53.592 ;
     RECT  4.057 43.584 4.172 43.944 ;
     RECT  4.093 18.096 4.201 22.104 ;
     RECT  3.197 23.568 4.201 28.488 ;
     RECT  4.124 15.456 4.213 16.824 ;
     RECT  4.133 48.432 4.237 50.136 ;
     RECT  4.129 60.192 4.309 61.464 ;
     RECT  4.129 54.624 4.345 58.152 ;
     RECT  4.345 54.624 4.489 58.68 ;
     RECT  4.453 63.84 4.501 63.864 ;
     RECT  2.704 30.048 4.525 30.84 ;
     RECT  3.985 31.872 4.525 36.072 ;
     RECT  2.704 62.448 4.525 62.472 ;
     RECT  4.501 63.744 4.525 63.864 ;
     RECT  4.525 30.048 4.549 36.072 ;
     RECT  2.704 45.024 4.561 45.048 ;
     RECT  3.697 46.032 4.561 46.632 ;
     RECT  4.021 39.984 4.597 41.688 ;
     RECT  4.172 42.768 4.597 43.944 ;
     RECT  4.309 60.096 4.669 61.464 ;
     RECT  4.201 18.096 4.693 28.488 ;
     RECT  4.549 29.472 4.693 36.072 ;
     RECT  4.213 15.456 4.741 17.112 ;
     RECT  4.693 18.096 4.741 36.072 ;
     RECT  4.561 45.024 4.777 46.632 ;
     RECT  4.669 59.808 4.777 61.464 ;
     RECT  4.525 62.448 4.777 63.864 ;
     RECT  4.777 59.808 4.789 63.864 ;
     RECT  4.777 44.976 4.813 46.632 ;
     RECT  3.949 2.496 4.849 14.472 ;
     RECT  4.741 15.456 4.849 36.072 ;
     RECT  4.813 44.976 4.849 46.824 ;
     RECT  4.237 47.904 4.849 50.136 ;
     RECT  3.985 37.104 4.885 39 ;
     RECT  4.597 39.984 4.885 43.944 ;
     RECT  4.885 37.104 4.921 43.944 ;
     RECT  4.849 44.976 4.921 50.136 ;
     RECT  4.489 54.624 4.933 58.728 ;
     RECT  4.789 59.808 4.933 64.632 ;
     RECT  4.849 2.496 4.981 36.072 ;
     RECT  4.921 37.104 4.981 50.136 ;
     RECT  4.165 51.12 4.981 53.592 ;
     RECT  4.933 54.624 4.981 64.632 ;
     RECT  4.981 2.496 5.108 50.136 ;
     RECT  4.981 51.12 5.108 64.632 ;
     RECT  5.108 2.148 5.212 64.632 ;
     RECT  5.212 2.418 5.404 64.632 ;
     RECT  5.404 55.728 5.509 64.632 ;
     RECT  5.404 2.418 5.555 24.936 ;
     RECT  5.404 26.256 5.609 50.136 ;
     RECT  5.509 55.728 5.651 64.68 ;
     RECT  5.609 26.256 5.747 47.112 ;
     RECT  5.609 48.24 5.753 50.136 ;
     RECT  5.651 55.728 5.789 63.24 ;
     RECT  5.747 26.256 5.897 44.952 ;
     RECT  5.789 59.232 5.941 63.24 ;
     RECT  5.897 34.752 5.969 44.952 ;
     RECT  5.897 26.256 6.149 33.384 ;
     RECT  5.753 50.112 6.185 50.136 ;
     RECT  6.149 26.256 6.221 32.04 ;
     RECT  6.221 30.768 6.227 32.04 ;
     RECT  5.555 2.418 6.229 19.272 ;
     RECT  5.969 34.752 6.293 39.288 ;
     RECT  5.941 61.104 6.329 63.24 ;
     RECT  5.941 59.232 6.371 60.072 ;
     RECT  5.555 20.4 6.505 24.936 ;
     RECT  5.404 51.12 6.505 54.744 ;
     RECT  6.229 2.064 6.541 19.272 ;
     RECT  6.227 31.536 6.545 32.04 ;
     RECT  6.505 50.736 6.545 54.744 ;
     RECT  6.505 20.4 6.613 25.032 ;
     RECT  6.329 62.64 6.649 63.24 ;
     RECT  5.969 40.32 6.653 44.952 ;
     RECT  6.649 62.64 6.792 63.288 ;
     RECT  5.651 64.368 6.792 64.68 ;
     RECT  5.789 55.728 6.793 58.152 ;
     RECT  6.792 62.64 6.899 64.68 ;
     RECT  6.541 2.064 6.901 19.368 ;
     RECT  6.329 61.104 6.937 61.56 ;
     RECT  6.901 2.016 6.956 19.368 ;
     RECT  6.613 20.4 6.956 25.08 ;
     RECT  6.653 42.768 6.973 44.952 ;
     RECT  5.747 46.032 7.009 47.112 ;
     RECT  6.956 2.016 7.045 25.08 ;
     RECT  6.221 26.256 7.045 29.256 ;
     RECT  6.973 42.768 7.045 45.048 ;
     RECT  7.009 46.032 7.045 47.208 ;
     RECT  6.899 64.512 7.157 64.68 ;
     RECT  6.899 62.64 7.187 63.288 ;
     RECT  6.293 38.256 7.237 39.288 ;
     RECT  6.653 40.32 7.237 41.592 ;
     RECT  7.045 2.016 7.297 29.256 ;
     RECT  6.371 59.232 7.333 59.832 ;
     RECT  6.937 60.96 7.333 61.56 ;
     RECT  6.293 34.752 7.34 37.176 ;
     RECT  7.333 59.232 7.405 61.56 ;
     RECT  7.187 62.64 7.405 62.808 ;
     RECT  6.149 33.264 7.621 33.384 ;
     RECT  5.753 48.24 7.657 48.984 ;
     RECT  7.657 48.24 7.729 49.224 ;
     RECT  7.621 33.024 7.765 33.384 ;
     RECT  7.34 34.512 7.765 37.176 ;
     RECT  7.297 2.016 7.808 29.496 ;
     RECT  6.545 31.536 7.808 31.56 ;
     RECT  7.765 33.024 7.808 37.176 ;
     RECT  7.237 38.256 7.808 41.592 ;
     RECT  7.045 42.768 7.808 47.208 ;
     RECT  7.729 48.24 7.808 49.512 ;
     RECT  6.545 50.736 7.808 54.024 ;
     RECT  6.793 55.296 7.808 58.152 ;
     RECT  7.405 59.232 7.808 62.808 ;
     RECT  7.157 64.512 8.005 64.632 ;
     RECT  7.808 2.016 8.104 62.808 ;
     RECT  8.104 51.312 8.197 62.808 ;
     RECT  8.005 63.792 8.197 64.632 ;
     RECT  8.104 2.016 8.237 24.744 ;
     RECT  8.104 30.912 8.243 39.432 ;
     RECT  8.237 24.192 8.273 24.744 ;
     RECT  8.104 49.488 8.381 49.56 ;
     RECT  8.273 24.48 8.417 24.744 ;
     RECT  8.197 51.312 8.425 64.632 ;
     RECT  8.417 24.48 8.453 24.504 ;
     RECT  8.243 30.912 8.453 39.288 ;
     RECT  8.453 35.856 8.476 39.288 ;
     RECT  8.425 61.152 8.53 64.632 ;
     RECT  8.425 51.312 8.633 60.024 ;
     RECT  8.53 61.152 8.723 64.68 ;
     RECT  8.633 51.312 9.109 53.88 ;
     RECT  8.723 61.152 9.203 63.912 ;
     RECT  9.203 63.216 9.209 63.912 ;
     RECT  9.109 50.688 9.281 53.88 ;
     RECT  8.104 25.728 9.385 29.688 ;
     RECT  9.385 25.488 9.421 29.688 ;
     RECT  8.381 49.536 9.421 49.56 ;
     RECT  9.281 50.688 9.421 53.016 ;
     RECT  8.237 2.016 9.457 22.776 ;
     RECT  8.453 30.912 9.457 34.824 ;
     RECT  8.476 35.904 9.457 39.288 ;
     RECT  9.421 49.536 9.461 53.016 ;
     RECT  9.461 49.824 9.497 53.016 ;
     RECT  9.209 63.744 9.497 63.912 ;
     RECT  9.497 63.744 9.539 63.864 ;
     RECT  9.421 25.104 9.637 29.688 ;
     RECT  9.457 30.912 9.637 39.288 ;
     RECT  8.104 40.56 9.637 48.408 ;
     RECT  9.457 2.016 9.745 22.824 ;
     RECT  9.745 1.104 9.781 22.824 ;
     RECT  9.781 0.528 9.829 22.872 ;
     RECT  9.203 61.152 9.925 62.184 ;
     RECT  8.633 54.864 9.961 60.024 ;
     RECT  9.925 61.056 9.961 62.184 ;
     RECT  9.961 54.864 9.997 62.184 ;
     RECT  9.637 25.104 10.033 48.408 ;
     RECT  9.539 63.84 10.253 63.864 ;
     RECT  9.829 0.096 10.259 22.872 ;
     RECT  10.033 24.432 10.357 48.408 ;
     RECT  10.259 0.144 10.403 22.872 ;
     RECT  10.403 1.968 10.508 22.872 ;
     RECT  10.357 24.432 10.508 48.744 ;
     RECT  9.497 49.824 10.508 52.968 ;
     RECT  9.997 54.336 10.508 62.184 ;
     RECT  10.508 1.968 10.612 62.652 ;
     RECT  10.612 1.968 10.804 62.382 ;
     RECT  10.804 35.184 10.865 50.328 ;
     RECT  10.865 35.184 11.009 49.848 ;
     RECT  10.94 64.704 11.027 64.728 ;
     RECT  10.804 1.968 11.081 33.384 ;
     RECT  11.009 35.184 11.117 48.984 ;
     RECT  10.804 51.312 11.123 61.416 ;
     RECT  11.117 35.184 11.171 48.216 ;
     RECT  11.171 35.184 11.26 38.184 ;
     RECT  10.403 0.144 11.269 0.552 ;
     RECT  11.26 35.808 11.297 38.184 ;
     RECT  11.123 51.312 11.297 57.864 ;
     RECT  11.123 58.944 11.297 59.496 ;
     RECT  11.171 39.216 11.369 48.216 ;
     RECT  11.269 0.096 11.413 0.552 ;
     RECT  11.081 1.968 11.413 28.68 ;
     RECT  11.123 60.864 11.477 61.416 ;
     RECT  11.081 30.384 11.507 33.384 ;
     RECT  11.297 51.312 11.621 53.544 ;
     RECT  11.369 39.216 11.657 48.168 ;
     RECT  11.621 51.312 11.657 51.336 ;
     RECT  11.297 58.944 11.693 59.208 ;
     RECT  11.413 0.096 11.699 28.68 ;
     RECT  11.699 2.064 11.729 28.68 ;
     RECT  11.297 35.808 11.747 38.088 ;
     RECT  11.747 35.808 11.837 37.608 ;
     RECT  11.837 35.808 11.873 37.08 ;
     RECT  11.699 0.096 11.987 0.264 ;
     RECT  11.507 31.776 12.013 33.384 ;
     RECT  11.987 0.096 12.053 0.216 ;
     RECT  12.013 31.776 12.061 34.152 ;
     RECT  11.557 63.84 12.092 63.864 ;
     RECT  11.729 25.056 12.131 28.68 ;
     RECT  11.507 30.384 12.301 30.696 ;
     RECT  12.061 32.352 12.409 34.152 ;
     RECT  11.657 39.744 12.421 48.168 ;
     RECT  12.325 51.216 12.445 51.24 ;
     RECT  12.301 30.192 12.517 30.696 ;
     RECT  11.477 61.104 12.517 61.368 ;
     RECT  12.445 50.928 12.589 51.24 ;
     RECT  12.421 39.744 12.661 48.984 ;
     RECT  12.131 25.728 12.733 28.68 ;
     RECT  12.733 25.728 12.769 28.728 ;
     RECT  11.297 54.576 12.805 57.864 ;
     RECT  11.693 59.04 12.805 59.208 ;
     RECT  12.092 63.84 12.809 64.728 ;
     RECT  12.409 32.352 12.877 34.488 ;
     RECT  11.873 35.808 12.877 36.84 ;
     RECT  11.729 2.064 12.949 23.448 ;
     RECT  12.877 32.352 12.949 36.84 ;
     RECT  12.589 50.832 13.021 51.24 ;
     RECT  11.621 52.32 13.021 53.544 ;
     RECT  12.625 38.736 13.045 38.76 ;
     RECT  12.661 39.744 13.045 49.128 ;
     RECT  13.045 38.208 13.052 49.128 ;
     RECT  12.949 2.016 13.057 23.448 ;
     RECT  12.769 25.728 13.057 29.064 ;
     RECT  12.517 30.192 13.057 31.368 ;
     RECT  12.053 0.096 13.093 0.168 ;
     RECT  13.057 25.728 13.093 31.368 ;
     RECT  12.949 32.352 13.093 37.08 ;
     RECT  13.052 38.208 13.093 49.704 ;
     RECT  13.021 50.832 13.093 53.544 ;
     RECT  13.057 2.016 13.201 24.408 ;
     RECT  13.093 25.728 13.201 37.08 ;
     RECT  13.201 2.016 13.208 37.08 ;
     RECT  13.093 38.208 13.208 53.544 ;
     RECT  12.805 54.576 13.208 59.208 ;
     RECT  12.517 60.816 13.208 61.368 ;
     RECT  12.841 62.928 13.208 63.24 ;
     RECT  13.093 0.096 13.331 0.312 ;
     RECT  13.208 2.016 13.504 63.24 ;
     RECT  13.504 31.344 13.565 38.136 ;
     RECT  13.504 40.656 13.619 52.056 ;
     RECT  13.619 51.888 13.637 52.056 ;
     RECT  13.565 34.416 13.673 38.136 ;
     RECT  13.504 60.816 13.849 63.24 ;
     RECT  13.504 39.216 13.889 39.528 ;
     RECT  12.809 64.704 13.993 64.728 ;
     RECT  13.504 2.016 14.053 22.2 ;
     RECT  13.889 39.216 14.099 39.384 ;
     RECT  13.619 40.656 14.113 50.856 ;
     RECT  13.504 24.624 14.141 30.168 ;
     RECT  13.849 60.816 14.165 63.528 ;
     RECT  13.993 64.656 14.165 64.728 ;
     RECT  14.141 24.624 14.213 30.072 ;
     RECT  14.165 60.816 14.249 64.728 ;
     RECT  13.673 35.232 14.285 38.136 ;
     RECT  13.331 0.096 14.341 0.264 ;
     RECT  14.213 24.624 14.497 29.64 ;
     RECT  13.504 54.624 14.569 58.152 ;
     RECT  13.504 53.328 14.605 53.592 ;
     RECT  14.569 54.624 14.605 58.728 ;
     RECT  14.341 0.096 14.645 0.6 ;
     RECT  14.249 60.816 14.713 63.528 ;
     RECT  13.565 31.344 14.725 33.336 ;
     RECT  14.713 60.096 14.749 63.528 ;
     RECT  14.725 31.344 14.812 34.104 ;
     RECT  14.285 35.328 14.917 38.136 ;
     RECT  14.713 23.328 14.957 23.352 ;
     RECT  14.497 24.384 14.957 29.64 ;
     RECT  14.053 1.728 14.965 22.2 ;
     RECT  14.957 23.328 14.965 29.64 ;
     RECT  14.113 49.584 15.001 50.856 ;
     RECT  13.637 51.888 15.001 51.912 ;
     RECT  14.113 40.656 15.109 48.408 ;
     RECT  14.965 1.728 15.185 29.64 ;
     RECT  14.605 53.328 15.289 58.728 ;
     RECT  14.249 64.656 15.347 64.728 ;
     RECT  15.289 53.328 15.349 58.776 ;
     RECT  14.749 59.856 15.349 63.528 ;
     RECT  15.185 2.064 15.577 29.64 ;
     RECT  15.001 49.584 15.577 51.912 ;
     RECT  15.109 40.32 15.637 48.408 ;
     RECT  15.577 49.488 15.637 51.912 ;
     RECT  14.099 39.216 15.733 39.24 ;
     RECT  15.637 40.32 15.733 51.912 ;
     RECT  15.577 2.064 15.757 29.928 ;
     RECT  15.757 2.064 15.908 30.168 ;
     RECT  14.812 31.344 15.908 33.336 ;
     RECT  14.917 35.328 15.908 38.184 ;
     RECT  15.733 39.216 15.908 51.912 ;
     RECT  15.349 53.328 15.908 63.528 ;
     RECT  14.645 0.096 16.069 0.552 ;
     RECT  16.069 0.096 16.165 0.648 ;
     RECT  15.908 2.064 16.165 63.528 ;
     RECT  16.165 0.096 16.204 63.528 ;
     RECT  16.204 39.264 16.301 51.768 ;
     RECT  15.347 64.704 16.403 64.728 ;
     RECT  16.204 52.992 16.517 57.432 ;
     RECT  16.204 35.04 16.625 38.184 ;
     RECT  16.301 39.408 16.625 51.768 ;
     RECT  16.204 59.76 16.691 63.528 ;
     RECT  16.691 59.76 16.697 62.184 ;
     RECT  16.625 43.776 16.924 51.768 ;
     RECT  16.204 22.464 16.949 33.864 ;
     RECT  16.924 43.824 16.949 51.768 ;
     RECT  16.949 50.352 17.021 51.768 ;
     RECT  16.949 27.36 17.136 33.864 ;
     RECT  17.021 50.4 17.165 51.768 ;
     RECT  16.517 56.352 17.273 57.432 ;
     RECT  16.625 39.408 17.417 42.792 ;
     RECT  16.517 52.992 17.633 54.648 ;
     RECT  16.697 60.192 17.737 62.184 ;
     RECT  16.204 0.096 17.809 21.48 ;
     RECT  16.949 22.464 17.809 26.328 ;
     RECT  17.633 53.376 17.809 54.648 ;
     RECT  17.273 56.4 17.917 57.432 ;
     RECT  16.204 58.464 17.917 58.488 ;
     RECT  17.136 27.36 18.017 29.256 ;
     RECT  17.165 50.832 18.025 51.768 ;
     RECT  17.809 0.096 18.061 26.328 ;
     RECT  18.017 27.312 18.061 29.256 ;
     RECT  16.625 37.584 18.061 38.184 ;
     RECT  16.625 35.04 18.169 36.264 ;
     RECT  17.417 39.744 18.181 42.792 ;
     RECT  18.169 35.04 18.229 36.504 ;
     RECT  18.061 37.584 18.229 38.712 ;
     RECT  16.949 43.824 18.229 49.128 ;
     RECT  17.136 30.384 18.277 33.864 ;
     RECT  18.229 35.04 18.277 38.712 ;
     RECT  18.061 0.096 18.421 29.256 ;
     RECT  18.277 30.384 18.421 38.712 ;
     RECT  17.917 56.4 18.469 58.488 ;
     RECT  18.181 39.744 18.493 42.84 ;
     RECT  18.229 43.824 18.493 49.608 ;
     RECT  18.421 0.096 18.608 38.712 ;
     RECT  18.493 39.744 18.608 49.608 ;
     RECT  18.025 50.832 18.608 51.96 ;
     RECT  17.809 53.376 18.608 55.272 ;
     RECT  18.469 56.4 18.608 58.68 ;
     RECT  17.737 59.808 18.608 62.184 ;
     RECT  16.691 63.504 18.608 63.528 ;
     RECT  18.608 0.096 18.712 63.528 ;
     RECT  18.712 0.096 18.817 62.382 ;
     RECT  18.817 0.048 18.904 62.382 ;
     RECT  18.904 0.048 19.037 26.232 ;
     RECT  19.037 0.096 19.043 26.232 ;
     RECT  18.904 35.232 19.043 38.76 ;
     RECT  19.043 0.096 19.091 23.304 ;
     RECT  18.904 49.44 19.091 51.96 ;
     RECT  19.043 24.48 19.181 26.232 ;
     RECT  18.904 53.28 19.181 61.656 ;
     RECT  19.091 0.096 19.283 0.216 ;
     RECT  19.283 0.192 19.331 0.216 ;
     RECT  19.181 53.28 19.361 59.64 ;
     RECT  18.712 63.504 19.667 63.528 ;
     RECT  19.091 51.168 19.933 51.96 ;
     RECT  19.361 53.28 19.933 57.624 ;
     RECT  19.181 25.104 19.957 26.232 ;
     RECT  18.904 27.6 19.957 33.624 ;
     RECT  18.904 40.464 19.957 47.688 ;
     RECT  19.091 1.392 20.077 23.304 ;
     RECT  20.077 1.392 20.185 23.4 ;
     RECT  19.957 40.464 20.185 47.88 ;
     RECT  19.181 60.624 20.185 61.656 ;
     RECT  19.361 58.656 20.225 59.64 ;
     RECT  19.933 51.168 20.261 57.624 ;
     RECT  20.185 1.392 20.265 23.832 ;
     RECT  19.957 25.104 20.265 33.624 ;
     RECT  20.261 54.576 20.485 57.624 ;
     RECT  20.225 58.656 20.485 59.544 ;
     RECT  19.043 38.16 20.629 38.76 ;
     RECT  20.185 39.888 20.629 47.88 ;
     RECT  19.043 35.232 20.689 37.08 ;
     RECT  20.629 38.16 20.689 47.88 ;
     RECT  19.091 49.44 20.876 50.04 ;
     RECT  20.689 35.232 21.013 47.88 ;
     RECT  20.876 49.008 21.013 50.04 ;
     RECT  21.013 35.232 21.061 50.04 ;
     RECT  21.061 35.184 21.085 50.04 ;
     RECT  20.261 51.168 21.085 53.544 ;
     RECT  20.185 60.624 21.085 61.944 ;
     RECT  21.085 35.184 21.109 53.544 ;
     RECT  20.265 1.392 21.308 33.624 ;
     RECT  21.109 35.088 21.308 53.544 ;
     RECT  20.485 54.576 21.308 59.544 ;
     RECT  21.085 60.624 21.308 62.28 ;
     RECT  21.308 1.392 21.412 62.652 ;
     RECT  21.412 1.392 21.604 62.382 ;
     RECT  21.604 1.392 21.809 27.96 ;
     RECT  21.604 60.624 21.809 61.224 ;
     RECT  21.809 5.616 21.881 27.96 ;
     RECT  21.604 51.888 21.989 58.248 ;
     RECT  21.604 28.944 22.025 35.88 ;
     RECT  21.881 5.616 22.169 27.192 ;
     RECT  21.809 1.392 22.565 4.584 ;
     RECT  21.604 48.768 22.597 48.792 ;
     RECT  21.604 49.776 22.597 50.664 ;
     RECT  22.025 28.944 22.643 31.416 ;
     RECT  21.841 63.888 22.645 63.912 ;
     RECT  22.645 63.84 22.669 63.912 ;
     RECT  22.597 48.768 22.673 50.664 ;
     RECT  21.604 37.008 22.705 40.2 ;
     RECT  21.604 41.184 22.705 47.736 ;
     RECT  22.643 28.944 22.741 29.16 ;
     RECT  22.565 2.688 22.745 4.584 ;
     RECT  22.745 2.832 22.789 4.584 ;
     RECT  22.169 5.616 22.789 15.048 ;
     RECT  22.669 63.84 22.789 64.488 ;
     RECT  22.169 16.224 22.817 27.192 ;
     RECT  22.025 32.448 22.849 35.88 ;
     RECT  22.705 37.008 22.849 47.736 ;
     RECT  22.789 2.832 22.853 15.048 ;
     RECT  22.849 32.448 22.853 47.736 ;
     RECT  22.853 32.448 22.883 43.656 ;
     RECT  21.989 52.032 22.885 58.248 ;
     RECT  22.597 59.232 22.885 59.256 ;
     RECT  22.789 63.84 22.885 64.536 ;
     RECT  22.853 12.864 22.997 15.048 ;
     RECT  22.853 2.832 23.02 11.784 ;
     RECT  21.604 62.256 23.077 62.28 ;
     RECT  22.817 22.8 23.137 27.192 ;
     RECT  23.137 22.8 23.173 27.384 ;
     RECT  22.741 28.608 23.173 29.16 ;
     RECT  22.673 49.488 23.245 50.664 ;
     RECT  22.885 52.032 23.245 59.256 ;
     RECT  23.077 62.256 23.245 62.712 ;
     RECT  22.885 63.84 23.32 64.632 ;
     RECT  23.245 49.488 23.365 59.256 ;
     RECT  21.809 60.624 23.365 61.08 ;
     RECT  22.643 30.24 23.557 31.416 ;
     RECT  22.883 32.448 23.557 34.872 ;
     RECT  22.997 13.008 23.569 15.048 ;
     RECT  22.817 16.224 23.569 21.768 ;
     RECT  23.365 49.488 23.677 61.08 ;
     RECT  22.565 1.392 23.789 1.416 ;
     RECT  23.173 22.8 23.821 29.16 ;
     RECT  22.853 44.64 23.857 47.736 ;
     RECT  23.245 62.16 23.9 62.712 ;
     RECT  23.02 2.832 24.008 11.496 ;
     RECT  23.569 13.008 24.008 21.768 ;
     RECT  23.821 22.8 24.008 29.256 ;
     RECT  23.557 30.24 24.008 34.872 ;
     RECT  22.883 35.856 24.008 43.656 ;
     RECT  23.857 44.64 24.008 47.976 ;
     RECT  23.677 49.008 24.008 61.08 ;
     RECT  23.9 62.16 24.008 62.808 ;
     RECT  24.008 2.148 24.037 62.808 ;
     RECT  23.32 63.84 24.037 64.68 ;
     RECT  24.037 2.148 24.112 64.68 ;
     RECT  24.112 2.418 24.304 64.68 ;
     RECT  24.304 14.448 24.515 25.8 ;
     RECT  24.304 49.008 24.545 64.68 ;
     RECT  24.304 2.832 24.652 8.712 ;
     RECT  24.304 9.696 24.689 9.72 ;
     RECT  24.515 18 24.707 25.8 ;
     RECT  24.707 18 24.725 18.744 ;
     RECT  24.545 53.088 24.797 64.68 ;
     RECT  24.545 49.008 24.805 52.056 ;
     RECT  24.304 28.656 24.833 47.976 ;
     RECT  24.707 19.824 24.899 25.8 ;
     RECT  24.899 23.904 24.905 25.8 ;
     RECT  24.905 23.904 24.941 24.264 ;
     RECT  24.805 51.456 24.941 52.056 ;
     RECT  24.797 63.168 24.977 64.68 ;
     RECT  24.833 28.656 25.049 43.608 ;
     RECT  24.905 25.344 25.085 25.8 ;
     RECT  25.049 28.992 25.121 43.608 ;
     RECT  24.833 45.12 25.121 47.976 ;
     RECT  24.805 49.008 25.157 50.328 ;
     RECT  25.121 35.664 25.228 43.608 ;
     RECT  25.121 47.712 25.229 47.976 ;
     RECT  24.797 53.088 25.229 62.184 ;
     RECT  24.977 63.84 25.331 64.68 ;
     RECT  25.229 54.432 25.337 62.184 ;
     RECT  24.304 10.896 25.405 13.416 ;
     RECT  24.515 14.448 25.405 16.872 ;
     RECT  24.304 26.784 25.405 27.672 ;
     RECT  25.228 36.048 25.445 43.608 ;
     RECT  25.157 49.2 25.445 50.328 ;
     RECT  25.405 10.896 25.513 16.872 ;
     RECT  25.405 26.784 25.513 27.912 ;
     RECT  25.121 32.784 25.667 34.536 ;
     RECT  25.405 9.744 25.669 9.768 ;
     RECT  25.513 10.848 25.669 16.872 ;
     RECT  25.667 34.32 25.697 34.536 ;
     RECT  25.445 36.912 25.697 43.608 ;
     RECT  24.652 3.312 25.765 8.712 ;
     RECT  25.669 9.744 25.765 16.872 ;
     RECT  24.725 18.72 25.765 18.744 ;
     RECT  25.331 64.608 25.841 64.68 ;
     RECT  25.765 3.12 25.861 8.712 ;
     RECT  25.765 9.744 25.861 17.064 ;
     RECT  24.899 19.824 25.873 22.728 ;
     RECT  24.941 51.456 25.909 51.48 ;
     RECT  25.841 64.608 25.955 64.632 ;
     RECT  25.861 3.12 25.981 17.064 ;
     RECT  25.765 18.24 25.981 18.744 ;
     RECT  25.873 19.824 25.981 23.064 ;
     RECT  24.941 24.096 25.981 24.264 ;
     RECT  25.981 3.12 26.005 18.744 ;
     RECT  25.981 19.824 26.005 24.264 ;
     RECT  26.005 3.12 26.017 24.264 ;
     RECT  25.085 25.344 26.017 25.368 ;
     RECT  25.513 26.352 26.06 27.912 ;
     RECT  25.121 28.992 26.06 31.8 ;
     RECT  26.017 3.12 26.101 25.368 ;
     RECT  26.06 26.352 26.101 31.8 ;
     RECT  26.101 3.12 26.125 31.8 ;
     RECT  25.445 49.2 26.125 50.04 ;
     RECT  25.909 51.12 26.125 51.48 ;
     RECT  26.125 49.152 26.161 50.04 ;
     RECT  25.229 47.712 26.204 47.88 ;
     RECT  26.161 49.056 26.204 50.04 ;
     RECT  26.125 2.544 26.269 31.8 ;
     RECT  25.667 32.784 26.269 33.144 ;
     RECT  25.697 36.912 26.485 37.08 ;
     RECT  25.121 45.12 26.485 46.152 ;
     RECT  25.229 53.088 26.485 53.4 ;
     RECT  25.337 54.432 26.485 61.608 ;
     RECT  26.485 36.528 26.581 37.08 ;
     RECT  25.697 34.32 26.665 34.488 ;
     RECT  26.125 51.12 26.665 51.624 ;
     RECT  26.581 36.096 26.701 37.08 ;
     RECT  26.269 2.544 26.708 33.144 ;
     RECT  26.665 34.176 26.708 34.488 ;
     RECT  26.701 36 26.708 37.08 ;
     RECT  25.697 38.16 26.708 43.608 ;
     RECT  26.485 44.928 26.708 46.152 ;
     RECT  26.204 47.712 26.708 50.04 ;
     RECT  26.665 51.12 26.708 51.96 ;
     RECT  26.485 53.088 26.708 61.608 ;
     RECT  25.868 62.592 26.708 62.616 ;
     RECT  26.708 2.148 26.812 62.652 ;
     RECT  26.812 2.418 27.004 62.382 ;
     RECT  27.004 36.528 27.065 46.824 ;
     RECT  27.065 36.912 27.155 46.824 ;
     RECT  27.004 51.12 27.155 57.048 ;
     RECT  27.155 36.912 27.299 46.104 ;
     RECT  27.004 10.752 27.317 29.64 ;
     RECT  27.299 36.912 27.677 45 ;
     RECT  27.644 64.704 27.73 64.728 ;
     RECT  27.677 42.192 27.749 45 ;
     RECT  27.004 2.418 27.889 9.624 ;
     RECT  27.155 51.264 27.965 55.416 ;
     RECT  27.004 47.904 27.997 50.04 ;
     RECT  27.889 2.304 28.033 9.624 ;
     RECT  27.317 10.752 28.033 13.416 ;
     RECT  27.004 58.032 28.076 60.888 ;
     RECT  27.004 61.92 28.076 61.944 ;
     RECT  27.677 36.912 28.109 41.112 ;
     RECT  28.076 58.032 28.163 61.944 ;
     RECT  27.299 45.984 28.213 46.104 ;
     RECT  28.033 2.304 28.261 13.416 ;
     RECT  28.213 45.984 28.261 46.344 ;
     RECT  27.997 47.328 28.261 50.04 ;
     RECT  28.163 58.032 28.289 60.888 ;
     RECT  27.73 64.656 28.309 64.728 ;
     RECT  27.004 30.672 28.321 35.304 ;
     RECT  28.261 45.984 28.348 50.04 ;
     RECT  28.348 47.328 28.393 50.04 ;
     RECT  27.965 51.264 28.393 51.288 ;
     RECT  27.317 14.448 28.429 29.64 ;
     RECT  28.321 30.672 28.429 35.544 ;
     RECT  28.163 61.92 28.429 61.944 ;
     RECT  27.749 42.24 28.46 45 ;
     RECT  28.348 45.984 28.46 46.344 ;
     RECT  28.309 63.888 28.693 64.728 ;
     RECT  27.155 56.64 28.789 57.048 ;
     RECT  28.289 58.032 28.789 60.84 ;
     RECT  28.109 39.744 28.969 41.112 ;
     RECT  28.46 42.24 28.969 46.344 ;
     RECT  28.261 2.256 28.997 13.416 ;
     RECT  28.429 14.448 28.997 35.544 ;
     RECT  28.693 63.84 29.027 64.728 ;
     RECT  28.997 2.256 29.221 35.544 ;
     RECT  27.965 52.272 29.269 55.416 ;
     RECT  28.789 56.64 29.269 60.84 ;
     RECT  29.221 1.728 29.305 35.544 ;
     RECT  29.305 1.776 29.329 35.544 ;
     RECT  28.109 36.912 29.329 38.664 ;
     RECT  29.027 63.84 29.329 63.912 ;
     RECT  29.105 0.096 29.365 0.12 ;
     RECT  29.329 1.776 29.408 38.664 ;
     RECT  28.969 39.744 29.408 46.344 ;
     RECT  28.393 47.328 29.408 51.288 ;
     RECT  29.269 52.272 29.408 60.84 ;
     RECT  28.429 61.92 29.408 62.04 ;
     RECT  29.408 1.776 29.512 62.652 ;
     RECT  29.512 1.776 29.651 62.382 ;
     RECT  29.329 63.792 29.657 63.912 ;
     RECT  29.651 2.256 29.704 62.382 ;
     RECT  29.704 37.968 29.843 44.472 ;
     RECT  29.657 63.792 29.843 63.816 ;
     RECT  29.704 2.256 29.873 18.456 ;
     RECT  29.704 56.256 29.909 59.976 ;
     RECT  29.704 51.168 30.017 55.176 ;
     RECT  29.704 23.136 30.035 31.464 ;
     RECT  30.017 53.376 30.125 55.176 ;
     RECT  30.125 53.376 30.161 54.984 ;
     RECT  29.873 10.848 30.197 18.456 ;
     RECT  29.909 56.448 30.227 59.976 ;
     RECT  30.035 23.136 30.305 26.616 ;
     RECT  30.197 10.848 30.323 18.12 ;
     RECT  29.843 37.968 30.371 39.048 ;
     RECT  29.843 40.464 30.485 44.472 ;
     RECT  29.704 45.648 30.611 49.512 ;
     RECT  29.873 2.256 30.629 9.864 ;
     RECT  30.611 47.28 30.701 49.512 ;
     RECT  29.704 19.584 30.707 22.152 ;
     RECT  30.629 4.944 30.737 9.864 ;
     RECT  30.629 2.256 30.809 3.72 ;
     RECT  30.707 19.584 30.841 22.056 ;
     RECT  30.809 2.256 30.881 3.576 ;
     RECT  29.704 32.448 30.899 36.984 ;
     RECT  30.841 19.488 30.953 22.056 ;
     RECT  30.485 40.896 30.997 44.472 ;
     RECT  30.611 45.648 30.997 46.104 ;
     RECT  30.035 27.6 31.057 31.464 ;
     RECT  30.899 32.448 31.057 35.496 ;
     RECT  30.305 23.136 31.061 24.408 ;
     RECT  30.161 53.376 31.097 54.6 ;
     RECT  30.227 56.448 31.189 57.096 ;
     RECT  30.305 25.44 31.237 26.616 ;
     RECT  31.057 27.6 31.237 35.496 ;
     RECT  30.017 51.168 31.285 52.296 ;
     RECT  31.097 53.52 31.285 54.6 ;
     RECT  31.189 55.728 31.285 57.096 ;
     RECT  29.704 61.92 31.285 62.184 ;
     RECT  31.285 53.52 31.309 57.096 ;
     RECT  30.227 58.128 31.309 59.976 ;
     RECT  30.953 19.488 31.345 21.864 ;
     RECT  30.323 11.136 31.381 18.12 ;
     RECT  30.737 5.232 31.429 9.864 ;
     RECT  31.381 11.136 31.429 18.216 ;
     RECT  30.701 47.712 31.561 49.512 ;
     RECT  31.429 5.232 31.669 18.216 ;
     RECT  31.345 19.392 31.669 21.864 ;
     RECT  30.371 38.16 31.669 39.048 ;
     RECT  30.997 64.656 31.669 64.68 ;
     RECT  31.669 5.232 31.717 21.864 ;
     RECT  31.561 47.712 31.777 49.944 ;
     RECT  30.899 36.48 31.861 36.984 ;
     RECT  31.669 38.16 31.861 39.912 ;
     RECT  30.997 40.896 31.885 46.104 ;
     RECT  31.237 25.44 31.909 35.496 ;
     RECT  31.861 36.48 31.909 39.912 ;
     RECT  30.881 2.832 31.921 3.576 ;
     RECT  31.717 4.56 31.921 21.864 ;
     RECT  31.885 40.896 31.957 46.296 ;
     RECT  31.777 47.328 31.957 49.944 ;
     RECT  31.285 51.12 31.957 52.296 ;
     RECT  29.365 0.096 31.997 0.552 ;
     RECT  31.061 23.136 32.029 24.36 ;
     RECT  31.909 25.44 32.029 39.912 ;
     RECT  31.921 2.832 32.108 21.864 ;
     RECT  32.029 23.136 32.108 39.912 ;
     RECT  31.957 40.896 32.108 49.944 ;
     RECT  31.957 50.928 32.108 52.296 ;
     RECT  31.309 53.52 32.108 59.976 ;
     RECT  31.285 61.2 32.108 62.184 ;
     RECT  30.373 63.504 32.108 63.528 ;
     RECT  32.108 2.148 32.212 63.528 ;
     RECT  32.212 2.418 32.404 62.472 ;
     RECT  32.404 45.696 32.501 59.544 ;
     RECT  32.501 45.696 32.537 57.336 ;
     RECT  32.212 63.504 32.605 63.528 ;
     RECT  31.669 64.656 32.605 64.728 ;
     RECT  31.997 0.096 32.609 0.504 ;
     RECT  32.537 56.544 33.011 57.336 ;
     RECT  33.011 56.976 33.077 57.336 ;
     RECT  32.404 2.832 33.113 44.472 ;
     RECT  32.609 0.096 33.149 0.456 ;
     RECT  33.149 0.144 33.257 0.456 ;
     RECT  33.257 0.144 33.329 0.36 ;
     RECT  33.113 2.832 33.397 4.296 ;
     RECT  33.329 0.144 33.401 0.168 ;
     RECT  32.404 61.344 33.433 62.472 ;
     RECT  33.433 61.104 33.437 62.472 ;
     RECT  33.113 18.432 33.473 38.136 ;
     RECT  32.537 45.696 33.473 55.416 ;
     RECT  33.473 45.696 33.491 51.144 ;
     RECT  33.473 52.224 33.545 55.416 ;
     RECT  33.113 39.408 33.587 44.472 ;
     RECT  33.587 39.408 33.617 44.232 ;
     RECT  33.491 45.696 33.685 49.608 ;
     RECT  33.545 52.224 33.725 52.248 ;
     RECT  33.077 57.12 33.761 57.336 ;
     RECT  33.545 53.328 33.98 55.416 ;
     RECT  33.98 53.328 33.981 55.464 ;
     RECT  32.501 58.512 34.009 59.544 ;
     RECT  33.437 61.104 34.009 62.184 ;
     RECT  33.685 45.456 34.117 49.608 ;
     RECT  33.473 34.368 34.124 38.136 ;
     RECT  34.124 34.368 34.165 38.184 ;
     RECT  33.617 39.408 34.165 44.088 ;
     RECT  33.397 2.256 34.225 4.296 ;
     RECT  34.225 2.256 34.477 4.392 ;
     RECT  33.113 5.472 34.477 17.208 ;
     RECT  34.165 34.368 34.508 44.088 ;
     RECT  34.009 58.512 34.513 62.184 ;
     RECT  34.513 58.224 34.621 62.232 ;
     RECT  32.605 63.504 34.621 64.728 ;
     RECT  33.473 18.432 34.729 33.144 ;
     RECT  34.508 34.128 34.729 44.088 ;
     RECT  34.729 18.432 34.765 44.088 ;
     RECT  34.117 45.264 34.765 49.608 ;
     RECT  33.491 50.928 34.765 51.144 ;
     RECT  34.621 58.224 34.765 64.728 ;
     RECT  34.477 2.256 34.808 17.208 ;
     RECT  34.765 18.432 34.808 44.136 ;
     RECT  34.765 45.264 34.808 51.144 ;
     RECT  33.981 53.328 34.808 55.992 ;
     RECT  33.761 57.12 34.808 57.144 ;
     RECT  34.765 58.128 34.808 64.728 ;
     RECT  34.808 2.148 34.912 64.728 ;
     RECT  34.912 2.256 35.021 64.728 ;
     RECT  35.021 2.256 35.104 64.68 ;
     RECT  35.104 55.152 35.237 64.68 ;
     RECT  35.104 2.256 35.267 37.992 ;
     RECT  35.237 61.92 35.315 64.68 ;
     RECT  35.237 55.152 35.363 60.84 ;
     RECT  35.363 55.152 35.381 59.544 ;
     RECT  35.267 2.256 35.404 18.456 ;
     RECT  35.363 60.816 35.417 60.84 ;
     RECT  35.404 2.256 35.452 3.384 ;
     RECT  35.267 19.488 35.453 37.992 ;
     RECT  35.452 2.592 35.555 3.384 ;
     RECT  35.381 56.736 35.603 59.544 ;
     RECT  35.315 64.32 35.795 64.68 ;
     RECT  35.315 61.92 35.849 63.24 ;
     RECT  35.849 63.216 35.885 63.24 ;
     RECT  35.161 0.048 35.921 0.072 ;
     RECT  35.104 39.072 36.109 40.872 ;
     RECT  35.453 29.616 36.133 37.992 ;
     RECT  36.109 39.072 36.133 39.816 ;
     RECT  35.603 56.736 36.137 57.624 ;
     RECT  35.795 64.32 36.245 64.632 ;
     RECT  35.603 58.608 36.353 59.544 ;
     RECT  36.109 40.848 36.373 40.872 ;
     RECT  35.104 42 36.385 54.072 ;
     RECT  35.849 61.92 36.419 62.232 ;
     RECT  36.373 40.848 36.457 41.016 ;
     RECT  36.385 42 36.457 54.168 ;
     RECT  36.137 56.736 36.457 57.432 ;
     RECT  36.133 29.616 36.461 39.816 ;
     RECT  36.457 40.848 36.467 54.168 ;
     RECT  35.404 4.848 36.469 18.456 ;
     RECT  35.555 2.976 36.529 3.384 ;
     RECT  36.469 4.512 36.565 18.456 ;
     RECT  35.453 19.488 36.565 28.44 ;
     RECT  36.529 2.352 36.613 3.384 ;
     RECT  36.565 4.512 36.613 28.44 ;
     RECT  36.613 2.352 36.673 28.44 ;
     RECT  35.381 55.152 37.033 55.272 ;
     RECT  36.457 56.544 37.033 57.432 ;
     RECT  36.467 40.944 37.105 54.168 ;
     RECT  37.033 55.152 37.105 57.432 ;
     RECT  36.245 64.32 37.109 64.536 ;
     RECT  36.461 29.808 37.213 39.816 ;
     RECT  37.105 1.152 37.217 1.176 ;
     RECT  37.213 29.808 37.249 39.864 ;
     RECT  37.105 40.944 37.321 57.432 ;
     RECT  36.419 61.92 37.465 62.184 ;
     RECT  36.673 2.352 37.508 28.536 ;
     RECT  37.249 29.808 37.508 39.96 ;
     RECT  37.321 40.944 37.508 58.152 ;
     RECT  36.353 59.232 37.508 59.448 ;
     RECT  37.465 61.68 37.508 62.184 ;
     RECT  37.508 2.148 37.612 62.652 ;
     RECT  37.612 2.418 37.804 62.382 ;
     RECT  37.804 28.416 37.865 45.384 ;
     RECT  37.804 54.096 37.865 57 ;
     RECT  37.865 54.624 37.901 57 ;
     RECT  37.865 35.856 37.955 45.384 ;
     RECT  37.955 35.856 38.051 39.864 ;
     RECT  37.955 40.944 38.153 45.384 ;
     RECT  37.804 2.688 38.333 27.288 ;
     RECT  38.153 41.376 38.333 45.384 ;
     RECT  37.865 28.416 38.387 34.728 ;
     RECT  37.109 64.32 38.533 64.344 ;
     RECT  37.804 46.512 38.549 53.112 ;
     RECT  38.051 35.856 38.621 39.816 ;
     RECT  38.549 46.512 38.797 46.536 ;
     RECT  38.533 64.32 38.801 64.728 ;
     RECT  38.621 36 38.867 39.816 ;
     RECT  38.333 41.376 38.867 44.616 ;
     RECT  37.901 55.728 38.869 57 ;
     RECT  38.869 55.68 38.909 57 ;
     RECT  38.333 3.36 38.941 27.288 ;
     RECT  37.804 58.224 38.941 60.696 ;
     RECT  37.804 61.68 38.941 62.184 ;
     RECT  38.549 47.856 38.945 53.112 ;
     RECT  38.909 56.976 38.972 57 ;
     RECT  38.941 58.224 38.972 62.184 ;
     RECT  38.972 56.976 39.017 62.184 ;
     RECT  38.945 49.584 39.059 53.112 ;
     RECT  39.017 57.024 39.059 62.184 ;
     RECT  38.801 64.32 39.109 64.584 ;
     RECT  38.905 1.152 39.125 1.176 ;
     RECT  39.059 50.64 39.205 53.112 ;
     RECT  37.901 54.624 39.205 54.648 ;
     RECT  39.205 50.64 39.265 54.648 ;
     RECT  39.109 63.888 39.301 64.584 ;
     RECT  38.797 2.352 39.308 2.376 ;
     RECT  38.941 3.36 39.308 27.384 ;
     RECT  38.387 32.496 39.337 34.728 ;
     RECT  39.308 2.352 39.397 27.384 ;
     RECT  38.387 28.416 39.397 31.368 ;
     RECT  38.797 46.128 39.661 46.536 ;
     RECT  39.481 0.096 39.697 0.12 ;
     RECT  39.337 32.496 39.697 34.824 ;
     RECT  38.867 36 39.697 39.48 ;
     RECT  39.697 0.096 39.809 0.168 ;
     RECT  39.697 32.496 39.829 39.48 ;
     RECT  39.397 2.352 39.877 31.368 ;
     RECT  38.867 41.376 39.877 44.472 ;
     RECT  39.265 50.64 39.877 54.696 ;
     RECT  38.909 55.68 39.877 55.704 ;
     RECT  39.661 45.552 40.093 46.536 ;
     RECT  38.945 47.856 40.093 48.408 ;
     RECT  39.877 2.256 40.208 31.368 ;
     RECT  39.829 32.496 40.208 39.528 ;
     RECT  39.877 40.944 40.208 44.472 ;
     RECT  40.093 45.552 40.208 48.408 ;
     RECT  39.059 49.584 40.208 49.608 ;
     RECT  39.877 50.64 40.208 55.704 ;
     RECT  39.059 57.024 40.208 57.048 ;
     RECT  39.059 58.128 40.208 62.184 ;
     RECT  39.301 63.264 40.208 64.584 ;
     RECT  40.208 2.148 40.312 64.584 ;
     RECT  40.312 2.256 40.345 64.584 ;
     RECT  40.345 2.256 40.504 64.728 ;
     RECT  40.504 53.904 40.745 59.352 ;
     RECT  40.504 26.784 40.817 52.296 ;
     RECT  40.504 60.672 40.817 61.656 ;
     RECT  40.745 53.904 40.889 59.304 ;
     RECT  40.889 53.904 40.931 59.256 ;
     RECT  40.931 53.904 40.997 59.208 ;
     RECT  40.997 53.904 41.033 58.152 ;
     RECT  41.033 53.904 41.069 56.472 ;
     RECT  40.504 3.648 41.105 25.752 ;
     RECT  41.069 54.096 41.141 56.472 ;
     RECT  40.817 26.784 41.213 52.008 ;
     RECT  40.504 2.256 41.249 2.28 ;
     RECT  41.141 54.624 41.249 56.472 ;
     RECT  40.817 60.912 41.285 61.656 ;
     RECT  41.213 26.784 41.393 46.536 ;
     RECT  41.105 3.648 41.497 25.464 ;
     RECT  41.393 26.784 41.533 33.624 ;
     RECT  41.497 2.832 41.581 25.464 ;
     RECT  41.393 34.704 41.717 46.536 ;
     RECT  40.997 59.184 41.747 59.208 ;
     RECT  41.533 26.592 41.789 33.624 ;
     RECT  41.249 54.624 41.789 55.272 ;
     RECT  41.581 3.312 41.795 25.464 ;
     RECT  41.213 47.856 41.929 52.008 ;
     RECT  41.929 47.856 41.941 52.728 ;
     RECT  41.795 25.056 42.073 25.464 ;
     RECT  42.073 25.056 42.217 25.608 ;
     RECT  41.789 26.592 42.217 29.832 ;
     RECT  41.795 3.312 42.565 23.976 ;
     RECT  41.285 60.912 42.565 61.608 ;
     RECT  41.033 57.552 42.649 58.152 ;
     RECT  41.941 47.856 42.685 52.968 ;
     RECT  42.565 60.144 42.709 61.608 ;
     RECT  40.504 62.928 42.709 64.728 ;
     RECT  41.789 30.816 42.757 33.624 ;
     RECT  41.717 34.704 42.757 43.896 ;
     RECT  41.717 44.928 42.757 46.536 ;
     RECT  42.685 47.856 42.793 53.064 ;
     RECT  42.565 2.592 42.908 23.976 ;
     RECT  42.217 25.056 42.908 29.832 ;
     RECT  42.757 30.816 42.908 46.536 ;
     RECT  42.793 47.664 42.908 53.064 ;
     RECT  41.789 54.624 42.908 55.128 ;
     RECT  41.249 56.256 42.908 56.472 ;
     RECT  42.649 57.552 42.908 58.2 ;
     RECT  42.709 60.144 42.908 64.728 ;
     RECT  42.908 2.148 43.012 64.728 ;
     RECT  43.012 2.208 43.204 64.728 ;
     RECT  43.204 2.208 43.265 38.952 ;
     RECT  43.265 2.208 43.331 29.64 ;
     RECT  43.204 40.032 43.331 47.592 ;
     RECT  43.331 40.032 43.589 45 ;
     RECT  43.204 57.456 43.715 59.64 ;
     RECT  43.204 60.672 43.955 64.728 ;
     RECT  43.955 60.672 44.057 64.68 ;
     RECT  43.204 49.056 44.188 56.328 ;
     RECT  43.715 58.128 44.236 59.64 ;
     RECT  44.188 49.056 44.269 54.744 ;
     RECT  44.057 62.928 44.291 64.68 ;
     RECT  43.331 46.512 44.305 47.592 ;
     RECT  44.269 48.96 44.341 54.744 ;
     RECT  44.236 58.128 44.381 59.304 ;
     RECT  40.345 0.048 44.521 0.072 ;
     RECT  44.291 63.792 44.579 64.68 ;
     RECT  43.331 2.592 44.593 29.64 ;
     RECT  44.305 46.464 44.597 47.592 ;
     RECT  43.265 30.672 44.665 38.952 ;
     RECT  43.589 40.032 44.665 44.952 ;
     RECT  44.665 30.672 44.677 44.952 ;
     RECT  44.597 46.464 44.693 47.16 ;
     RECT  44.521 0.048 44.773 0.504 ;
     RECT  44.677 30.672 44.773 45.048 ;
     RECT  44.693 46.176 44.773 47.16 ;
     RECT  44.593 2.448 44.809 29.64 ;
     RECT  44.773 30.672 44.809 47.16 ;
     RECT  44.579 63.792 44.915 63.816 ;
     RECT  44.773 0.048 44.917 0.552 ;
     RECT  44.917 0.048 45.061 0.6 ;
     RECT  44.809 2.448 45.061 47.16 ;
     RECT  44.188 55.776 45.457 56.328 ;
     RECT  44.381 58.176 45.457 59.304 ;
     RECT  45.061 2.256 45.601 47.16 ;
     RECT  44.341 48.672 45.601 54.744 ;
     RECT  45.457 55.776 45.601 59.304 ;
     RECT  44.057 60.672 45.601 61.656 ;
     RECT  45.601 2.256 45.608 54.744 ;
     RECT  45.601 55.776 45.608 61.656 ;
     RECT  45.608 2.148 45.712 62.652 ;
     RECT  45.712 2.256 45.904 62.424 ;
     RECT  45.904 2.256 45.965 49.032 ;
     RECT  45.904 58.176 46.019 62.424 ;
     RECT  45.965 2.256 46.109 48.792 ;
     RECT  46.019 60 46.217 62.424 ;
     RECT  46.217 60 46.547 61.032 ;
     RECT  46.109 2.544 46.649 48.792 ;
     RECT  45.904 51.936 46.685 57.048 ;
     RECT  46.019 58.176 46.793 58.824 ;
     RECT  46.685 53.568 46.901 57.048 ;
     RECT  46.649 6.24 46.933 48.792 ;
     RECT  45.904 50.016 46.933 50.952 ;
     RECT  46.901 53.568 46.937 56.28 ;
     RECT  46.933 6.24 46.979 50.952 ;
     RECT  46.979 6.624 47.045 50.952 ;
     RECT  47.045 22.752 47.113 50.952 ;
     RECT  46.685 51.936 47.113 52.44 ;
     RECT  46.649 2.544 47.153 4.92 ;
     RECT  46.793 58.368 47.473 58.824 ;
     RECT  46.547 60.912 47.473 61.032 ;
     RECT  47.473 58.368 47.66 59.736 ;
     RECT  47.473 60.912 47.66 61.176 ;
     RECT  45.061 0.048 47.801 0.84 ;
     RECT  47.113 22.752 47.869 52.44 ;
     RECT  46.937 53.568 47.869 53.592 ;
     RECT  47.701 5.616 48.085 5.64 ;
     RECT  47.045 6.624 48.085 21.672 ;
     RECT  48.085 5.616 48.133 21.672 ;
     RECT  47.869 22.752 48.133 53.592 ;
     RECT  48.133 5.616 48.181 53.592 ;
     RECT  46.937 54.72 48.181 56.28 ;
     RECT  47.66 58.368 48.181 61.176 ;
     RECT  47.153 2.544 48.265 4.584 ;
     RECT  48.181 5.616 48.265 56.28 ;
     RECT  47.801 0.096 48.275 0.84 ;
     RECT  48.265 2.544 48.308 56.28 ;
     RECT  48.181 57.456 48.308 61.176 ;
     RECT  46.217 62.4 48.308 62.424 ;
     RECT  48.308 2.148 48.412 62.652 ;
     RECT  48.412 2.256 48.604 62.382 ;
     RECT  48.604 50.592 48.665 54.168 ;
     RECT  48.604 59.184 48.665 59.832 ;
     RECT  48.604 32.976 48.701 33.912 ;
     RECT  48.604 60.912 48.701 61.752 ;
     RECT  48.604 25.152 48.737 29.592 ;
     RECT  48.604 35.232 48.737 40.056 ;
     RECT  48.665 54.144 48.737 54.168 ;
     RECT  48.604 16.272 48.755 22.776 ;
     RECT  48.604 41.04 48.755 45 ;
     RECT  48.665 59.808 48.755 59.832 ;
     RECT  48.701 60.912 48.755 60.936 ;
     RECT  48.604 6.24 48.773 9.576 ;
     RECT  48.755 43.008 48.773 45 ;
     RECT  48.604 46.848 48.773 47.112 ;
     RECT  48.773 43.008 48.781 43.512 ;
     RECT  48.604 11.088 48.796 14.136 ;
     RECT  48.773 6.24 48.803 6.264 ;
     RECT  48.701 32.976 48.803 33.864 ;
     RECT  48.755 19.824 48.845 22.776 ;
     RECT  48.781 43.008 48.845 43.032 ;
     RECT  48.773 46.848 48.845 46.872 ;
     RECT  48.604 2.256 48.851 5.208 ;
     RECT  48.604 30.576 48.851 31.896 ;
     RECT  48.604 55.968 48.881 56.28 ;
     RECT  48.755 41.04 48.917 41.976 ;
     RECT  48.665 50.592 48.947 52.536 ;
     RECT  48.275 0.096 48.953 0.216 ;
     RECT  48.773 7.44 48.953 9.576 ;
     RECT  48.737 37.392 48.953 40.056 ;
     RECT  48.881 56.256 48.953 56.28 ;
     RECT  48.953 0.096 48.989 0.12 ;
     RECT  48.755 16.272 48.989 18.84 ;
     RECT  48.803 32.976 48.989 33.576 ;
     RECT  48.737 35.232 48.989 36.072 ;
     RECT  48.851 3.072 49.025 5.208 ;
     RECT  48.953 7.44 49.025 7.464 ;
     RECT  48.989 17.376 49.025 18.84 ;
     RECT  48.737 25.152 49.025 29.112 ;
     RECT  48.917 41.04 49.025 41.16 ;
     RECT  48.947 50.592 49.025 51.816 ;
     RECT  48.845 19.824 49.043 21.816 ;
     RECT  49.025 25.248 49.043 29.112 ;
     RECT  49.025 41.136 49.043 41.16 ;
     RECT  48.773 44.976 49.043 45 ;
     RECT  49.025 50.592 49.043 51.72 ;
     RECT  48.953 8.832 49.061 9.576 ;
     RECT  48.796 11.952 49.061 14.136 ;
     RECT  48.851 30.576 49.061 30.6 ;
     RECT  48.953 37.392 49.061 39.336 ;
     RECT  49.043 50.832 49.061 51.72 ;
     RECT  48.989 32.976 49.069 33 ;
     RECT  49.043 26.208 49.089 29.112 ;
     RECT  49.025 18.192 49.091 18.84 ;
     RECT  49.061 50.832 49.091 50.856 ;
     RECT  49.043 21.792 49.097 21.816 ;
     RECT  49.089 26.208 49.097 28.92 ;
     RECT  48.851 31.872 49.097 31.896 ;
     RECT  48.989 35.232 49.097 35.256 ;
     RECT  49.061 13.392 49.169 13.416 ;
     RECT  49.043 19.824 49.169 20.616 ;
     RECT  49.097 28.896 49.169 28.92 ;
     RECT  49.061 12 49.205 12.072 ;
     RECT  49.097 26.208 49.205 27.672 ;
     RECT  49.061 37.968 49.205 39.24 ;
     RECT  49.169 19.824 49.241 20.136 ;
     RECT  49.205 37.968 49.241 38.472 ;
     RECT  49.025 3.072 49.277 4.536 ;
     RECT  49.061 8.832 49.331 9.288 ;
     RECT  49.205 12 49.331 12.024 ;
     RECT  48.989 16.272 49.379 16.344 ;
     RECT  49.379 16.272 49.385 16.296 ;
     RECT  49.205 27.648 49.421 27.672 ;
     RECT  48.604 24.096 49.427 24.12 ;
     RECT  49.205 26.208 49.427 26.376 ;
     RECT  49.091 18.816 49.457 18.84 ;
     RECT  49.241 19.968 49.468 20.136 ;
     RECT  49.277 3.936 49.475 4.536 ;
     RECT  49.331 9.264 49.493 9.288 ;
     RECT  49.427 26.208 49.501 26.232 ;
     RECT  49.475 3.936 49.571 3.96 ;
     RECT  49.468 19.968 49.609 19.992 ;
     RECT  49.241 37.968 50.641 38.376 ;
     RECT  50.641 37.968 50.713 38.472 ;
     RECT  50.713 37.968 51.649 38.568 ;
     RECT  51.649 37.968 51.761 38.664 ;
     RECT  51.761 38.064 51.804 38.664 ;
    LAYER M5 ;
     RECT  9.936 0.016 11.976 0.085 ;
     RECT  13.008 0.016 19.08 0.085 ;
     RECT  13.008 0.085 19.272 0.131 ;
     RECT  29.136 0.016 32.136 0.131 ;
     RECT  45.264 0.016 48.264 0.131 ;
     RECT  13.104 0.131 19.272 0.181 ;
     RECT  9.84 0.085 11.976 0.275 ;
     RECT  29.232 0.131 32.136 0.467 ;
     RECT  29.232 0.467 31.752 0.563 ;
     RECT  45.456 0.131 48.264 0.563 ;
     RECT  45.648 0.563 48.264 0.611 ;
     RECT  46.56 0.611 48.264 0.851 ;
     RECT  29.232 0.563 29.64 1.763 ;
     RECT  6.912 2.005 6.936 2.053 ;
     RECT  6.24 2.053 6.936 2.137 ;
     RECT  31.728 0.563 31.752 2.137 ;
     RECT  46.56 0.851 48.168 2.137 ;
     RECT  2.4 2.137 2.52 2.151 ;
     RECT  5.1 2.137 5.22 2.151 ;
     RECT  6.24 2.137 7.92 2.151 ;
     RECT  21.3 2.137 21.42 2.151 ;
     RECT  24 2.137 24.12 2.151 ;
     RECT  26.7 2.137 26.82 2.151 ;
     RECT  29.4 1.763 29.64 2.151 ;
     RECT  31.728 2.137 32.22 2.151 ;
     RECT  34.8 2.137 34.92 2.151 ;
     RECT  37.5 2.137 37.62 2.151 ;
     RECT  40.2 2.137 40.32 2.151 ;
     RECT  42.9 2.137 43.02 2.151 ;
     RECT  45.6 2.137 48.42 2.151 ;
     RECT  5.1 2.151 8.112 2.197 ;
     RECT  9.84 0.275 11.88 2.197 ;
     RECT  42.9 2.151 43.212 2.197 ;
     RECT  21.3 2.151 21.612 2.245 ;
     RECT  34.8 2.151 35.112 2.245 ;
     RECT  45.6 2.151 48.612 2.245 ;
     RECT  5.1 2.197 11.88 2.437 ;
     RECT  2.4 2.151 2.712 2.581 ;
     RECT  13.104 0.181 19.32 2.581 ;
     RECT  34.8 2.245 35.4 2.581 ;
     RECT  42.9 2.197 43.32 2.581 ;
     RECT  2.4 2.581 3.48 2.629 ;
     RECT  5.1 2.437 11.928 2.629 ;
     RECT  26.7 2.151 27.012 2.629 ;
     RECT  28.272 2.245 28.296 2.629 ;
     RECT  45.072 2.245 48.84 2.629 ;
     RECT  13.056 2.581 19.32 2.677 ;
     RECT  20.4 2.245 21.612 2.677 ;
     RECT  37.5 2.151 37.812 2.677 ;
     RECT  13.056 2.677 22.488 2.821 ;
     RECT  24 2.151 24.312 2.821 ;
     RECT  33.408 2.245 33.432 2.867 ;
     RECT  2.4 2.629 11.928 3.013 ;
     RECT  13.056 2.821 24.6 3.013 ;
     RECT  40.2 2.151 40.512 3.205 ;
     RECT  2.4 3.013 24.6 3.301 ;
     RECT  41.52 2.821 41.544 3.301 ;
     RECT  42.576 2.581 43.32 3.301 ;
     RECT  44.304 2.629 48.84 3.301 ;
     RECT  31.728 2.151 32.412 3.397 ;
     RECT  26.7 2.629 28.296 3.637 ;
     RECT  29.4 2.151 29.712 3.637 ;
     RECT  34.8 2.581 35.544 3.685 ;
     RECT  37.5 2.677 38.28 3.877 ;
     RECT  41.52 3.301 48.84 3.925 ;
     RECT  31.536 3.397 33.144 4.115 ;
     RECT  39.36 3.205 40.512 4.165 ;
     RECT  41.52 3.925 49.56 4.165 ;
     RECT  36.624 3.877 38.28 4.453 ;
     RECT  39.36 4.165 49.56 4.453 ;
     RECT  26.7 3.637 29.712 4.501 ;
     RECT  31.536 4.115 32.52 4.501 ;
     RECT  34.416 3.685 35.544 4.501 ;
     RECT  36.624 4.453 49.56 4.501 ;
     RECT  2.4 3.301 25.32 5.173 ;
     RECT  2.4 5.173 25.656 5.845 ;
     RECT  26.7 4.501 32.52 5.845 ;
     RECT  2.4 5.845 32.52 5.893 ;
     RECT  2.4 5.893 32.616 6.805 ;
     RECT  2.4 6.805 33.432 7.957 ;
     RECT  34.416 4.501 49.56 7.957 ;
     RECT  2.4 7.957 49.56 14.387 ;
     RECT  2.4 14.387 3.144 15.493 ;
     RECT  4.176 14.387 49.56 15.493 ;
     RECT  2.4 15.493 49.56 20.003 ;
     RECT  2.4 20.003 49.464 20.339 ;
     RECT  3.984 20.339 49.464 21.683 ;
     RECT  4.512 21.683 49.464 22.741 ;
     RECT  4.368 22.741 49.464 23.797 ;
     RECT  3.984 23.797 49.464 24.131 ;
     RECT  3.984 24.131 25.704 25.475 ;
     RECT  4.512 25.475 25.704 25.621 ;
     RECT  26.7 24.131 49.464 25.621 ;
     RECT  4.512 25.621 49.464 26.243 ;
     RECT  4.512 26.243 49.416 26.387 ;
     RECT  4.512 26.387 49.08 28.261 ;
     RECT  4.08 28.261 49.08 29.507 ;
     RECT  4.08 29.507 25.704 32.195 ;
     RECT  4.512 32.195 25.704 32.723 ;
     RECT  24 32.723 25.704 33.109 ;
     RECT  26.7 29.507 49.08 33.109 ;
     RECT  4.512 32.723 22.68 35.461 ;
     RECT  4.512 35.461 22.872 35.845 ;
     RECT  24 33.109 49.08 35.845 ;
     RECT  2.4 20.339 2.712 40.405 ;
     RECT  4.512 35.845 49.08 40.499 ;
     RECT  2.4 40.405 3.432 40.933 ;
     RECT  4.512 40.499 47.16 40.933 ;
     RECT  2.4 40.933 47.16 41.075 ;
     RECT  4.224 41.075 47.16 42.229 ;
     RECT  48.144 40.499 49.08 42.229 ;
     RECT  2.4 41.075 2.712 42.757 ;
     RECT  4.224 42.229 49.08 42.803 ;
     RECT  4.512 42.803 49.08 43.475 ;
     RECT  26.7 43.475 49.08 43.619 ;
     RECT  2.304 42.757 2.712 44.195 ;
     RECT  4.512 43.475 25.704 45.013 ;
     RECT  4.08 45.013 25.704 46.069 ;
     RECT  26.7 43.619 47.16 46.069 ;
     RECT  4.08 46.069 47.16 46.211 ;
     RECT  4.08 46.211 16.824 46.595 ;
     RECT  4.512 46.595 16.824 46.883 ;
     RECT  17.808 46.211 47.16 47.029 ;
     RECT  48.192 43.619 49.08 47.029 ;
     RECT  2.4 44.195 2.712 48.949 ;
     RECT  4.512 46.883 16.776 48.997 ;
     RECT  17.808 47.029 49.08 48.997 ;
     RECT  4.512 48.997 49.08 49.139 ;
     RECT  17.808 49.139 49.08 49.955 ;
     RECT  2.4 48.949 3.432 50.243 ;
     RECT  4.512 49.139 16.776 50.387 ;
     RECT  21.3 49.955 49.08 50.867 ;
     RECT  21.3 50.867 48.936 51.635 ;
     RECT  17.808 49.955 20.28 51.923 ;
     RECT  21.3 51.635 25.608 51.923 ;
     RECT  2.4 50.243 2.712 52.453 ;
     RECT  4.512 50.387 16.68 52.453 ;
     RECT  26.592 51.635 48.936 52.547 ;
     RECT  21.3 51.923 21.612 52.549 ;
     RECT  26.592 52.547 48.744 53.123 ;
     RECT  21.072 52.549 21.612 53.315 ;
     RECT  2.4 52.453 16.68 53.509 ;
     RECT  17.808 51.923 19.656 53.509 ;
     RECT  26.7 53.123 48.744 53.555 ;
     RECT  2.4 53.509 19.656 53.603 ;
     RECT  2.4 53.603 17.208 53.843 ;
     RECT  26.7 53.555 29.832 54.949 ;
     RECT  2.4 53.843 16.68 55.237 ;
     RECT  31.008 53.555 48.744 55.331 ;
     RECT  18.6 53.603 19.656 55.861 ;
     RECT  2.304 55.237 16.68 55.955 ;
     RECT  48.192 55.331 48.744 56.051 ;
     RECT  21.3 53.315 21.612 56.245 ;
     RECT  22.656 51.923 25.608 56.245 ;
     RECT  48.192 56.051 48.612 56.291 ;
     RECT  26.7 54.949 29.88 56.341 ;
     RECT  2.304 55.955 2.712 56.483 ;
     RECT  18.6 55.861 19.992 56.917 ;
     RECT  21.3 56.245 25.608 56.917 ;
     RECT  26.592 56.341 29.88 57.013 ;
     RECT  31.008 55.331 46.536 57.013 ;
     RECT  48.3 56.291 48.612 57.445 ;
     RECT  18.6 56.917 25.608 57.635 ;
     RECT  26.592 57.013 46.536 58.163 ;
     RECT  26.592 58.163 29.832 58.355 ;
     RECT  48.192 57.445 48.612 58.453 ;
     RECT  4.512 55.955 16.68 58.645 ;
     RECT  18.6 57.635 21.612 58.645 ;
     RECT  26.7 58.355 29.832 59.221 ;
     RECT  31.008 58.163 46.536 59.221 ;
     RECT  26.7 59.221 46.536 59.459 ;
     RECT  18.48 58.645 21.612 59.555 ;
     RECT  47.712 58.453 48.612 59.797 ;
     RECT  26.7 59.459 36.408 59.987 ;
     RECT  37.5 59.459 46.536 60.035 ;
     RECT  4.464 58.645 16.68 60.181 ;
     RECT  3.744 60.181 17.16 60.373 ;
     RECT  18.48 59.555 19.992 60.373 ;
     RECT  47.712 59.797 48.744 60.947 ;
     RECT  22.656 57.635 25.608 60.949 ;
     RECT  26.7 59.987 29.832 60.949 ;
     RECT  47.712 60.947 48.612 61.187 ;
     RECT  3.744 60.373 19.992 61.235 ;
     RECT  3.744 61.235 19.656 61.475 ;
     RECT  22.656 60.949 29.832 61.619 ;
     RECT  37.5 60.035 46.008 61.621 ;
     RECT  4.512 61.475 19.656 61.907 ;
     RECT  4.512 61.907 16.68 62.195 ;
     RECT  31.008 59.987 36.408 62.243 ;
     RECT  37.5 61.621 46.152 62.435 ;
     RECT  22.656 61.619 25.608 62.581 ;
     RECT  26.7 61.619 29.832 62.581 ;
     RECT  2.4 56.483 2.712 62.649 ;
     RECT  21.3 59.555 21.612 62.649 ;
     RECT  37.5 62.435 45.912 62.649 ;
     RECT  48.3 61.187 48.612 62.649 ;
     RECT  2.4 62.649 2.52 62.663 ;
     RECT  10.5 62.195 16.68 62.663 ;
     RECT  18.6 61.907 19.656 62.663 ;
     RECT  21.3 62.649 21.42 62.663 ;
     RECT  22.656 62.581 29.832 62.663 ;
     RECT  31.008 62.243 35.688 62.663 ;
     RECT  37.5 62.649 45.72 62.663 ;
     RECT  48.3 62.649 48.42 62.663 ;
     RECT  16.368 62.663 16.68 62.963 ;
     RECT  10.992 62.663 15.336 63.251 ;
     RECT  19.632 62.663 19.656 63.539 ;
     RECT  4.512 62.195 9.528 63.779 ;
     RECT  27.696 62.663 29.832 63.827 ;
     RECT  43.728 62.663 44.904 63.827 ;
     RECT  4.56 63.779 9.528 63.829 ;
     RECT  10.992 63.251 12.888 63.875 ;
     RECT  22.656 62.663 25.944 63.875 ;
     RECT  38.544 62.663 39.768 63.875 ;
     RECT  40.944 62.663 42.696 63.875 ;
     RECT  38.544 63.875 39.72 63.923 ;
     RECT  39.696 63.923 39.72 63.971 ;
     RECT  32.88 62.663 35.688 64.309 ;
     RECT  32.88 64.309 35.784 64.501 ;
     RECT  32.784 64.501 35.784 64.549 ;
     RECT  22.704 63.875 25.944 64.643 ;
     RECT  43.728 63.827 44.568 64.643 ;
     RECT  14.16 63.251 15.336 64.691 ;
     RECT  31.008 62.663 31.704 64.691 ;
     RECT  32.688 64.549 35.784 64.691 ;
     RECT  41.424 63.875 42.696 64.691 ;
     RECT  43.92 64.643 44.568 64.691 ;
     RECT  10.992 63.875 11.016 64.739 ;
     RECT  12.144 63.875 12.888 64.739 ;
     RECT  16.368 62.963 16.392 64.739 ;
     RECT  27.696 63.827 29.016 64.739 ;
     RECT  31.68 64.691 31.704 64.739 ;
     RECT  38.544 63.923 38.568 64.739 ;
     RECT  42.528 64.691 42.552 64.739 ;
     RECT  43.92 64.691 43.944 64.739 ;
     RECT  4.56 63.829 9.576 64.784 ;
     RECT  22.704 64.643 25.704 64.784 ;
     RECT  32.688 64.691 35.688 64.784 ;
  END
END dsfd_dvland_276l
END LIBRARY
